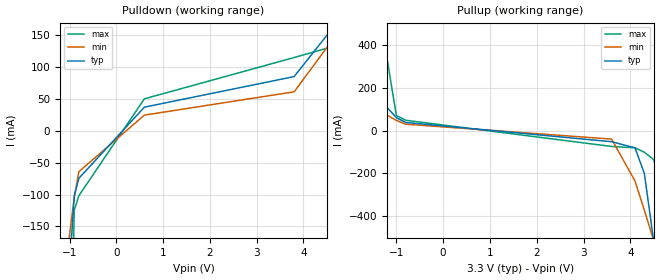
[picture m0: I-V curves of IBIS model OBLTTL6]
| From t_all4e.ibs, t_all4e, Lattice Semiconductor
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|   OBLTTL6
[Model]   OBLTTL6
Model_type   Output
Polarity   Non-Inverting
C_comp   2pF   2pF   2pF
[Temperature Range]   25.0000   125.0000   -40.0000
[Voltage Range]   3.3000V   3.0000V   3.6000V
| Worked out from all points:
|   slope of the pulldown table from 0 to 0.495 V, typ, clamps not added: 16.1 ohm
|   slope of the pullup table from 0 to 0.495 V, typ, clamps not added: 23.4 ohm
[Pulldown]
|voltage   I(typ)   I(min)   I(max)
-3.3V     -4.436A    -1.817A    -40.52A
-1.2V     -495.4mA   -285.6mA   -2.518A
-1.1V     -333.9mA   -220.6mA   -1.039A
-900mV    -102.6mA   -106.1mA   -124.8mA
-800mV    -74.67mA   -64.3mA    -101.9mA
600mV     36.53mA    24.07mA    49.56mA
3.8V      84.32mA    60.53mA    114.1mA
4.6V      158mA      139.6mA    130.7mA
4.8V      207.7mA    168.8mA    333.2mA
5.1V      290.8mA    217.3mA    813.3mA
5.4V      381.5mA    270mA      1.325A
6.6V      773.3mA    501.2mA    3.461A
[Pullup]
|voltage   I(typ)   I(min)   I(max)
-3.3V     752.9mA    436.3mA    3.973A
-2.5V     488.3mA    278.6mA    2.529A
-1.4V     155.1mA    96.47mA    603.1mA
-1V       59.98mA    47.2mA     69.78mA
-800mV    37.72mA    29.55mA    47.83mA
3.6V      -52.17mA   -39.93mA   -74.27mA
4.1V      -80.98mA   -235.7mA   -80.58mA
4.3V      -200.9mA   -372.2mA   -101.3mA
4.5V      -517.8mA   -513.7mA   -135.4mA
4.6V      -693.7mA   -585.4mA   -222mA
4.7V      -873.8mA   -657.6mA   -1.058A
6.6V      -4.462A    -2.062A    -35.02A
[Ramp]
| variable   typ   min   max
dV/dt_r   1.2315/1.0200ns   0.8308/2.3607ns   1.5922/0.3789ns
dV/dt_f   1.4788/1.1048ns   1.1687/2.4507ns   1.7342/0.5175ns
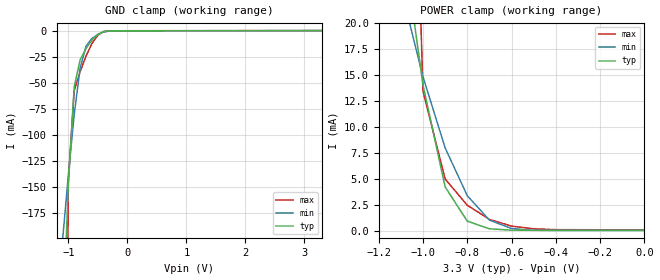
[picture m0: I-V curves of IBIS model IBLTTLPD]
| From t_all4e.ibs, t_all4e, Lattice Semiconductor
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|   IBLTTLPD
[Model]   IBLTTLPD
Model_type   Input
Polarity   Non-Inverting
C_comp   2pF   2pF   2pF
Vinl = 0.5
Vinh = 2.64
[Temperature Range]   25.0000   125.0000   -40.0000
[Voltage Range]   3.3000V   3.0000V   3.6000V
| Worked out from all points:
|   GND clamp passes 1 mA (typ) near -0.40 V on its own axis
|   POWER clamp passes 1 mA (typ) near -0.80 V on its own axis
[GND_clamp]
|voltage   I(typ)   I(min)   I(max)
-3.3V     -4.405A    -1.803A    -40.47A
-1.1V     -296.4mA   -202.8mA   -979.3mA
-1V       -147.6mA   -138.6mA   -143.7mA
-900mV    -53.79mA   -80.42mA   -57.6mA
-800mV    -28.05mA   -35.98mA   -39.41mA
-700mV    -17.1mA    -14.8mA    -24.33mA
-600mV    -8.999mA   -7.523mA   -12.36mA
-500mV    -3.595mA   -3.617mA   -4.359mA
-400mV    -879.9uA   -1.324mA   -818.8uA
-300mV    -134.5uA   -303.4uA   -113.2uA
3.3V      27.16uA    10.44uA    65.22uA
[POWER_clamp]
|voltage   I(typ)   I(min)   I(max)
-3.3V     682mA      379.6mA    3.878A
-1.1V     29.47mA    23.43mA    82.94mA
-1V       14.05mA    14.85mA    13.46mA
-900mV    4.218mA    7.985mA    4.978mA
-800mV    910uA      3.369mA    2.448mA
-700mV    172.8uA    1.011mA    1.084mA
-600mV    39.84uA    197.6uA    429.9uA
-500mV    27.92uA    30.49uA    170.3uA
-400mV    27.27uA    11.82uA    89.74uA
0V        27.16uA    10.3uA     65.38uA
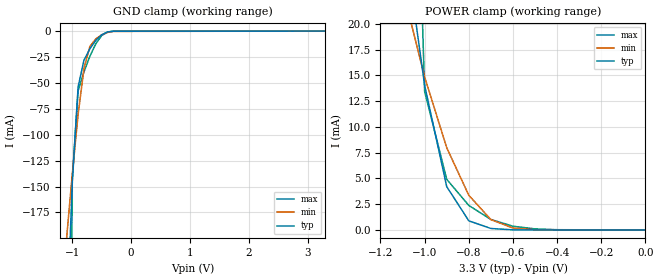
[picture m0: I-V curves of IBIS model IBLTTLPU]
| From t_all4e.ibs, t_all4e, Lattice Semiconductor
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|   IBLTTLPU
[Model]   IBLTTLPU
Model_type   Input
Polarity   Non-Inverting
C_comp   2pF   2pF   2pF
Vinl = 0.5
Vinh = 2.64
[Temperature Range]   25.0000   125.0000   -40.0000
[Voltage Range]   3.3000V   3.0000V   3.6000V
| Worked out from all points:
|   GND clamp passes 1 mA (typ) near -0.41 V on its own axis
|   POWER clamp passes 1 mA (typ) near -0.80 V on its own axis
[GND_clamp]
|voltage   I(typ)   I(min)   I(max)
-3.3V     -4.405A    -1.803A    -40.47A
-1.1V     -296.4mA   -202.8mA   -979.3mA
-1V       -147.6mA   -138.6mA   -143.7mA
-900mV    -53.78mA   -80.42mA   -57.54mA
-800mV    -28.01mA   -35.97mA   -39.33mA
-700mV    -17.06mA   -14.8mA    -24.26mA
-600mV    -8.965mA   -7.508mA   -12.31mA
-500mV    -3.57mA    -3.604mA   -4.321mA
-400mV    -864.4uA   -1.316mA   -796uA
-300mV    -129.4uA   -300.8uA   -106.6uA
3.3V      136.3nA    1.082uA    44.16nA
[POWER_clamp]
|voltage   I(typ)   I(min)   I(max)
-3.3V     682mA      379.6mA    3.878A
-1.1V     29.47mA    23.43mA    82.94mA
-1V       14.04mA    14.85mA    13.44mA
-900mV    4.209mA    7.985mA    4.915mA
-800mV    886uA      3.367mA    2.382mA
-700mV    145.7uA    1.006mA    1.019mA
-600mV    12.72uA    189uA      364.4uA
-500mV    804.9nA    21.16uA    104.9uA
-400mV    169.6nA    2.448uA    24.33uA
0V        136.3nA    964.9nA    94.06nA
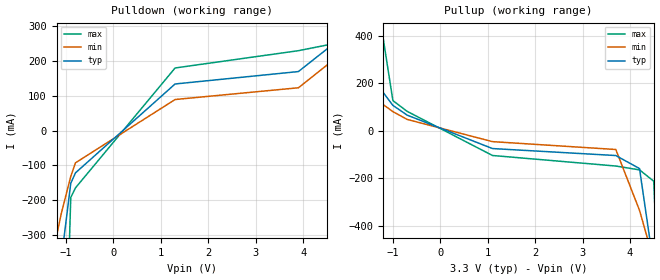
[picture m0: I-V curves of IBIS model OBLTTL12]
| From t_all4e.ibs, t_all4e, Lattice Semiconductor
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|   OBLTTL12
[Model]   OBLTTL12
Model_type   Output
Polarity   Non-Inverting
C_comp   2pF   2pF   2pF
[Temperature Range]   25.0000   125.0000   -40.0000
[Voltage Range]   3.3000V   3.0000V   3.6000V
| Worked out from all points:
|   slope of the pulldown table from 0 to 0.495 V, typ, clamps not added: 8.06 ohm
|   slope of the pullup table from 0 to 0.495 V, typ, clamps not added: 11.7 ohm
[Pulldown]
|voltage   I(typ)   I(min)   I(max)
-3.3V     -4.467A    -1.832A    -40.58A
-1.3V     -697.2mA   -368.1mA   -4.22A
-1.1V     -371.3mA   -238.3mA   -1.098A
-900mV    -151.4mA   -131.8mA   -192.1mA
-800mV    -121.4mA   -92.63mA   -164.5mA
1.3V      133.6mA    88.99mA    179.5mA
3.9V      169.2mA    122.7mA    229.1mA
4.6V      244.5mA    198.3mA    248mA
4.8V      294.8mA    227.9mA    451.2mA
5.1V      378.6mA    277mA      932.3mA
5.6V      533.5mA    367.2mA    1.795A
6.6V      864.6mA    563.3mA    3.585A
[Pullup]
|voltage   I(typ)   I(min)   I(max)
-3.3V     834.5mA    497.2mA    4.082A
-2.4V     531.4mA    315.7mA    2.447A
-1.4V     215.2mA    138.4mA    678.7mA
-1.3V     185.7mA    122.9mA    509.7mA
-1V       105.9mA    79.59mA    126.1mA
-700mV    64.88mA    46.78mA    80.73mA
1.1V      -75.92mA   -46.77mA   -105.1mA
3.7V      -105.3mA   -79.86mA   -149.4mA
4.2V      -160.1mA   -336.1mA   -165.7mA
4.5V      -571.5mA   -547mA     -213.3mA
4.7V      -927.9mA   -691.1mA   -1.137A
6.6V      -4.519A    -2.097A    -35.11A
[Ramp]
| variable   typ   min   max
dV/dt_r   1.5768/0.5268ns   1.2363/1.5430ns   1.8671/0.1960ns
dV/dt_f   1.7097/0.6904ns   1.4405/1.5774ns   1.9424/0.3192ns
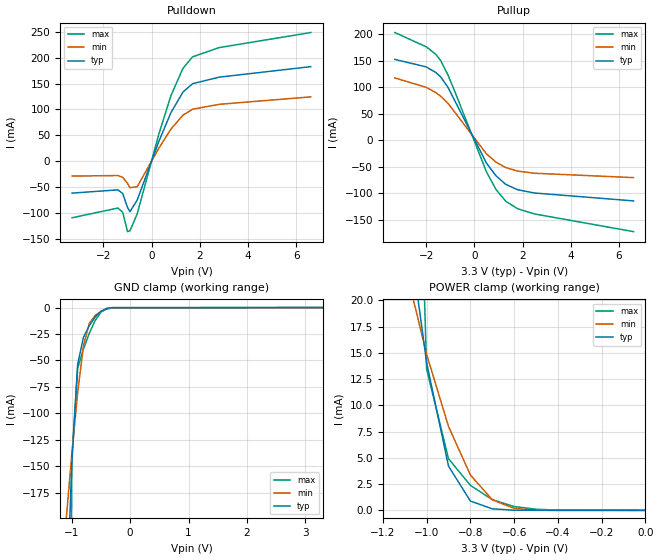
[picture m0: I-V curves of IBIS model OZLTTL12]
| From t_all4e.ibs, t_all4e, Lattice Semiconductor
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|   OZLTTL12
[Model]   OZLTTL12
Model_type   3-state
Polarity   Non-Inverting
Enable   Active-Low
C_comp   2pF   2pF   2pF
[Temperature Range]   25.0000   125.0000   -40.0000
[Voltage Range]   3.3000V   3.0000V   3.6000V
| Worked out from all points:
|   slope of the pulldown table from 0 to 0.495 V, typ, clamps not added: 8.06 ohm
|   slope of the pullup table from 0 to 0.495 V, typ, clamps not added: 11.7 ohm
|   GND clamp passes 1 mA (typ) near -0.41 V on its own axis
|   POWER clamp passes 1 mA (typ) near -0.80 V on its own axis
[Pulldown]
|voltage   I(typ)   I(min)   I(max)
-3.3V     -61.75mA   -28.81mA   -109.4mA
-1.4V     -55.45mA   -27.84mA   -90.61mA
-1.2V     -62.59mA   -31.19mA   -98.81mA
-1V       -89.62mA   -43.02mA   -136.2mA
-900mV    -97.6mA    -51.34mA   -134.6mA
-600mV    -75.27mA   -49.45mA   -102mA
300mV     38.39mA    25.14mA    52.57mA
800mV     93.76mA    61.98mA    126.6mA
1.3V      133.6mA    88.99mA    179.5mA
1.7V      149.7mA    100.4mA    201.6mA
2.8V      162.3mA    109.8mA    219.4mA
6.6V      182.6mA    124.2mA    248.5mA
[Pullup]
|voltage   I(typ)   I(min)   I(max)
-3.3V     152.5mA    117.6mA    203.1mA
-2V       138.4mA    99.96mA    176.3mA
-1.6V     127.9mA    90.05mA    162.3mA
-1.4V     119.7mA    83.23mA    150.6mA
-1.1V     100.3mA    70.12mA    123.6mA
-800mV    73.67mA    52.36mA    90.9mA
500mV     -42.74mA   -25.36mA   -59.21mA
900mV     -66.84mA   -41.03mA   -92.77mA
1.3V      -82.82mA   -51.19mA   -114.6mA
1.8V      -93.06mA   -57.92mA   -128.9mA
2.5V      -99.14mA   -61.92mA   -138.6mA
6.6V      -114mA     -70.13mA   -171.9mA
[GND_clamp]
|voltage   I(typ)   I(min)   I(max)
-3.3V     -4.405A    -1.803A    -40.47A
-1.1V     -296.4mA   -202.8mA   -979.3mA
-1V       -147.6mA   -138.6mA   -143.7mA
-900mV    -53.77mA   -80.42mA   -57.51mA
-800mV    -28mA      -35.97mA   -39.29mA
-700mV    -17.04mA   -14.79mA   -24.22mA
-600mV    -8.941mA   -7.498mA   -12.27mA
-500mV    -3.546mA   -3.592mA   -4.281mA
-400mV    -840.6uA   -1.303mA   -756.1uA
-300mV    -105.6uA   -288uA     -66.64uA
3.3V      136.3nA    1.082uA    44.16nA
[POWER_clamp]
|voltage   I(typ)   I(min)   I(max)
-3.3V     682mA      379.6mA    3.878A
-1.1V     29.47mA    23.43mA    82.94mA
-1V       14.04mA    14.85mA    13.44mA
-900mV    4.209mA    7.985mA    4.915mA
-800mV    886uA      3.367mA    2.382mA
-700mV    145.7uA    1.006mA    1.019mA
-600mV    12.72uA    189uA      364.4uA
-500mV    804.9nA    21.16uA    104.9uA
-400mV    169.6nA    2.448uA    24.33uA
0V        136.3nA    964.9nA    94.06nA
[Ramp]
| variable   typ   min   max
dV/dt_r   1.5768/0.5268ns   1.2363/1.5430ns   1.8671/0.1960ns
dV/dt_f   1.7097/0.6904ns   1.4405/1.5774ns   1.9424/0.3192ns
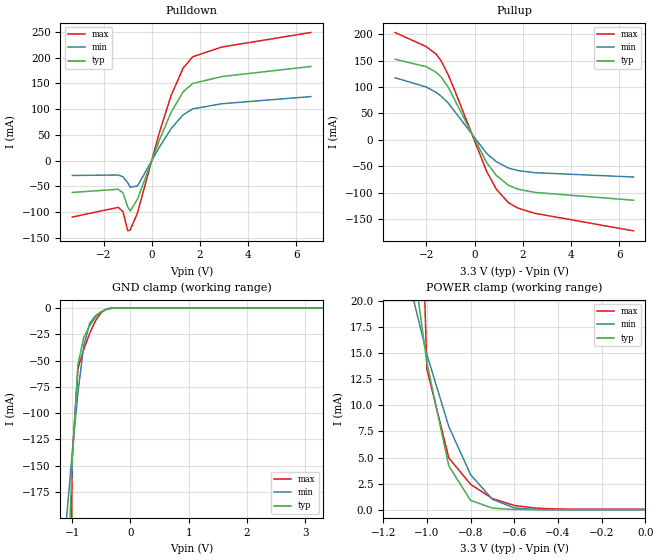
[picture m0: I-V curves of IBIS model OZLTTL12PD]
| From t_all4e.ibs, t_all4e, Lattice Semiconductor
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|   OZLTTL12PD
[Model]   OZLTTL12PD
Model_type   3-state
Polarity   Non-Inverting
Enable   Active-Low
C_comp   2pF   2pF   2pF
[Temperature Range]   25.0000   125.0000   -40.0000
[Voltage Range]   3.3000V   3.0000V   3.6000V
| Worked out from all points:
|   slope of the pulldown table from 0 to 0.495 V, typ, clamps not added: 8.07 ohm
|   slope of the pullup table from 0 to 0.495 V, typ, clamps not added: 11.7 ohm
|   GND clamp passes 1 mA (typ) near -0.40 V on its own axis
|   POWER clamp passes 1 mA (typ) near -0.80 V on its own axis
[Pulldown]
|voltage   I(typ)   I(min)   I(max)
-3.3V     -61.75mA   -28.81mA   -109.4mA
-1.4V     -55.45mA   -27.84mA   -90.61mA
-1.2V     -62.59mA   -31.19mA   -98.8mA
-1V       -89.61mA   -43.02mA   -136.2mA
-900mV    -97.58mA   -51.33mA   -134.5mA
-600mV    -75.21mA   -49.43mA   -101.9mA
300mV     38.37mA    25.13mA    52.53mA
800mV     93.72mA    61.97mA    126.5mA
1.3V      133.5mA    88.97mA    179.4mA
1.7V      149.6mA    100.4mA    201.5mA
2.9V      163mA      110.3mA    220.3mA
6.6V      182.6mA    124.2mA    248.5mA
[Pullup]
|voltage   I(typ)   I(min)   I(max)
-3.3V     152.5mA    117.6mA    203.1mA
-2V       138.4mA    99.96mA    176.3mA
-1.6V     127.9mA    90.05mA    162.3mA
-1.4V     119.7mA    83.23mA    150.6mA
-1.1V     100.3mA    70.12mA    123.6mA
-800mV    73.65mA    52.36mA    90.83mA
500mV     -42.76mA   -25.37mA   -59.27mA
900mV     -66.88mA   -41.05mA   -92.86mA
1.4V      -85.62mA   -52.99mA   -118.4mA
1.8V      -93.1mA    -57.94mA   -129mA
2.5V      -99.19mA   -61.94mA   -138.7mA
6.6V      -114mA     -70.13mA   -171.9mA
[GND_clamp]
|voltage   I(typ)   I(min)   I(max)
-3.3V     -4.405A    -1.803A    -40.47A
-1.1V     -296.4mA   -202.8mA   -979.3mA
-1V       -147.6mA   -138.6mA   -143.7mA
-900mV    -53.79mA   -80.42mA   -57.6mA
-800mV    -28.05mA   -35.98mA   -39.41mA
-700mV    -17.1mA    -14.8mA    -24.33mA
-600mV    -8.999mA   -7.523mA   -12.36mA
-500mV    -3.595mA   -3.617mA   -4.359mA
-400mV    -879.9uA   -1.324mA   -818.8uA
-300mV    -134.5uA   -303.4uA   -113.2uA
3.3V      27.16uA    10.44uA    65.22uA
[POWER_clamp]
|voltage   I(typ)   I(min)   I(max)
-3.3V     682mA      379.6mA    3.878A
-1.1V     29.47mA    23.43mA    82.94mA
-1V       14.05mA    14.85mA    13.46mA
-900mV    4.218mA    7.985mA    4.978mA
-800mV    910uA      3.369mA    2.448mA
-700mV    172.8uA    1.011mA    1.084mA
-600mV    39.84uA    197.6uA    429.9uA
-500mV    27.92uA    30.49uA    170.3uA
-400mV    27.27uA    11.82uA    89.74uA
0V        27.16uA    10.3uA     65.38uA
[Ramp]
| variable   typ   min   max
dV/dt_r   1.5768/0.5268ns   1.2363/1.5430ns   1.8671/0.1960ns
dV/dt_f   1.7097/0.6904ns   1.4405/1.5774ns   1.9424/0.3192ns
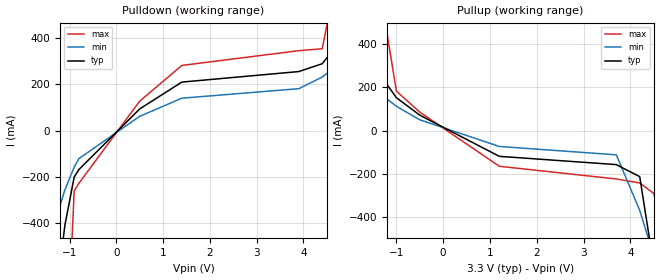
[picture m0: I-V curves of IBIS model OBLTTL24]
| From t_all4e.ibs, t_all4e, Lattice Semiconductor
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|   OBLTTL24
[Model]   OBLTTL24
Model_type   Output
Polarity   Non-Inverting
C_comp   2pF   2pF   2pF
[Temperature Range]   25.0000   125.0000   -40.0000
[Voltage Range]   3.3000V   3.0000V   3.6000V
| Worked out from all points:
|   slope of the pulldown table from 0 to 0.495 V, typ, clamps not added: 5.38 ohm
|   slope of the pullup table from 0 to 0.495 V, typ, clamps not added: 7.79 ohm
[Pulldown]
|voltage   I(typ)   I(min)   I(max)
-3.3V     -4.498A    -1.846A    -40.63A
-1.4V     -903mA     -451.1mA   -5.99A
-1.1V     -408.8mA   -256.1mA   -1.157A
-900mV    -200.2mA   -157.4mA   -259.4mA
-800mV    -168mA     -121mA     -227.2mA
500mV     92.94mA    61.11mA    126.4mA
1.4V      208.4mA    139.1mA    280.1mA
3.9V      253.8mA    180.1mA    343.6mA
4.4V      287.4mA    230.2mA    351.9mA
5.1V      466.4mA    336.6mA    1.051A
5.7V      655mA      446.7mA    2.093A
6.6V      955.9mA    625.4mA    3.709A
[Pullup]
|voltage   I(typ)   I(min)   I(max)
-3.3V     916.1mA    558.1mA    4.19A
-2.3V     572.9mA    351.3mA    2.362A
-1.3V     243mA      162.7mA    581.2mA
-1V       151.9mA    112mA      182.5mA
-500mV    71.07mA    49.53mA    85.15mA
1.2V      -119.4mA   -73.7mA    -165.3mA
3.7V      -157.6mA   -112.4mA   -224mA
4.2V      -213.3mA   -369.2mA   -242.4mA
4.5V      -625.2mA   -580.3mA   -291.2mA
4.6V      -801.4mA   -652.2mA   -378.6mA
4.7V      -981.9mA   -724.6mA   -1.215A
6.6V      -4.576A    -2.132A    -35.2A
[Ramp]
| variable   typ   min   max
dV/dt_r   1.7021/0.3465ns   1.3998/1.0389ns   1.9655/0.1535ns
dV/dt_f   1.7950/0.5692ns   1.5442/1.2795ns   2.0177/0.2629ns
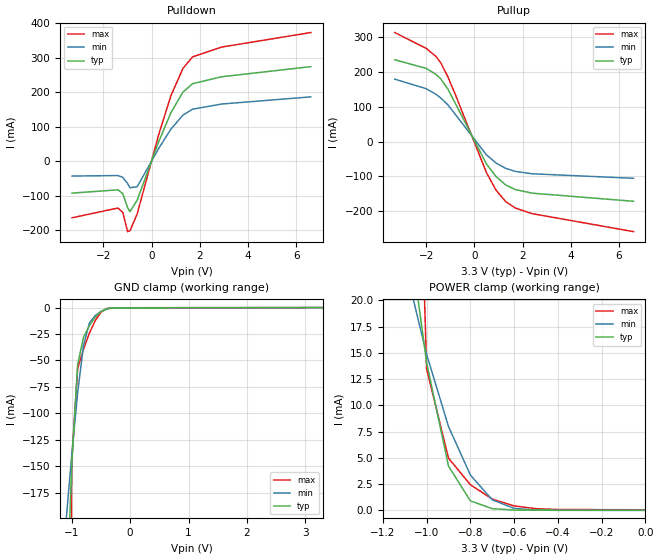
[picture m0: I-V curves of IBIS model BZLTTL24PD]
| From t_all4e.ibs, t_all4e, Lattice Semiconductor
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|   BZLTTL24PD
[Model]   BZLTTL24PD
Model_type   I/O
Polarity   Non-Inverting
Enable   Active-Low
C_comp   2pF   2pF   2pF
Vinl = 0.5
Vinh = 2.64
[Temperature Range]   25.0000   125.0000   -40.0000
[Voltage Range]   3.3000V   3.0000V   3.6000V
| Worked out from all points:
|   slope of the pulldown table from 0 to 0.495 V, typ, clamps not added: 5.38 ohm
|   slope of the pullup table from 0 to 0.495 V, typ, clamps not added: 7.79 ohm
|   GND clamp passes 1 mA (typ) near -0.40 V on its own axis
|   POWER clamp passes 1 mA (typ) near -0.80 V on its own axis
[Pulldown]
|voltage   I(typ)   I(min)   I(max)
-3.3V     -92.63mA   -43.21mA   -164.1mA
-1.4V     -83.18mA   -41.77mA   -135.9mA
-1.2V     -93.88mA   -46.78mA   -148.2mA
-1V       -134.4mA   -64.53mA   -204.3mA
-900mV    -146.4mA   -77mA      -201.8mA
-600mV    -112.8mA   -74.16mA   -152.9mA
300mV     57.56mA    37.7mA     78.81mA
800mV     140.6mA    92.96mA    189.8mA
1.3V      200.3mA    133.5mA    269.1mA
1.7V      224.5mA    150.6mA    302.3mA
2.9V      244.5mA    165.5mA    330.5mA
6.6V      273.9mA    186.3mA    372.7mA
[Pullup]
|voltage   I(typ)   I(min)   I(max)
-3.3V     234.1mA    178.5mA    312mA
-2V       209.4mA    151.3mA    266.7mA
-1.6V     192.5mA    135.6mA    244.2mA
-1.4V     179.8mA    125.1mA    226.2mA
-1.1V     150.4mA    105.2mA    185.4mA
-800mV    110.5mA    78.55mA    136.3mA
500mV     -64.13mA   -38.05mA   -88.87mA
900mV     -100.3mA   -61.56mA   -139.3mA
1.3V      -124.3mA   -76.81mA   -171.9mA
1.7V      -137.5mA   -85.45mA   -190.3mA
2.4V      -147.8mA   -92.32mA   -206.4mA
6.6V      -171mA     -105.2mA   -257.9mA
[GND_clamp]
|voltage   I(typ)   I(min)   I(max)
-3.3V     -4.405A    -1.803A    -40.47A
-1.1V     -296.4mA   -202.8mA   -979.3mA
-1V       -147.6mA   -138.6mA   -143.7mA
-900mV    -53.79mA   -80.42mA   -57.6mA
-800mV    -28.05mA   -35.98mA   -39.41mA
-700mV    -17.1mA    -14.8mA    -24.33mA
-600mV    -8.999mA   -7.523mA   -12.36mA
-500mV    -3.595mA   -3.617mA   -4.359mA
-400mV    -879.9uA   -1.324mA   -818.8uA
-300mV    -134.5uA   -303.4uA   -113.2uA
3.3V      27.16uA    10.44uA    65.22uA
[POWER_clamp]
|voltage   I(typ)   I(min)   I(max)
-3.3V     682mA      379.6mA    3.878A
-1.1V     29.47mA    23.43mA    82.94mA
-1V       14.05mA    14.85mA    13.46mA
-900mV    4.218mA    7.985mA    4.978mA
-800mV    910uA      3.369mA    2.448mA
-700mV    172.8uA    1.011mA    1.084mA
-600mV    39.84uA    197.6uA    429.9uA
-500mV    27.92uA    30.49uA    170.3uA
-400mV    27.27uA    11.82uA    89.74uA
0V        27.16uA    10.3uA     65.38uA
[Ramp]
| variable   typ   min   max
dV/dt_r   1.7021/0.3465ns   1.3998/1.0389ns   1.9655/0.1535ns
dV/dt_f   1.7950/0.5692ns   1.5442/1.2795ns   2.0177/0.2629ns
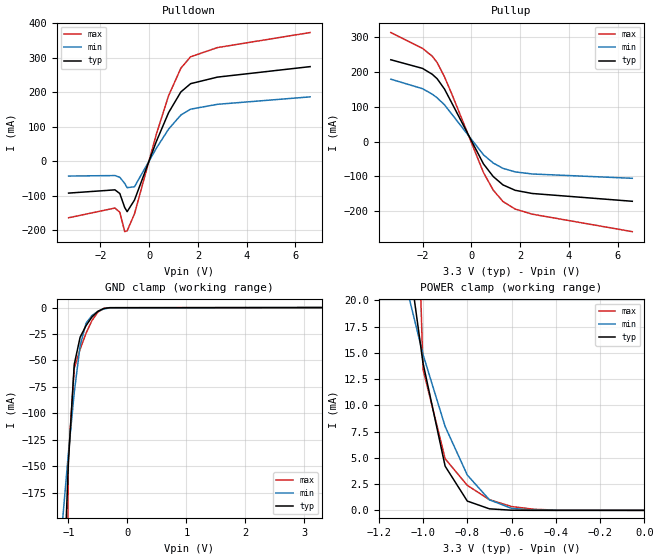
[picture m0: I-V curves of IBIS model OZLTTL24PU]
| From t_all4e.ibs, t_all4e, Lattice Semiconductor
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|   OZLTTL24PU
[Model]   OZLTTL24PU
Model_type   3-state
Polarity   Non-Inverting
Enable   Active-Low
C_comp   2pF   2pF   2pF
[Temperature Range]   25.0000   125.0000   -40.0000
[Voltage Range]   3.3000V   3.0000V   3.6000V
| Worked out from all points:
|   slope of the pulldown table from 0 to 0.495 V, typ, clamps not added: 5.38 ohm
|   slope of the pullup table from 0 to 0.495 V, typ, clamps not added: 7.79 ohm
|   GND clamp passes 1 mA (typ) near -0.41 V on its own axis
|   POWER clamp passes 1 mA (typ) near -0.80 V on its own axis
[Pulldown]
|voltage   I(typ)   I(min)   I(max)
-3.3V     -92.63mA   -43.21mA   -164.1mA
-1.4V     -83.18mA   -41.77mA   -135.9mA
-1.2V     -93.89mA   -46.78mA   -148.2mA
-1V       -134.4mA   -64.53mA   -204.3mA
-900mV    -146.4mA   -77mA      -201.9mA
-600mV    -112.9mA   -74.17mA   -153mA
300mV     57.61mA    37.72mA    78.89mA
800mV     140.7mA    92.99mA    189.9mA
1.3V      200.4mA    133.5mA    269.2mA
1.7V      224.5mA    150.6mA    302.4mA
2.8V      243.5mA    164.7mA    329.1mA
6.6V      273.9mA    186.3mA    372.7mA
[Pullup]
|voltage   I(typ)   I(min)   I(max)
-3.3V     234.1mA    178.5mA    312mA
-2V       209.4mA    151.3mA    266.7mA
-1.6V     192.5mA    135.6mA    244.2mA
-1.4V     179.8mA    125.1mA    226.2mA
-1.1V     150.4mA    105.2mA    185.4mA
-800mV    110.5mA    78.55mA    136.3mA
500mV     -64.1mA    -38.04mA   -88.81mA
900mV     -100.2mA   -61.53mA   -139.1mA
1.3V      -124.2mA   -76.78mA   -171.8mA
1.8V      -139.6mA   -86.86mA   -193.3mA
2.5V      -148.7mA   -92.87mA   -207.9mA
6.6V      -171mA     -105.2mA   -257.9mA
[GND_clamp]
|voltage   I(typ)   I(min)   I(max)
-3.3V     -4.405A    -1.803A    -40.47A
-1.1V     -296.4mA   -202.8mA   -979.3mA
-1V       -147.6mA   -138.6mA   -143.7mA
-900mV    -53.78mA   -80.42mA   -57.54mA
-800mV    -28.01mA   -35.97mA   -39.33mA
-700mV    -17.06mA   -14.8mA    -24.26mA
-600mV    -8.965mA   -7.508mA   -12.31mA
-500mV    -3.57mA    -3.604mA   -4.321mA
-400mV    -864.4uA   -1.316mA   -796uA
-300mV    -129.4uA   -300.8uA   -106.6uA
3.3V      136.3nA    1.082uA    44.16nA
[POWER_clamp]
|voltage   I(typ)   I(min)   I(max)
-3.3V     682mA      379.6mA    3.878A
-1.1V     29.47mA    23.43mA    82.94mA
-1V       14.04mA    14.85mA    13.44mA
-900mV    4.209mA    7.985mA    4.915mA
-800mV    886uA      3.367mA    2.382mA
-700mV    145.7uA    1.006mA    1.019mA
-600mV    12.72uA    189uA      364.4uA
-500mV    804.9nA    21.16uA    104.9uA
-400mV    169.6nA    2.448uA    24.33uA
0V        136.3nA    964.9nA    94.06nA
[Ramp]
| variable   typ   min   max
dV/dt_r   1.7021/0.3465ns   1.3998/1.0389ns   1.9655/0.1535ns
dV/dt_f   1.7950/0.5692ns   1.5442/1.2795ns   2.0177/0.2629ns
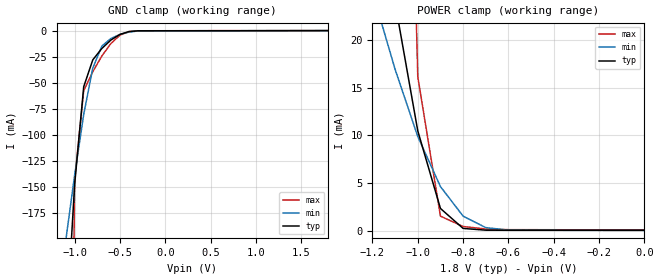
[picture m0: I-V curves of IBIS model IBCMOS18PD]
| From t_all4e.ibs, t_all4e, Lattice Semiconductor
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|   IBCMOS18PD
[Model]   IBCMOS18PD
Model_type   Input
Polarity   Non-Inverting
C_comp   2pF   2pF   2pF
Vinl = 0.5
Vinh = 2.64
[Temperature Range]   25.0000   125.0000   -40.0000
[Voltage Range]   1.8000V   1.7000V   1.9000V
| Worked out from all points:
|   GND clamp passes 1 mA (typ) near -0.40 V on its own axis
|   POWER clamp passes 1 mA (typ) near -0.84 V on its own axis
[GND_clamp]
|voltage   I(typ)   I(min)   I(max)
-1.8V     -1.559A    -696.5mA   -12.99A
-1.1V     -296.4mA   -202.8mA   -979.3mA
-1V       -147.6mA   -138.6mA   -143.7mA
-900mV    -53.79mA   -80.42mA   -57.6mA
-800mV    -28.05mA   -35.98mA   -39.41mA
-700mV    -17.1mA    -14.8mA    -24.32mA
-600mV    -8.998mA   -7.523mA   -12.36mA
-500mV    -3.594mA   -3.617mA   -4.358mA
-400mV    -878.9uA   -1.323mA   -817.5uA
-300mV    -133.8uA   -302.9uA   -112.1uA
1.8V      37.23uA    16.06uA    76uA
[POWER_clamp]
|voltage   I(typ)   I(min)   I(max)
-1.8V     178.5mA    91.31mA    1.213A
-1.2V     41.11mA    25.02mA    244.3mA
-1.1V     23.87mA    16.9mA     108.1mA
-1V       10.45mA    9.86mA     16.13mA
-900mV    2.324mA    4.618mA    1.514mA
-800mV    230.5uA    1.518mA    431.6uA
-700mV    46.81uA    315.4uA    170.6uA
-600mV    37.66uA    50.45uA    98.99uA
0V        37.23uA    16.04uA    76.01uA
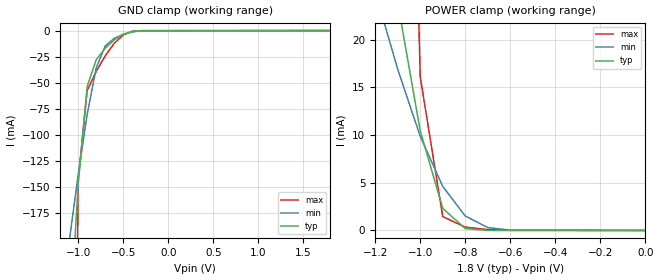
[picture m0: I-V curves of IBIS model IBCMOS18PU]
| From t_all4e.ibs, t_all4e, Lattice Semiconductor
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|   IBCMOS18PU
[Model]   IBCMOS18PU
Model_type   Input
Polarity   Non-Inverting
C_comp   2pF   2pF   2pF
Vinl = 0.5
Vinh = 2.64
[Temperature Range]   25.0000   125.0000   -40.0000
[Voltage Range]   1.8000V   1.7000V   1.9000V
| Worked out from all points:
|   GND clamp passes 1 mA (typ) near -0.41 V on its own axis
|   POWER clamp passes 1 mA (typ) near -0.84 V on its own axis
[GND_clamp]
|voltage   I(typ)   I(min)   I(max)
-1.8V     -1.559A    -696.5mA   -12.99A
-1.1V     -296.4mA   -202.8mA   -979.3mA
-1V       -147.6mA   -138.6mA   -143.7mA
-900mV    -53.77mA   -80.42mA   -57.51mA
-800mV    -28mA      -35.97mA   -39.3mA
-700mV    -17.04mA   -14.79mA   -24.23mA
-600mV    -8.945mA   -7.5mA     -12.27mA
-500mV    -3.55mA    -3.594mA   -4.287mA
-400mV    -844.2uA   -1.305mA   -762uA
-300mV    -109.2uA   -290.3uA   -72.54uA
1.8V      100.3nA    783.2nA    29.03nA
[POWER_clamp]
|voltage   I(typ)   I(min)   I(max)
-1.8V     178.5mA    91.31mA    1.213A
-1.2V     41.11mA    25.02mA    244.3mA
-1.1V     23.87mA    16.9mA     108.1mA
-1V       10.45mA    9.859mA    16.11mA
-900mV    2.311mA    4.617mA    1.45mA
-800mV    197.4uA    1.514mA    355.7uA
-700mV    9.769uA    305.2uA    94.53uA
-600mV    528.6nA    35.7uA     22.97uA
0V        100.3nA    769nA      31.1nA
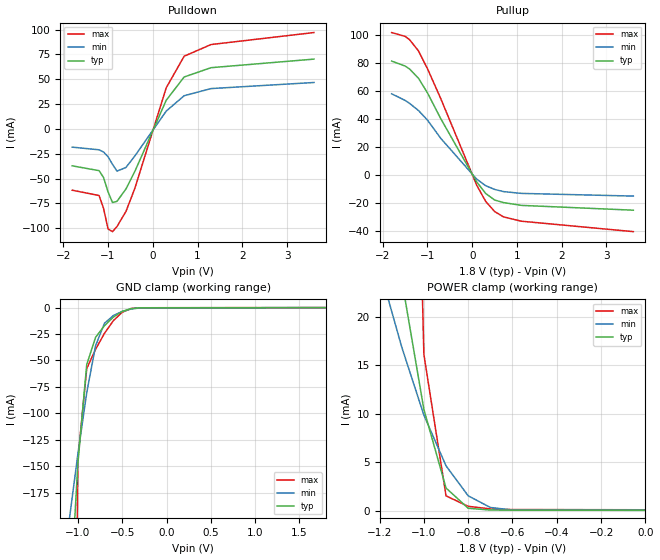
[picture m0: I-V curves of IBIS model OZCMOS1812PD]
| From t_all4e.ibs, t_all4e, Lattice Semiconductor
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|   OZCMOS1812PD
[Model]   OZCMOS1812PD
Model_type   3-state
Polarity   Non-Inverting
Enable   Active-Low
C_comp   2pF   2pF   2pF
[Temperature Range]   25.0000   125.0000   -40.0000
[Voltage Range]   1.8000V   1.7000V   1.9000V
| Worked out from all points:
|   slope of the pulldown table from 0 to 0.27 V, typ, clamps not added: 10.3 ohm
|   slope of the pullup table from 0 to 0.27 V, typ, clamps not added: 22.3 ohm
|   GND clamp passes 1 mA (typ) near -0.40 V on its own axis
|   POWER clamp passes 1 mA (typ) near -0.84 V on its own axis
[Pulldown]
|voltage   I(typ)   I(min)   I(max)
-1.8V     -37.15mA   -18.33mA   -61.7mA
-1.2V     -41.99mA   -21mA      -67.05mA
-1.1V     -48.97mA   -23.25mA   -80.05mA
-1V       -63.34mA   -27.91mA   -100.7mA
-900mV    -74.16mA   -35.69mA   -103.4mA
-800mV    -72.86mA   -42.44mA   -98.26mA
-600mV    -60.45mA   -38.8mA    -83.09mA
-400mV    -42.63mA   -27.14mA   -59.66mA
300mV     28.9mA     17.99mA    41.44mA
700mV     52.31mA    33.45mA    73.22mA
1.3V      61.68mA    40.63mA    84.98mA
3.6V      70.31mA    46.78mA    97.07mA
[Pullup]
|voltage   I(typ)   I(min)   I(max)
-1.8V     81.38mA    58mA       101.8mA
-1.5V     77.86mA    53.27mA    99.04mA
-1.4V     75.75mA    51.16mA    96.71mA
-1.2V     69.07mA    46.02mA    88.6mA
-1V       58.66mA    39.19mA    75.99mA
-700mV    40.03mA    26.02mA    54.32mA
100mV     -5.039mA   -3.027mA   -7.383mA
300mV     -13.26mA   -7.729mA   -18.91mA
500mV     -17.98mA   -10.39mA   -26.19mA
700mV     -19.83mA   -11.97mA   -30.05mA
1.1V      -21.82mA   -13.25mA   -33.14mA
3.6V      -25.26mA   -15.17mA   -40.6mA
[GND_clamp]
|voltage   I(typ)   I(min)   I(max)
-1.8V     -1.559A    -696.5mA   -12.99A
-1.1V     -296.4mA   -202.8mA   -979.3mA
-1V       -147.6mA   -138.6mA   -143.7mA
-900mV    -53.79mA   -80.42mA   -57.6mA
-800mV    -28.05mA   -35.98mA   -39.41mA
-700mV    -17.1mA    -14.8mA    -24.32mA
-600mV    -8.998mA   -7.523mA   -12.36mA
-500mV    -3.594mA   -3.617mA   -4.358mA
-400mV    -878.9uA   -1.323mA   -817.5uA
-300mV    -133.8uA   -302.9uA   -112.1uA
1.8V      37.23uA    16.06uA    76uA
[POWER_clamp]
|voltage   I(typ)   I(min)   I(max)
-1.8V     178.5mA    91.31mA    1.213A
-1.2V     41.11mA    25.02mA    244.3mA
-1.1V     23.87mA    16.9mA     108.1mA
-1V       10.45mA    9.86mA     16.13mA
-900mV    2.324mA    4.618mA    1.514mA
-800mV    230.5uA    1.518mA    431.6uA
-700mV    46.81uA    315.4uA    170.6uA
-600mV    37.66uA    50.45uA    98.99uA
0V        37.23uA    16.04uA    76.01uA
[Ramp]
| variable   typ   min   max
dV/dt_r   0.5829/1.1878ns   0.3820/3.2046ns   0.8219/0.6728ns
dV/dt_f   0.8963/1.7730ns   0.7346/3.8795ns   0.9962/0.7255ns
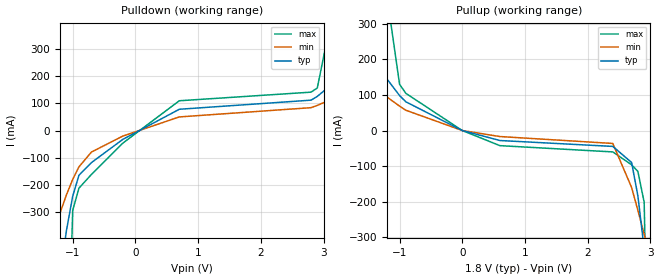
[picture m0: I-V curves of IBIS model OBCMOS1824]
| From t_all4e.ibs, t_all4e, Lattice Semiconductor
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|   OBCMOS1824
[Model]   OBCMOS1824
Model_type   Output
Polarity   Non-Inverting
C_comp   2pF   2pF   2pF
[Temperature Range]   25.0000   125.0000   -40.0000
[Voltage Range]   1.8000V   1.7000V   1.9000V
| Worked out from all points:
|   slope of the pulldown table from 0 to 0.27 V, typ, clamps not added: 6.84 ohm
|   slope of the pullup table from 0 to 0.27 V, typ, clamps not added: 14.9 ohm
[Pulldown]
|voltage   I(typ)   I(min)   I(max)
-1.8V     -1.615A    -724mA     -13.08A
-1.3V     -698.9mA   -368.9mA   -4.224A
-1.1V     -369.9mA   -237.7mA   -1.099A
-1V       -242.6mA   -180.4mA   -294.8mA
-900mV    -165mA     -134mA     -212.7mA
-700mV    -118.2mA   -79.21mA   -161.8mA
-200mV    -32.55mA   -20.5mA    -46.41mA
700mV     78.52mA    50.2mA     109.9mA
2.8V      112.1mA    84.42mA    141.7mA
2.9V      126mA      92.89mA    157mA
3.1V      164.3mA    112.4mA    386.6mA
3.6V      284mA      175.1mA    1.191A
[Pullup]
|voltage   I(typ)   I(min)   I(max)
-1.8V     302.1mA    179.4mA    1.368A
-1.2V     144.8mA    94.2mA     377.3mA
-1V       98.44mA    68.67mA    130.1mA
-900mV    80.86mA    57.13mA    104.7mA
0V        100.3nA    769nA      31.1nA
600mV     -28.16mA   -16.93mA   -42.56mA
2.4V      -44.71mA   -36.43mA   -60.22mA
2.7V      -90.1mA    -160.5mA   -96.51mA
2.8V      -184.1mA   -224.8mA   -115.1mA
2.9V      -333.1mA   -292.2mA   -201.8mA
3V        -501mA     -361.3mA   -1.038A
3.6V      -1.597A    -792mA     -11.25A
[Ramp]
| variable   typ   min   max
dV/dt_r   0.7420/1.0977ns   0.5286/3.1380ns   0.9363/0.5057ns
dV/dt_f   0.9553/1.4667ns   0.8232/3.3353ns   1.0428/0.6059ns
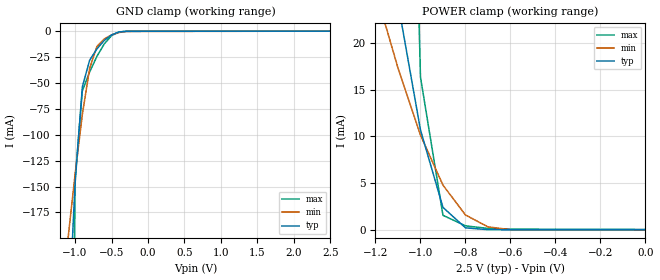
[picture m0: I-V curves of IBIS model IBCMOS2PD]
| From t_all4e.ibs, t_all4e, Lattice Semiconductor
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|   IBCMOS2PD
[Model]   IBCMOS2PD
Model_type   Input
Polarity   Non-Inverting
C_comp   2pF   2pF   2pF
Vinl = 0.5
Vinh = 2.64
[Temperature Range]   25.0000   125.0000   -40.0000
[Voltage Range]   2.5000V   2.3000V   2.7000V
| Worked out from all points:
|   GND clamp passes 1 mA (typ) near -0.40 V on its own axis
|   POWER clamp passes 1 mA (typ) near -0.83 V on its own axis
[GND_clamp]
|voltage   I(typ)   I(min)   I(max)
-2.5V     -2.88A     -1.21A     -25.75A
-1.1V     -296.4mA   -202.8mA   -979.3mA
-1V       -147.6mA   -138.6mA   -143.7mA
-900mV    -53.79mA   -80.42mA   -57.6mA
-800mV    -28.05mA   -35.98mA   -39.41mA
-700mV    -17.1mA    -14.8mA    -24.32mA
-600mV    -8.999mA   -7.523mA   -12.36mA
-500mV    -3.595mA   -3.617mA   -4.359mA
-400mV    -879.6uA   -1.324mA   -818.4uA
-300mV    -134.3uA   -303.2uA   -112.8uA
2.5V      32.9uA     13.5uA     72.78uA
[POWER_clamp]
|voltage   I(typ)   I(min)   I(max)
-2.5V     395.1mA    211mA      2.446A
-1.2V     41.69mA    25.58mA    245.1mA
-1.1V     24.27mA    17.3mA     108.6mA
-1V       10.69mA    10.14mA    16.34mA
-900mV    2.423mA    4.798mA    1.578mA
-800mV    241uA      1.613mA    455.8uA
-700mV    43.59uA    342.3uA    178.8uA
-600mV    33.48uA    49.81uA    99.8uA
0V        32.9uA     13.46uA    72.82uA
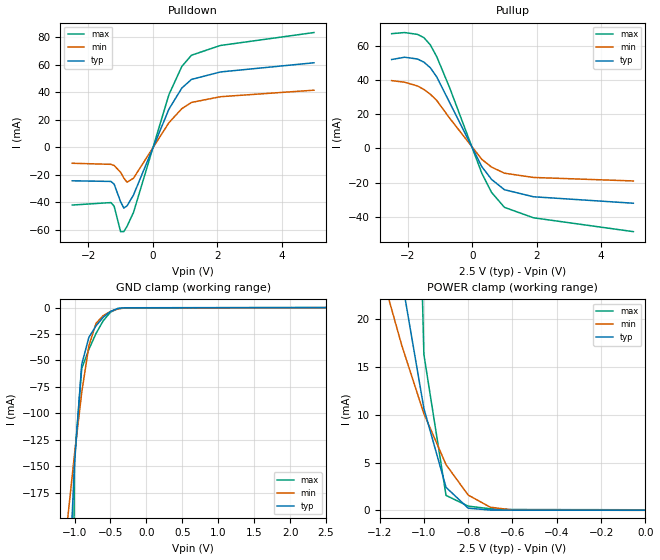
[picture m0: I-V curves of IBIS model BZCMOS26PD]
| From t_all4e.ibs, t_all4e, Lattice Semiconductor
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|   BZCMOS26PD
[Model]   BZCMOS26PD
Model_type   I/O
Polarity   Non-Inverting
Enable   Active-Low
C_comp   2pF   2pF   2pF
Vinl = 0.5
Vinh = 2.64
[Temperature Range]   25.0000   125.0000   -40.0000
[Voltage Range]   2.5000V   2.3000V   2.7000V
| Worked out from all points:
|   slope of the pulldown table from 0 to 0.375 V, typ, clamps not added: 17.5 ohm
|   slope of the pullup table from 0 to 0.375 V, typ, clamps not added: 28.8 ohm
|   GND clamp passes 1 mA (typ) near -0.40 V on its own axis
|   POWER clamp passes 1 mA (typ) near -0.83 V on its own axis
[Pulldown]
|voltage   I(typ)   I(min)   I(max)
-2.5V     -24.4mA    -11.67mA   -42mA
-1.3V     -24.85mA   -12.45mA   -40.21mA
-1.2V     -26.81mA   -13.29mA   -42.81mA
-1V       -39.59mA   -18.18mA   -61.3mA
-900mV    -44.19mA   -22.41mA   -61.31mA
-800mV    -42.64mA   -25.41mA   -57.45mA
-600mV    -34.74mA   -22.55mA   -47.42mA
500mV     27.6mA     17.77mA    38.15mA
900mV     42.92mA    27.98mA    58.59mA
1.2V      49.19mA    32.47mA    66.78mA
2.1V      54.62mA    36.65mA    73.84mA
5V        61.27mA    41.38mA    83.23mA
[Pullup]
|voltage   I(typ)   I(min)   I(max)
-2.5V     52.17mA    39.78mA    67.34mA
-2.1V     53.51mA    38.86mA    68mA
-1.7V     52.49mA    36.68mA    66.93mA
-1.5V     50.64mA    34.62mA    65.02mA
-1.3V     47.36mA    31.82mA    60.78mA
-1.1V     41.93mA    28.14mA    53.81mA
-700mV    26.93mA    17.77mA    35.6mA
300mV     -10.74mA   -6.443mA   -14.64mA
600mV     -18.14mA   -10.93mA   -25.78mA
1V        -24.21mA   -14.51mA   -34.55mA
1.9V      -28.34mA   -17.01mA   -40.67mA
5V        -32.13mA   -19.07mA   -48.8mA
[GND_clamp]
|voltage   I(typ)   I(min)   I(max)
-2.5V     -2.88A     -1.21A     -25.75A
-1.1V     -296.4mA   -202.8mA   -979.3mA
-1V       -147.6mA   -138.6mA   -143.7mA
-900mV    -53.79mA   -80.42mA   -57.6mA
-800mV    -28.05mA   -35.98mA   -39.41mA
-700mV    -17.1mA    -14.8mA    -24.32mA
-600mV    -8.999mA   -7.523mA   -12.36mA
-500mV    -3.595mA   -3.617mA   -4.359mA
-400mV    -879.6uA   -1.324mA   -818.4uA
-300mV    -134.3uA   -303.2uA   -112.8uA
2.5V      32.9uA     13.5uA     72.78uA
[POWER_clamp]
|voltage   I(typ)   I(min)   I(max)
-2.5V     395.1mA    211mA      2.446A
-1.2V     41.69mA    25.58mA    245.1mA
-1.1V     24.27mA    17.3mA     108.6mA
-1V       10.69mA    10.14mA    16.34mA
-900mV    2.423mA    4.798mA    1.578mA
-800mV    241uA      1.613mA    455.8uA
-700mV    43.59uA    342.3uA    178.8uA
-600mV    33.48uA    49.81uA    99.8uA
0V        32.9uA     13.46uA    72.82uA
[Ramp]
| variable   typ   min   max
dV/dt_r   0.7744/1.4653ns   0.4838/2.7623ns   1.0783/0.5514ns
dV/dt_f   1.0873/1.4903ns   0.8475/3.2615ns   1.2705/0.6577ns
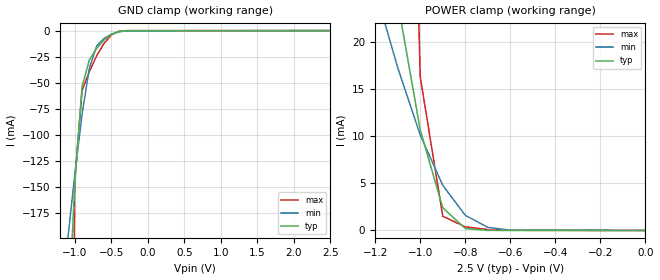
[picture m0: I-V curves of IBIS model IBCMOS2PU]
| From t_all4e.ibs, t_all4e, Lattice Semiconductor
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|   IBCMOS2PU
[Model]   IBCMOS2PU
Model_type   Input
Polarity   Non-Inverting
C_comp   2pF   2pF   2pF
Vinl = 0.5
Vinh = 2.64
[Temperature Range]   25.0000   125.0000   -40.0000
[Voltage Range]   2.5000V   2.3000V   2.7000V
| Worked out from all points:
|   GND clamp passes 1 mA (typ) near -0.41 V on its own axis
|   POWER clamp passes 1 mA (typ) near -0.84 V on its own axis
[GND_clamp]
|voltage   I(typ)   I(min)   I(max)
-2.5V     -2.88A     -1.21A     -25.75A
-1.1V     -296.4mA   -202.8mA   -979.3mA
-1V       -147.6mA   -138.6mA   -143.7mA
-900mV    -53.77mA   -80.42mA   -57.52mA
-800mV    -28mA      -35.97mA   -39.31mA
-700mV    -17.05mA   -14.79mA   -24.24mA
-600mV    -8.952mA   -7.503mA   -12.29mA
-500mV    -3.558mA   -3.598mA   -4.3mA
-400mV    -852uA     -1.309mA   -775.3uA
-300mV    -117uA     -294.4uA   -85.91uA
2.5V      116nA      886.3nA    35.24nA
[POWER_clamp]
|voltage   I(typ)   I(min)   I(max)
-2.5V     395.1mA    211mA      2.446A
-1.2V     41.69mA    25.58mA    245.1mA
-1.1V     24.27mA    17.3mA     108.6mA
-1V       10.69mA    10.14mA    16.33mA
-900mV    2.413mA    4.797mA    1.516mA
-800mV    211.8uA    1.609mA    382.9uA
-700mV    10.83uA    333.9uA    105.9uA
-600mV    637nA      37.63uA    26.9uA
0V        116nA      855.7nA    39.22nA
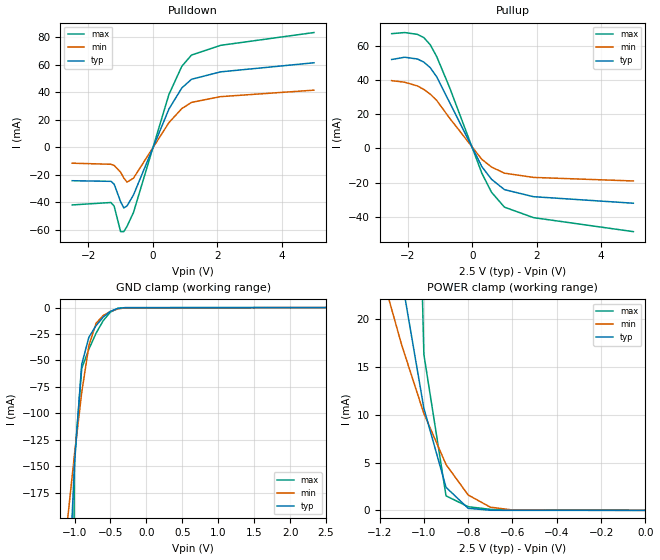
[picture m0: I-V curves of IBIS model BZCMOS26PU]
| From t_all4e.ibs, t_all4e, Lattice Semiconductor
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|   BZCMOS26PU
[Model]   BZCMOS26PU
Model_type   I/O
Polarity   Non-Inverting
Enable   Active-Low
C_comp   2pF   2pF   2pF
Vinl = 0.5
Vinh = 2.64
[Temperature Range]   25.0000   125.0000   -40.0000
[Voltage Range]   2.5000V   2.3000V   2.7000V
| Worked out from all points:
|   slope of the pulldown table from 0 to 0.375 V, typ, clamps not added: 17.5 ohm
|   slope of the pullup table from 0 to 0.375 V, typ, clamps not added: 28.8 ohm
|   GND clamp passes 1 mA (typ) near -0.41 V on its own axis
|   POWER clamp passes 1 mA (typ) near -0.84 V on its own axis
[Pulldown]
|voltage   I(typ)   I(min)   I(max)
-2.5V     -24.4mA    -11.67mA   -42mA
-1.3V     -24.85mA   -12.46mA   -40.22mA
-1.2V     -26.82mA   -13.3mA    -42.82mA
-1V       -39.6mA    -18.18mA   -61.33mA
-900mV    -44.21mA   -22.41mA   -61.39mA
-800mV    -42.69mA   -25.42mA   -57.55mA
-600mV    -34.78mA   -22.57mA   -47.49mA
500mV     27.65mA    17.79mA    38.23mA
900mV     42.97mA    28mA       58.7mA
1.2V      49.26mA    32.49mA    66.88mA
2.1V      54.66mA    36.66mA    73.92mA
5V        61.27mA    41.38mA    83.23mA
[Pullup]
|voltage   I(typ)   I(min)   I(max)
-2.5V     52.17mA    39.78mA    67.34mA
-2.1V     53.51mA    38.86mA    68mA
-1.7V     52.49mA    36.68mA    66.93mA
-1.5V     50.64mA    34.62mA    65.02mA
-1.3V     47.36mA    31.82mA    60.78mA
-1.1V     41.93mA    28.14mA    53.81mA
-700mV    26.97mA    17.77mA    35.67mA
300mV     -10.71mA   -6.431mA   -14.57mA
600mV     -18.1mA    -10.92mA   -25.71mA
1V        -24.16mA   -14.49mA   -34.44mA
1.9V      -28.29mA   -16.99mA   -40.57mA
5V        -32.13mA   -19.07mA   -48.8mA
[GND_clamp]
|voltage   I(typ)   I(min)   I(max)
-2.5V     -2.88A     -1.21A     -25.75A
-1.1V     -296.4mA   -202.8mA   -979.3mA
-1V       -147.6mA   -138.6mA   -143.7mA
-900mV    -53.77mA   -80.42mA   -57.52mA
-800mV    -28mA      -35.97mA   -39.31mA
-700mV    -17.05mA   -14.79mA   -24.24mA
-600mV    -8.952mA   -7.503mA   -12.29mA
-500mV    -3.558mA   -3.598mA   -4.3mA
-400mV    -852uA     -1.309mA   -775.3uA
-300mV    -117uA     -294.4uA   -85.91uA
2.5V      116nA      886.3nA    35.24nA
[POWER_clamp]
|voltage   I(typ)   I(min)   I(max)
-2.5V     395.1mA    211mA      2.446A
-1.2V     41.69mA    25.58mA    245.1mA
-1.1V     24.27mA    17.3mA     108.6mA
-1V       10.69mA    10.14mA    16.33mA
-900mV    2.413mA    4.797mA    1.516mA
-800mV    211.8uA    1.609mA    382.9uA
-700mV    10.83uA    333.9uA    105.9uA
-600mV    637nA      37.63uA    26.9uA
0V        116nA      855.7nA    39.22nA
[Ramp]
| variable   typ   min   max
dV/dt_r   0.7744/1.4653ns   0.4838/2.7623ns   1.0783/0.5514ns
dV/dt_f   1.0873/1.4903ns   0.8475/3.2615ns   1.2705/0.6577ns
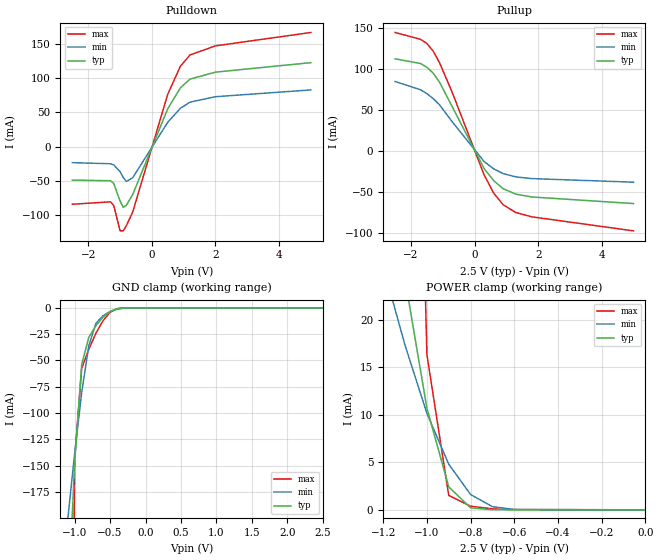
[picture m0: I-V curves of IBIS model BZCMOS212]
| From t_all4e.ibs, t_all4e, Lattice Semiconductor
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|   BZCMOS212
[Model]   BZCMOS212
Model_type   I/O
Polarity   Non-Inverting
Enable   Active-Low
C_comp   2pF   2pF   2pF
Vinl = 0.5
Vinh = 2.64
[Temperature Range]   25.0000   125.0000   -40.0000
[Voltage Range]   2.5000V   2.3000V   2.7000V
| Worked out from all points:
|   slope of the pulldown table from 0 to 0.375 V, typ, clamps not added: 8.75 ohm
|   slope of the pullup table from 0 to 0.375 V, typ, clamps not added: 14.4 ohm
|   GND clamp passes 1 mA (typ) near -0.41 V on its own axis
|   POWER clamp passes 1 mA (typ) near -0.84 V on its own axis
[Pulldown]
|voltage   I(typ)   I(min)   I(max)
-2.5V     -48.8mA    -23.34mA   -84mA
-1.3V     -49.7mA    -24.91mA   -80.44mA
-1.2V     -53.64mA   -26.59mA   -85.65mA
-1V       -79.2mA    -36.37mA   -122.7mA
-900mV    -88.42mA   -44.82mA   -122.8mA
-800mV    -85.39mA   -50.84mA   -115.1mA
-600mV    -69.59mA   -45.15mA   -95.02mA
500mV     55.27mA    35.56mA    76.43mA
900mV     85.92mA    56mA       117.4mA
1.2V      98.49mA    64.97mA    133.7mA
2V        108.7mA    72.86mA    147mA
5V        122.5mA    82.76mA    166.5mA
[Pullup]
|voltage   I(typ)   I(min)   I(max)
-2.5V     112.7mA    84.9mA     144.8mA
-1.7V     106.9mA    74.88mA    136.5mA
-1.5V     102.3mA    70.1mA     131.4mA
-1.3V     95.06mA    64.02mA    122mA
-1.1V     83.89mA    56.39mA    107.7mA
-700mV    53.93mA    35.55mA    71.35mA
300mV     -21.42mA   -12.86mA   -29.14mA
600mV     -36.21mA   -21.84mA   -51.42mA
900mV     -46.1mA    -27.66mA   -65.73mA
1.3V      -52.77mA   -31.65mA   -75.23mA
1.8V      -56.18mA   -33.74mA   -80.45mA
5V        -64.25mA   -38.14mA   -97.6mA
[GND_clamp]
|voltage   I(typ)   I(min)   I(max)
-2.5V     -2.88A     -1.21A     -25.75A
-1.1V     -296.4mA   -202.8mA   -979.3mA
-1V       -147.6mA   -138.6mA   -143.7mA
-900mV    -53.77mA   -80.42mA   -57.51mA
-800mV    -28mA      -35.97mA   -39.29mA
-700mV    -17.04mA   -14.79mA   -24.22mA
-600mV    -8.941mA   -7.498mA   -12.27mA
-500mV    -3.546mA   -3.592mA   -4.281mA
-400mV    -840.6uA   -1.303mA   -756.1uA
-300mV    -105.6uA   -288uA     -66.63uA
2.5V      116nA      886.3nA    35.24nA
[POWER_clamp]
|voltage   I(typ)   I(min)   I(max)
-2.5V     395.1mA    211mA      2.446A
-1.2V     41.69mA    25.58mA    245.1mA
-1.1V     24.27mA    17.3mA     108.6mA
-1V       10.69mA    10.14mA    16.33mA
-900mV    2.413mA    4.797mA    1.516mA
-800mV    211.8uA    1.609mA    382.9uA
-700mV    10.83uA    333.9uA    105.9uA
-600mV    637nA      37.63uA    26.9uA
0V        116nA      855.7nA    39.22nA
[Ramp]
| variable   typ   min   max
dV/dt_r   1.1047/0.9094ns   0.8188/2.3176ns   1.3391/0.2916ns
dV/dt_f   1.2798/0.9412ns   1.0853/2.2217ns   1.4359/0.4171ns
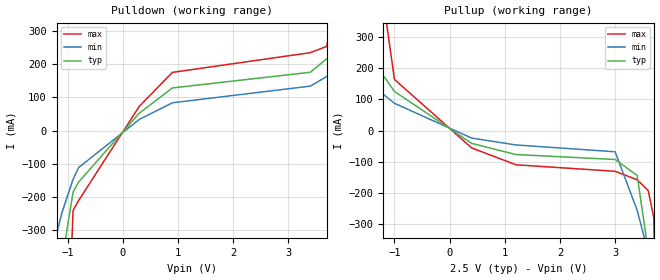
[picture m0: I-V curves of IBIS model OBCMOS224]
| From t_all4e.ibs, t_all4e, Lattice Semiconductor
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|   OBCMOS224
[Model]   OBCMOS224
Model_type   Output
Polarity   Non-Inverting
C_comp   2pF   2pF   2pF
[Temperature Range]   25.0000   125.0000   -40.0000
[Voltage Range]   2.5000V   2.3000V   2.7000V
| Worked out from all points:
|   slope of the pulldown table from 0 to 0.375 V, typ, clamps not added: 5.83 ohm
|   slope of the pullup table from 0 to 0.375 V, typ, clamps not added: 9.61 ohm
[Pulldown]
|voltage   I(typ)   I(min)   I(max)
-2.5V     -2.953A    -1.245A    -25.87A
-1.4V     -892.1mA   -445.3mA   -5.973A
-1.1V     -392.3mA   -247.7mA   -1.134A
-900mV    -186.4mA   -147.6mA   -241.7mA
-800mV    -156.1mA   -112.2mA   -212mA
300mV     52.54mA    33.62mA    73.23mA
900mV     128.9mA    83.99mA    176mA
3.4V      176.4mA    134.4mA    235.7mA
3.7V      217.6mA    163.7mA    254.8mA
3.9V      261mA      188.5mA    485.4mA
4.5V      422.4mA    281.3mA    1.466A
5V        578.9mA    371.2mA    2.341A
[Pullup]
|voltage   I(typ)   I(min)   I(max)
-2.5V     568.3mA    341.1mA    2.668A
-2V       409.8mA    248.2mA    1.78A
-1.2V     176.7mA    116.3mA    418.3mA
-1V       126mA      87.81mA    164.7mA
400mV     -41.34mA   -24.39mA   -56.12mA
1.2V      -77.41mA   -46.41mA   -110.3mA
3V        -93.31mA   -68.52mA   -131.4mA
3.4V      -145mA     -257.3mA   -158.7mA
3.6V      -388.3mA   -394mA     -193.5mA
3.7V      -556.4mA   -464.4mA   -280.5mA
3.8V      -732.4mA   -535.6mA   -1.117A
5V        -2.977A    -1.415A    -22.23A
[Ramp]
| variable   typ   min   max
dV/dt_r   1.2308/0.4102ns   0.9865/1.7637ns   1.4306/0.2004ns
dV/dt_f   1.3495/0.7833ns   1.1762/1.8076ns   1.4950/0.3422ns
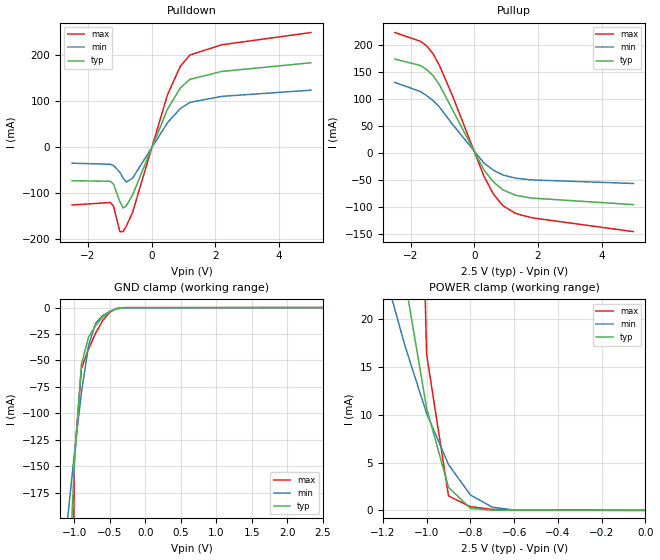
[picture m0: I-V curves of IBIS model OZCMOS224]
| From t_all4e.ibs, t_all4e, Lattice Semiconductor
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|   OZCMOS224
[Model]   OZCMOS224
Model_type   3-state
Polarity   Non-Inverting
Enable   Active-Low
C_comp   2pF   2pF   2pF
[Temperature Range]   25.0000   125.0000   -40.0000
[Voltage Range]   2.5000V   2.3000V   2.7000V
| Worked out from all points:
|   slope of the pulldown table from 0 to 0.375 V, typ, clamps not added: 5.83 ohm
|   slope of the pullup table from 0 to 0.375 V, typ, clamps not added: 9.61 ohm
|   GND clamp passes 1 mA (typ) near -0.41 V on its own axis
|   POWER clamp passes 1 mA (typ) near -0.84 V on its own axis
[Pulldown]
|voltage   I(typ)   I(min)   I(max)
-2.5V     -73.2mA    -35.01mA   -126.1mA
-1.3V     -74.56mA   -37.37mA   -120.7mA
-1.2V     -80.45mA   -39.89mA   -128.5mA
-1V       -118.8mA   -54.55mA   -184mA
-900mV    -132.6mA   -67.23mA   -184.2mA
-800mV    -128.1mA   -76.25mA   -172.7mA
-600mV    -104.4mA   -67.72mA   -142.5mA
500mV     82.91mA    53.35mA    114.6mA
900mV     128.9mA    83.99mA    176mA
1.2V      147.7mA    97.46mA    200.6mA
2.2V      164.9mA    110.6mA    223mA
5V        183.8mA    124.1mA    249.7mA
[Pullup]
|voltage   I(typ)   I(min)   I(max)
-2.5V     173.1mA    130mA      222.3mA
-1.7V     161.4mA    113.1mA    206.2mA
-1.5V     153.9mA    105.6mA    197.8mA
-1.3V     142.8mA    96.23mA    183.1mA
-1.1V     125.9mA    84.64mA    161.5mA
-700mV    80.9mA     53.32mA    107mA
300mV     -32.13mA   -19.29mA   -43.7mA
600mV     -54.31mA   -32.75mA   -77.13mA
900mV     -69.15mA   -41.49mA   -98.6mA
1.3V      -79.15mA   -47.47mA   -112.8mA
1.8V      -84.26mA   -50.6mA    -120.7mA
5V        -96.37mA   -57.2mA    -146.4mA
[GND_clamp]
|voltage   I(typ)   I(min)   I(max)
-2.5V     -2.88A     -1.21A     -25.75A
-1.1V     -296.4mA   -202.8mA   -979.3mA
-1V       -147.6mA   -138.6mA   -143.7mA
-900mV    -53.77mA   -80.42mA   -57.51mA
-800mV    -28mA      -35.97mA   -39.29mA
-700mV    -17.04mA   -14.79mA   -24.22mA
-600mV    -8.941mA   -7.498mA   -12.27mA
-500mV    -3.546mA   -3.592mA   -4.281mA
-400mV    -840.6uA   -1.303mA   -756.1uA
-300mV    -105.6uA   -288uA     -66.63uA
2.5V      116nA      886.3nA    35.24nA
[POWER_clamp]
|voltage   I(typ)   I(min)   I(max)
-2.5V     395.1mA    211mA      2.446A
-1.2V     41.69mA    25.58mA    245.1mA
-1.1V     24.27mA    17.3mA     108.6mA
-1V       10.69mA    10.14mA    16.33mA
-900mV    2.413mA    4.797mA    1.516mA
-800mV    211.8uA    1.609mA    382.9uA
-700mV    10.83uA    333.9uA    105.9uA
-600mV    637nA      37.63uA    26.9uA
0V        116nA      855.7nA    39.22nA
[Ramp]
| variable   typ   min   max
dV/dt_r   1.2308/0.4102ns   0.9865/1.7637ns   1.4306/0.2004ns
dV/dt_f   1.3495/0.7833ns   1.1762/1.8076ns   1.4950/0.3422ns
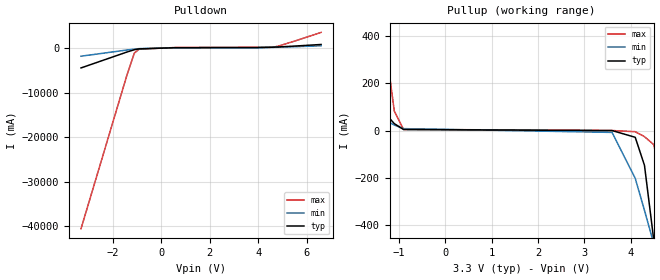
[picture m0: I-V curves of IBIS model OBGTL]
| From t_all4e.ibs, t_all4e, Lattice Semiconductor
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|   OBGTL
[Model]   OBGTL
Model_type   Output
Polarity   Non-Inverting
C_comp   2pF   2pF   2pF
[Temperature Range]   25.0000   125.0000   -40.0000
[Voltage Range]   3.3000V   3.0000V   3.6000V
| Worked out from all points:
|   slope of the pulldown table from 0 to 0.495 V, typ, clamps not added: 7.1 ohm
[Pulldown]
|voltage   I(typ)   I(min)   I(max)
-3.3V     -4.47A     -1.834A    -40.58A
-1.4V     -886.8mA   -441.4mA   -5.965A
-1.1V     -380.4mA   -240.9mA   -1.121A
-900mV    -186.4mA   -138.8mA   -247.4mA
600mV     76.57mA    43.51mA    114.8mA
3.9V      105.4mA    69.14mA    157.4mA
4.6V      180.2mA    144.1mA    175.9mA
4.8V      230.4mA    173.5mA    379mA
4.9V      257.2mA    189.3mA    531.5mA
5.5V      436.8mA    293.7mA    1.547A
6.2V      665.4mA    427.9mA    2.791A
6.6V      799.6mA    508mA      3.512A
[Pullup]
|voltage   I(typ)   I(min)   I(max)
-3.3V     671.4mA    375.4mA    3.864A
-2.6V     443.5mA    240.2mA    2.608A
-1.4V     95.04mA    54.58mA    527.5mA
-1.1V     29.44mA    23.32mA    82.92mA
-900mV    4.209mA    7.979mA    4.915mA
3.6V      -117.4uA   -7.964mA   -10.28nA
4.1V      -28.73mA   -203.1mA   -4.991mA
4.3V      -148.1mA   -339.4mA   -26.09mA
4.5V      -464.6mA   -480.7mA   -59.99mA
4.6V      -640.3mA   -552.3mA   -145.8mA
4.7V      -820.2mA   -624.4mA   -980.9mA
6.6V      -4.405A    -2.027A    -34.94A
[Ramp]
| variable   typ   min   max
dV/dt_r   1.7585/2.2155ns   1.3772/3.0328ns   2.0184/1.7231ns
dV/dt_f   1.7585/1.5939ns   1.3772/3.7421ns   2.0184/0.7250ns
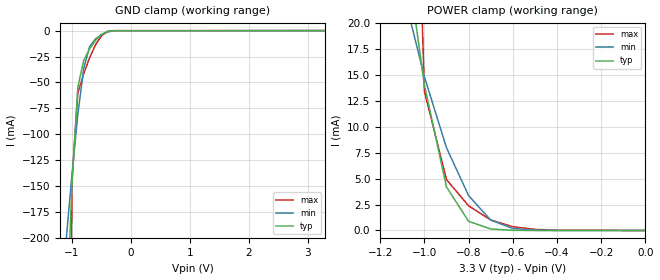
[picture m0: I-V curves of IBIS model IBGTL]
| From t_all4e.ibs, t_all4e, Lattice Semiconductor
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|   IBGTL
[Model]   IBGTL
Model_type   Input
Polarity   Non-Inverting
C_comp   2pF   2pF   2pF
Vinl = 0.5
Vinh = 2.64
[Temperature Range]   25.0000   125.0000   -40.0000
[Voltage Range]   3.3000V   3.0000V   3.6000V
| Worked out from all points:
|   GND clamp passes 1 mA (typ) near -0.40 V on its own axis
|   POWER clamp passes 1 mA (typ) near -0.80 V on its own axis
[GND_clamp]
|voltage   I(typ)   I(min)   I(max)
-3.3V     -4.405A    -1.803A    -40.47A
-1.1V     -296.8mA   -203.1mA   -980.9mA
-1V       -148.1mA   -138.9mA   -145.8mA
-900mV    -54.45mA   -80.8mA    -59.99mA
-800mV    -28.73mA   -36.47mA   -41.54mA
-700mV    -17.64mA   -15.37mA   -26.09mA
-600mV    -9.37mA    -7.964mA   -13.62mA
-500mV    -3.781mA   -3.889mA   -4.991mA
-400mV    -916.5uA   -1.444mA   -942uA
-300mV    -117.4uA   -327.5uA   -87.29uA
3.3V      153.1nA    1.254uA    59.37nA
[POWER_clamp]
|voltage   I(typ)   I(min)   I(max)
-3.3V     682mA      379.6mA    3.878A
-1.1V     29.47mA    23.43mA    82.94mA
-1V       14.04mA    14.85mA    13.44mA
-900mV    4.209mA    7.985mA    4.915mA
-800mV    886uA      3.367mA    2.382mA
-700mV    145.7uA    1.006mA    1.019mA
-600mV    12.73uA    189.2uA    364.5uA
-500mV    823.4nA    21.34uA    104.9uA
-400mV    187.8nA    2.623uA    24.35uA
0V        153.1nA    1.128uA    110.4nA
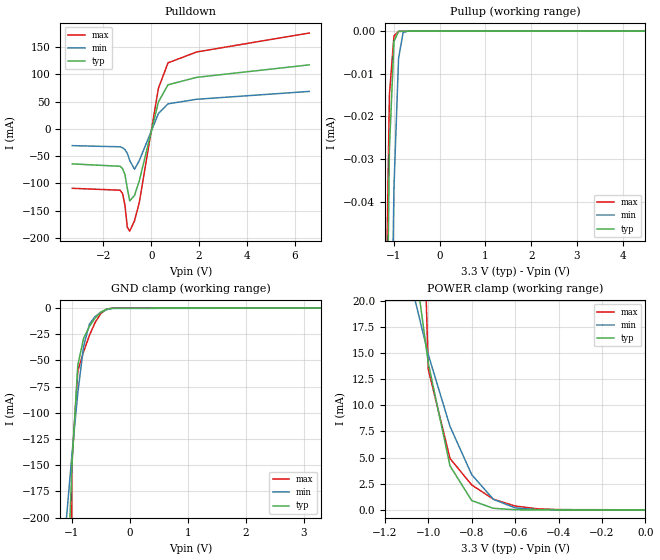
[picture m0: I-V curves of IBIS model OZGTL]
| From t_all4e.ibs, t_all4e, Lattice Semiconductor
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|   OZGTL
[Model]   OZGTL
Model_type   3-state
Polarity   Non-Inverting
Enable   Active-Low
C_comp   2pF   2pF   2pF
[Temperature Range]   25.0000   125.0000   -40.0000
[Voltage Range]   3.3000V   3.0000V   3.6000V
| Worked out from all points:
|   slope of the pulldown table from 0 to 0.495 V, typ, clamps not added: 7.1 ohm
|   GND clamp passes 1 mA (typ) near -0.40 V on its own axis
|   POWER clamp passes 1 mA (typ) near -0.80 V on its own axis
[Pulldown]
|voltage   I(typ)   I(min)   I(max)
-3.3V     -64.1mA    -30.61mA   -108.9mA
-1.3V     -68.52mA   -32.76mA   -112.4mA
-1.2V     -72.7mA    -34.52mA   -118.4mA
-1.1V     -83.57mA   -37.84mA   -139.9mA
-1V       -109.4mA   -44.73mA   -180.4mA
-900mV    -132mA     -57.97mA   -187.5mA
-700mV    -121.9mA   -73.97mA   -168.4mA
-500mV    -95.25mA   -58.03mA   -134.9mA
300mV     49.66mA    28.29mA    74.78mA
700mV     81.04mA    46.09mA    121.3mA
1.9V      94.7mA     54.47mA    141.3mA
6.6V      117.6mA    68.87mA    176mA
[Pullup]
|voltage   I(typ)   I(min)   I(max)
-3.3V     -10.68mA   -4.156mA   -14.81mA
-1.2V     -114.4uA   -214.6uA   -83uA
-1.1V     -27.5uA    -106.1uA   -14.8uA
-1V       -2.4uA     -36.4uA    -1.1uA
-900mV    -30nA      -6.33uA    -50nA
-800mV    0A         -300nA     -10nA
-700mV    0A         0A         0A
6.6V      0A         0A         0A
[GND_clamp]
|voltage   I(typ)   I(min)   I(max)
-3.3V     -4.405A    -1.803A    -40.47A
-1.1V     -296.8mA   -203.1mA   -980.9mA
-1V       -148.1mA   -138.9mA   -145.8mA
-900mV    -54.45mA   -80.8mA    -59.99mA
-800mV    -28.73mA   -36.47mA   -41.54mA
-700mV    -17.64mA   -15.37mA   -26.09mA
-600mV    -9.37mA    -7.964mA   -13.62mA
-500mV    -3.781mA   -3.889mA   -4.991mA
-400mV    -916.5uA   -1.444mA   -942uA
-300mV    -117.4uA   -327.5uA   -87.29uA
3.3V      153.1nA    1.254uA    59.37nA
[POWER_clamp]
|voltage   I(typ)   I(min)   I(max)
-3.3V     682mA      379.6mA    3.878A
-1.1V     29.47mA    23.43mA    82.94mA
-1V       14.04mA    14.85mA    13.44mA
-900mV    4.209mA    7.985mA    4.915mA
-800mV    886uA      3.367mA    2.382mA
-700mV    145.7uA    1.006mA    1.019mA
-600mV    12.73uA    189.2uA    364.5uA
-500mV    823.4nA    21.34uA    104.9uA
-400mV    187.8nA    2.623uA    24.35uA
0V        153.1nA    1.128uA    110.4nA
[Ramp]
| variable   typ   min   max
dV/dt_r   1.7585/2.2155ns   1.3772/3.0328ns   2.0184/1.7231ns
dV/dt_f   1.7585/1.5939ns   1.3772/3.7421ns   2.0184/0.7250ns
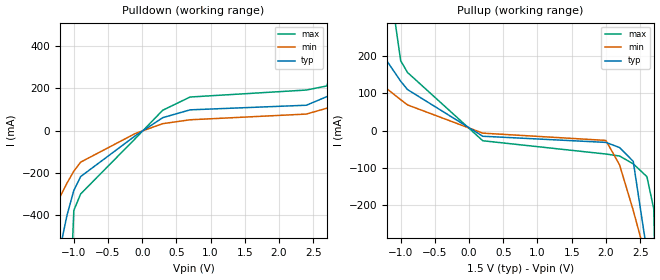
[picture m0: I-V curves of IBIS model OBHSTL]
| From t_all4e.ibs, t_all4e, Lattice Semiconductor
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|   OBHSTL
[Model]   OBHSTL
Model_type   Output
Polarity   Non-Inverting
C_comp   2pF   2pF   2pF
[Temperature Range]   25.0000   125.0000   -40.0000
[Voltage Range]   1.5000V   1.3000V   1.7000V
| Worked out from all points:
|   slope of the pulldown table from 0 to 0.225 V, typ, clamps not added: 4.71 ohm
|   slope of the pullup table from 0 to 0.225 V, typ, clamps not added: 13.4 ohm
[Pulldown]
|voltage   I(typ)   I(min)   I(max)
-1.5V     -1.083A    -517.5mA   -7.754A
-1.2V     -553.7mA   -311.1mA   -2.621A
-1.1V     -399.1mA   -247.7mA   -1.16A
-1V       -282.1mA   -191.4mA   -376mA
-900mV    -216.8mA   -148.8mA   -298.6mA
-100mV    -24.46mA   -13.74mA   -37.54mA
300mV     60.6mA     32.41mA    95.58mA
700mV     97.41mA    50.59mA    157.8mA
2.4V      119.1mA    77.56mA    190.7mA
2.7V      159.6mA    105.1mA    209.9mA
2.9V      202.1mA    127.6mA    439.9mA
3V        224.9mA    140.1mA    591.6mA
[Pullup]
|voltage   I(typ)   I(min)   I(max)
-1.5V     270.5mA    156.7mA    941.5mA
-1.2V     186.7mA    112.2mA    445.2mA
-1V       132.6mA    82.95mA    187.6mA
-900mV    110.2mA    68.95mA    156.2mA
200mV     -15.42mA   -7.04mA    -27.52mA
2V        -31.93mA   -26.62mA   -63.24mA
2.2V      -45.8mA    -92.39mA   -68.6mA
2.4V      -82.9mA    -214.9mA   -89.67mA
2.6V      -325.9mA   -351.4mA   -124.1mA
2.7V      -493.8mA   -421.7mA   -210.8mA
2.8V      -669.7mA   -492.8mA   -1.047A
3V        -1.033A    -636.6mA   -4.197A
[Ramp]
| variable   typ   min   max
dV/dt_r   0.6186/0.2680ns   0.3218/0.5220ns   0.8877/0.1146ns
dV/dt_f   0.8289/0.7045ns   0.6711/2.1692ns   0.9647/0.2104ns
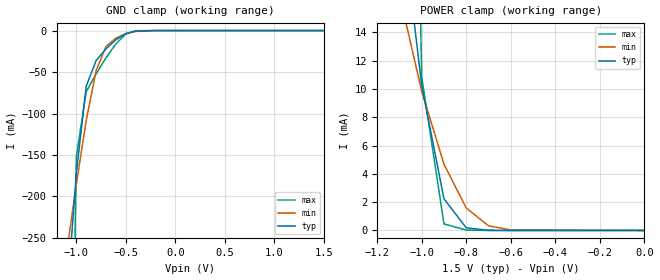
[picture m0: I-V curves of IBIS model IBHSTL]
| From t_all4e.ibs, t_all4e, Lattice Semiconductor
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|   IBHSTL
[Model]   IBHSTL
Model_type   Input
Polarity   Non-Inverting
C_comp   2pF   2pF   2pF
Vinl = 0.65
Vinh = 0.85
[Temperature Range]   25.0000   125.0000   -40.0000
[Voltage Range]   1.5000V   1.3000V   1.7000V
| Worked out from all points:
|   GND clamp passes 1 mA (typ) near -0.42 V on its own axis
|   POWER clamp passes 1 mA (typ) near -0.84 V on its own axis
[GND_clamp]
|voltage   I(typ)   I(min)   I(max)
-1.5V     -1.085A    -636mA     -6.966A
-1.1V     -332.8mA   -270.2mA   -909.6mA
-1V       -172.5mA   -185.4mA   -152.3mA
-900mV    -67.04mA   -108.1mA   -73.7mA
-800mV    -36.08mA   -48.19mA   -52.12mA
-700mV    -22.02mA   -19.07mA   -32.82mA
-600mV    -11.05mA   -9.09mA    -15.96mA
-500mV    -3.623mA   -3.821mA   -4.099mA
-400mV    -457.6uA   -1.029mA   -198.9uA
-200mV    -330.5nA   -7.853uA   -10.98nA
1.5V      492.2pA    48.65nA    173pA
[POWER_clamp]
|voltage   I(typ)   I(min)   I(max)
-1.5V     104.2mA    53.66mA    703.5mA
-1.1V     23.53mA    16.7mA     94.95mA
-1V       10.26mA    9.843mA    10.87mA
-900mV    2.244mA    4.687mA    462.3uA
-800mV    189.8uA    1.592mA    28.87uA
-700mV    9.998uA    330.4uA    1.673uA
-600mV    482.8nA    38.98uA    69.83nA
0V        492.2pA    44.99nA    217.3pA
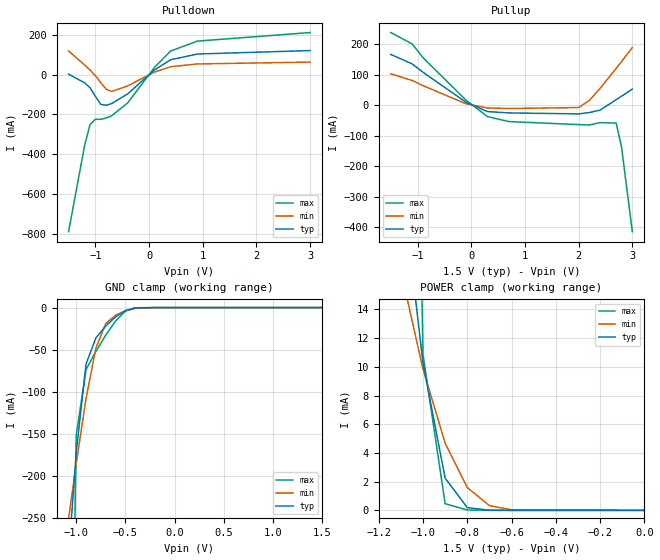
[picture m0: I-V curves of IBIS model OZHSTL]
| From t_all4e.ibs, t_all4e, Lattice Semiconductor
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|   OZHSTL
[Model]   OZHSTL
Model_type   3-state
Polarity   Non-Inverting
Enable   Active-Low
C_comp   2pF   2pF   2pF
[Temperature Range]   25.0000   125.0000   -40.0000
[Voltage Range]   1.5000V   1.3000V   1.7000V
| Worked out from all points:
|   slope of the pulldown table from 0 to 0.225 V, typ, clamps not added: 4.71 ohm
|   slope of the pullup table from 0 to 0.225 V, typ, clamps not added: 13.4 ohm
|   GND clamp passes 1 mA (typ) near -0.42 V on its own axis
|   POWER clamp passes 1 mA (typ) near -0.84 V on its own axis
[Pulldown]
|voltage   I(typ)   I(min)   I(max)
-1.5V     2.15mA     118.5mA    -788.3mA
-1.2V     -41.71mA   47.78mA    -353.4mA
-1.1V     -66.32mA   22.52mA    -250.6mA
-1V       -109.6mA   -5.992mA   -223.7mA
-900mV    -149.7mA   -40.67mA   -224.9mA
-800mV    -154.1mA   -73.39mA   -217.5mA
-700mV    -145.9mA   -84.64mA   -207.1mA
-400mV    -96.69mA   -56.96mA   -142.4mA
100mV     23.16mA    12.61mA    36.25mA
400mV     74.4mA     39.41mA    118.1mA
900mV     103.2mA    53.44mA    168.1mA
3V        120.7mA    62.89mA    211.1mA
[Pullup]
|voltage   I(typ)   I(min)   I(max)
-1.5V     166.3mA    103mA      238mA
-1.1V     135.2mA    80.94mA    200.5mA
-900mV    108mA      64.27mA    155.8mA
-100mV    9.969mA    4.959mA    16.81mA
300mV     -20.71mA   -8.973mA   -36.98mA
700mV     -25.06mA   -10.6mA    -53.42mA
2V        -28.3mA    -7.549mA   -63.24mA
2.2V      -23.79mA   15.76mA    -64.5mA
2.4V      -15.86mA   55.29mA    -56.85mA
2.7V      18.19mA    120.8mA    -58.49mA
2.8V      29.59mA    143.3mA    -137.3mA
3V        52.79mA    188.7mA    -413.7mA
[GND_clamp]
|voltage   I(typ)   I(min)   I(max)
-1.5V     -1.085A    -636mA     -6.966A
-1.1V     -332.8mA   -270.2mA   -909.6mA
-1V       -172.5mA   -185.4mA   -152.3mA
-900mV    -67.04mA   -108.1mA   -73.7mA
-800mV    -36.08mA   -48.19mA   -52.12mA
-700mV    -22.02mA   -19.07mA   -32.82mA
-600mV    -11.05mA   -9.09mA    -15.96mA
-500mV    -3.623mA   -3.821mA   -4.099mA
-400mV    -457.6uA   -1.029mA   -198.9uA
-200mV    -330.5nA   -7.853uA   -10.98nA
1.5V      492.2pA    48.65nA    173pA
[POWER_clamp]
|voltage   I(typ)   I(min)   I(max)
-1.5V     104.2mA    53.66mA    703.5mA
-1.1V     23.53mA    16.7mA     94.95mA
-1V       10.26mA    9.843mA    10.87mA
-900mV    2.244mA    4.687mA    462.3uA
-800mV    189.8uA    1.592mA    28.87uA
-700mV    9.998uA    330.4uA    1.673uA
-600mV    482.8nA    38.98uA    69.83nA
0V        492.2pA    44.99nA    217.3pA
[Ramp]
| variable   typ   min   max
dV/dt_r   0.6186/0.2680ns   0.3218/0.5220ns   0.8877/0.1146ns
dV/dt_f   0.8289/0.7045ns   0.6711/2.1692ns   0.9647/0.2104ns
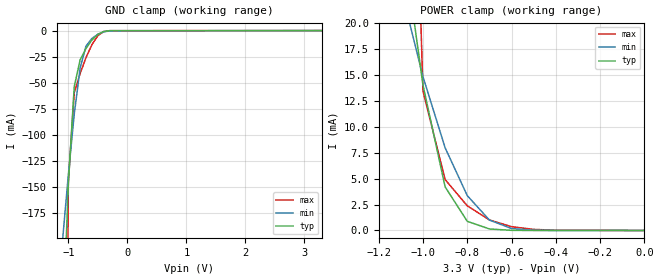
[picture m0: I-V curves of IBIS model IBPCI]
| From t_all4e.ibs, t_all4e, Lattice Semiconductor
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|   IBPCI
[Model]   IBPCI
Model_type   Input
Polarity   Non-Inverting
C_comp   2pF   2pF   2pF
Vinl = 1.65
Vinh = 0.99
[Temperature Range]   25.0000   125.0000   -40.0000
[Voltage Range]   3.3000V   3.0000V   3.6000V
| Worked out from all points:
|   GND clamp passes 1 mA (typ) near -0.41 V on its own axis
|   POWER clamp passes 1 mA (typ) near -0.80 V on its own axis
[GND_clamp]
|voltage   I(typ)   I(min)   I(max)
-3.3V     -4.405A    -1.803A    -40.47A
-1.1V     -296.5mA   -202.8mA   -980.7mA
-1V       -147.7mA   -138.6mA   -145.5mA
-900mV    -53.87mA   -80.42mA   -59.66mA
-800mV    -28.11mA   -35.98mA   -41.24mA
-700mV    -17.13mA   -14.8mA    -25.84mA
-600mV    -9.006mA   -7.505mA   -13.44mA
-500mV    -3.582mA   -3.596mA   -4.891mA
-400mV    -851.9uA   -1.305mA   -914.6uA
-300mV    -107.3uA   -288.6uA   -84.13uA
3.3V      138.7nA    1.084uA    56.89nA
[POWER_clamp]
|voltage   I(typ)   I(min)   I(max)
-3.3V     682mA      379.6mA    3.878A
-1.1V     29.47mA    23.43mA    82.94mA
-1V       14.04mA    14.85mA    13.44mA
-900mV    4.209mA    7.985mA    4.915mA
-800mV    886uA      3.367mA    2.382mA
-700mV    145.7uA    1.006mA    1.019mA
-600mV    12.72uA    189uA      364.5uA
-500mV    807.6nA    21.16uA    104.9uA
-400mV    172.2nA    2.45uA     24.34uA
0V        138.7nA    967.1nA    107.9nA
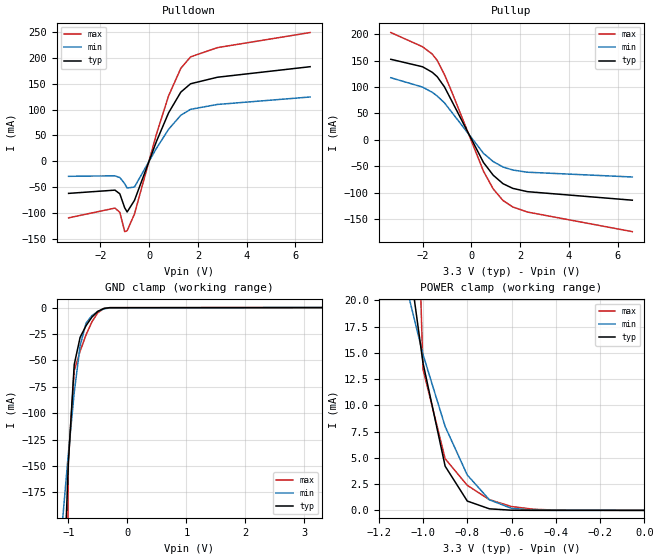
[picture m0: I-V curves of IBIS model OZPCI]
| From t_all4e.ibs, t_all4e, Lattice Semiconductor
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|   OZPCI
[Model]   OZPCI
Model_type   3-state
Polarity   Non-Inverting
Enable   Active-Low
C_comp   2pF   2pF   2pF
[Temperature Range]   25.0000   125.0000   -40.0000
[Voltage Range]   3.3000V   3.0000V   3.6000V
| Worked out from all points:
|   slope of the pulldown table from 0 to 0.495 V, typ, clamps not added: 8.06 ohm
|   slope of the pullup table from 0 to 0.495 V, typ, clamps not added: 11.7 ohm
|   GND clamp passes 1 mA (typ) near -0.41 V on its own axis
|   POWER clamp passes 1 mA (typ) near -0.80 V on its own axis
[Pulldown]
|voltage   I(typ)   I(min)   I(max)
-3.3V     -61.72mA   -28.8mA    -108.9mA
-1.4V     -55.43mA   -27.84mA   -90.08mA
-1.2V     -62.57mA   -31.19mA   -98.26mA
-1V       -89.59mA   -43.02mA   -135.5mA
-900mV    -97.56mA   -51.33mA   -133.7mA
-600mV    -75.24mA   -49.45mA   -101.5mA
300mV     38.39mA    25.14mA    52.57mA
800mV     93.76mA    61.99mA    126.6mA
1.3V      133.6mA    88.99mA    179.5mA
1.7V      149.7mA    100.4mA    201.6mA
2.8V      162.3mA    109.8mA    219.4mA
6.6V      182.6mA    124.2mA    248.5mA
[Pullup]
|voltage   I(typ)   I(min)   I(max)
-3.3V     152.5mA    117.6mA    203.1mA
-2V       138.4mA    99.96mA    176.3mA
-1.6V     127.9mA    90.05mA    162.3mA
-1.4V     119.7mA    83.23mA    150.6mA
-1.1V     100.3mA    70.12mA    123.6mA
-800mV    73.67mA    52.36mA    90.9mA
500mV     -42.74mA   -25.36mA   -59.21mA
900mV     -66.84mA   -41.03mA   -92.77mA
1.3V      -82.82mA   -51.19mA   -114.6mA
1.7V      -91.62mA   -56.95mA   -126.8mA
2.3V      -97.87mA   -61.1mA    -136.4mA
6.6V      -114mA     -70.13mA   -173.5mA
[GND_clamp]
|voltage   I(typ)   I(min)   I(max)
-3.3V     -4.405A    -1.803A    -40.47A
-1.1V     -296.5mA   -202.8mA   -980.7mA
-1V       -147.7mA   -138.6mA   -145.5mA
-900mV    -53.87mA   -80.42mA   -59.66mA
-800mV    -28.11mA   -35.98mA   -41.24mA
-700mV    -17.13mA   -14.8mA    -25.84mA
-600mV    -9.006mA   -7.505mA   -13.44mA
-500mV    -3.582mA   -3.596mA   -4.891mA
-400mV    -851.9uA   -1.305mA   -914.6uA
-300mV    -107.3uA   -288.6uA   -84.13uA
3.3V      138.7nA    1.084uA    56.89nA
[POWER_clamp]
|voltage   I(typ)   I(min)   I(max)
-3.3V     682mA      379.6mA    3.878A
-1.1V     29.47mA    23.43mA    82.94mA
-1V       14.04mA    14.85mA    13.44mA
-900mV    4.209mA    7.985mA    4.915mA
-800mV    886uA      3.367mA    2.382mA
-700mV    145.7uA    1.006mA    1.019mA
-600mV    12.72uA    189uA      364.5uA
-500mV    807.6nA    21.16uA    104.9uA
-400mV    172.2nA    2.45uA     24.34uA
0V        138.7nA    967.1nA    107.9nA
[Ramp]
| variable   typ   min   max
dV/dt_r   1.5752/0.6917ns   1.2340/1.5561ns   1.8657/0.3425ns
dV/dt_f   1.7097/1.0452ns   1.4377/2.2108ns   1.9424/0.6107ns
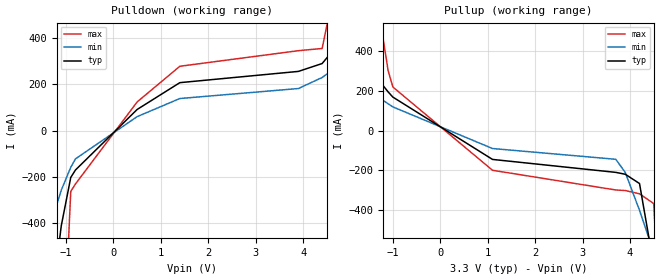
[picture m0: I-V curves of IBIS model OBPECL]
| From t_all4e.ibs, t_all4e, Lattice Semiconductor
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|   OBPECL
[Model]   OBPECL
Model_type   Output
Polarity   Non-Inverting
C_comp   2pF   2pF   2pF
[Temperature Range]   25.0000   125.0000   -40.0000
[Voltage Range]   3.3000V   3.0000V   3.6000V
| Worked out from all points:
|   slope of the pulldown table from 0 to 0.495 V, typ, clamps not added: 5.38 ohm
|   slope of the pullup table from 0 to 0.495 V, typ, clamps not added: 6.01 ohm
[Pulldown]
|voltage   I(typ)   I(min)   I(max)
-3.3V     -4.5A      -1.848A    -40.63A
-1.4V     -905.1mA   -452.3mA   -5.993A
-1.1V     -410.9mA   -257.3mA   -1.16A
-900mV    -202.3mA   -158.6mA   -262.6mA
-800mV    -170.1mA   -122.2mA   -230.3mA
500mV     90.86mA    59.92mA    123.3mA
1.4V      206.4mA    138mA      277.1mA
3.9V      255mA      181.1mA    344.3mA
4.4V      288.9mA    228.6mA    353.8mA
5.1V      460mA      332.3mA    1.049A
5.8V      678.9mA    464.8mA    2.257A
6.6V      955.4mA    633mA      3.701A
[Pullup]
|voltage   I(typ)   I(min)   I(max)
-3.3V     927.1mA    566.9mA    4.204A
-2.4V     605mA      373mA      2.543A
-1.3V     253.8mA    166.6mA    606.4mA
-1.1V     194.3mA    134.5mA    300.9mA
-1V       168.2mA    118.9mA    218.9mA
1.1V      -145.4mA   -90.53mA   -200mA
3.7V      -210.6mA   -144.8mA   -299.2mA
3.9V      -220.1mA   -211.1mA   -302.1mA
4.2V      -266.8mA   -401.8mA   -318.4mA
4.5V      -679.1mA   -613.2mA   -367.7mA
4.7V      -1.036A    -757.5mA   -1.292A
6.6V      -4.632A    -2.166A    -35.28A
[Ramp]
| variable   typ   min   max
dV/dt_r   1.7270/0.2838ns   1.4530/0.5873ns   1.9713/0.1396ns
dV/dt_f   1.7624/0.5631ns   1.5175/1.2649ns   1.9807/0.2591ns
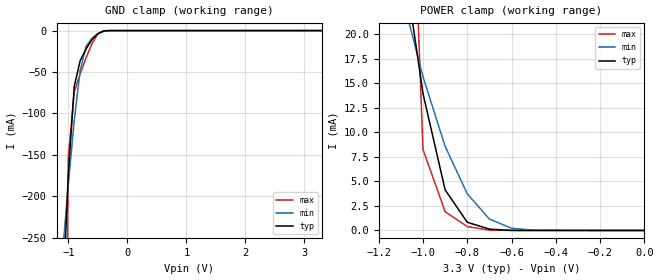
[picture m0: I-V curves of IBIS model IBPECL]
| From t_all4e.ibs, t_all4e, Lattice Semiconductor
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|   IBPECL
[Model]   IBPECL
Model_type   Input
Polarity   Non-Inverting
C_comp   2pF   2pF   2pF
Vinl = 1.33
Vinh = 2.58
[Temperature Range]   25.0000   125.0000   -40.0000
[Voltage Range]   3.3000V   3.0000V   3.6000V
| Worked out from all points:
|   GND clamp passes 1 mA (typ) near -0.42 V on its own axis
|   POWER clamp passes 1 mA (typ) near -0.80 V on its own axis
[GND_clamp]
|voltage   I(typ)   I(min)   I(max)
-3.3V     -4.707A    -2.378A    -36.99A
-1.1V     -333.1mA   -270.3mA   -910mA
-1V       -172.8mA   -185.5mA   -152.8mA
-900mV    -67.41mA   -108.3mA   -74.18mA
-800mV    -36.38mA   -48.37mA   -52.47mA
-700mV    -22.11mA   -19.21mA   -32.92mA
-600mV    -11.06mA   -9.133mA   -15.98mA
-500mV    -3.625mA   -3.829mA   -4.1mA
-400mV    -457.6uA   -1.03mA    -198.9uA
-300mV    -16.03uA   -125.2uA   -1.726uA
3.3V      1.143nA    224.6nA    425.9pA
[POWER_clamp]
|voltage   I(typ)   I(min)   I(max)
-3.3V     686.3mA    389.5mA    3.87A
-1.1V     29.43mA    24.48mA    68.99mA
-1V       13.97mA    15.69mA    8.268mA
-900mV    4.143mA    8.587mA    1.92mA
-800mV    838uA      3.741mA    397.7uA
-700mV    134.6uA    1.163mA    35.06uA
-600mV    12.61uA    224.6uA    1.74uA
-500mV    776.9nA    27.06uA    60.83nA
0V        1.143nA    79.5nA     493.3pA
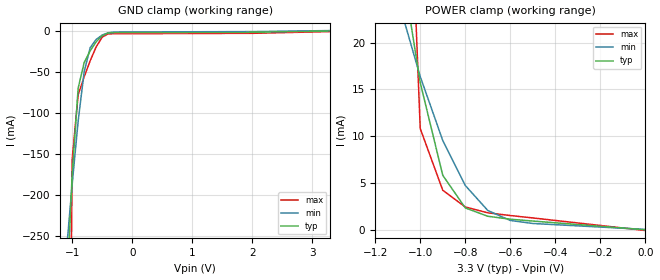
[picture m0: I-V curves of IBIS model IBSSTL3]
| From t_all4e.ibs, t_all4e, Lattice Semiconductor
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|   IBSSTL3
[Model]   IBSSTL3
Model_type   Input
Polarity   Non-Inverting
C_comp   2pF   2pF   2pF
Vinl = 1.3
Vinh = 1.7
[Temperature Range]   25.0000   125.0000   -40.0000
[Voltage Range]   3.3000V   3.0000V   3.6000V
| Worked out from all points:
|   POWER clamp passes 1 mA (typ) near -0.53 V on its own axis
[GND_clamp]
|voltage   I(typ)   I(min)   I(max)
-3.3V     -4.71A     -2.38A     -36.99A
-1.1V     -335.3mA   -271.6mA   -913.5mA
-1V       -175mA     -186.8mA   -156.3mA
-900mV    -69.59mA   -109.6mA   -77.67mA
-800mV    -38.55mA   -49.61mA   -55.95mA
-700mV    -24.28mA   -20.45mA   -36.4mA
-600mV    -13.22mA   -10.36mA   -19.45mA
-500mV    -5.781mA   -5.057mA   -7.561mA
-400mV    -2.608mA   -2.253mA   -3.653mA
-300mV    -2.161mA   -1.345mA   -3.448mA
2V        -1.707mA   -858.3uA   -2.953mA
3.3V      1.15nA     395.3uA    -838uA
[POWER_clamp]
|voltage   I(typ)   I(min)   I(max)
-3.3V     686.8mA    394.6mA    3.866A
-1.1V     30.94mA    24.73mA    71.6mA
-1V       15.73mA    16.38mA    10.82mA
-900mV    5.825mA    9.543mA    4.225mA
-800mV    2.337mA    4.735mA    2.438mA
-700mV    1.442mA    2.06mA     1.81mA
-600mV    1.129mA    994.9uA    1.522mA
-500mV    930.8uA    670.1uA    1.264mA
0V        1.15nA     35.02uA    -79.12uA
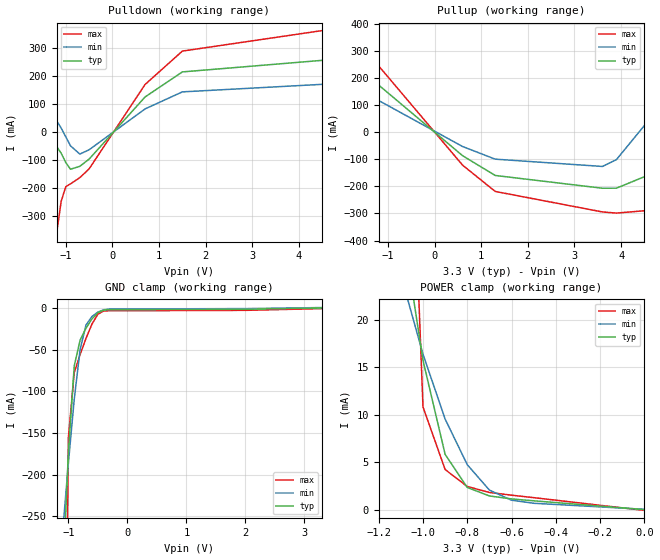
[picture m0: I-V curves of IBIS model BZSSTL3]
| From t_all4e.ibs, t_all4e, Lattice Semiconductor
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|   BZSSTL3
[Model]   BZSSTL3
Model_type   I/O
Polarity   Non-Inverting
Enable   Active-Low
C_comp   2pF   2pF   2pF
Vinl = 1.3
Vinh = 1.7
[Temperature Range]   25.0000   125.0000   -40.0000
[Voltage Range]   3.3000V   3.0000V   3.6000V
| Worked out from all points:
|   slope of the pulldown table from 0 to 0.495 V, typ, clamps not added: 5.38 ohm
|   slope of the pullup table from 0 to 0.495 V, typ, clamps not added: 6.07 ohm
|   POWER clamp passes 1 mA (typ) near -0.53 V on its own axis
[Pulldown]
|voltage   I(typ)   I(min)   I(max)
-3.3V     209.8mA    532mA      -3.645A
-2.9V     163mA      438.8mA    -3.005A
-1.3V     -26.21mA   67.49mA    -482.2mA
-1.1V     -75.61mA   14.24mA    -246.7mA
-1V       -109.2mA   -17.56mA   -194.9mA
-900mV    -132.7mA   -49.08mA   -184.9mA
-700mV    -122.3mA   -78.62mA   -162.7mA
-500mV    -96.38mA   -63.08mA   -131.3mA
700mV     125.5mA    82.84mA    170.1mA
1.5V      215mA      143.7mA    289.4mA
4.8V      260.5mA    173.3mA    370mA
6.6V      268.6mA    174.5mA    378.8mA
[Pullup]
|voltage   I(typ)   I(min)   I(max)
-3.3V     240.3mA    172.3mA    337.7mA
-1.2V     173.3mA    116.3mA    243.7mA
600mV     -87.11mA   -53.26mA   -122mA
1.3V      -159.9mA   -99.81mA   -218.8mA
3.6V      -207mA     -126.7mA   -294.4mA
3.9V      -206.8mA   -101.6mA   -298.6mA
4.5V      -164.6mA   24.22mA    -290mA
4.6V      -153.6mA   46.61mA    -298.9mA
4.7V      -142.5mA   69.14mA    -378.6mA
4.8V      -131.3mA   91.79mA    -510.8mA
6.1V      19.06mA    391.6mA    -2.541A
6.6V      77.8mA     508.1mA    -3.339A
[GND_clamp]
|voltage   I(typ)   I(min)   I(max)
-3.3V     -4.71A     -2.38A     -36.99A
-1.1V     -335.3mA   -271.6mA   -913.5mA
-1V       -175mA     -186.8mA   -156.3mA
-900mV    -69.59mA   -109.6mA   -77.67mA
-800mV    -38.55mA   -49.61mA   -55.95mA
-700mV    -24.28mA   -20.45mA   -36.4mA
-600mV    -13.22mA   -10.36mA   -19.45mA
-500mV    -5.781mA   -5.057mA   -7.561mA
-400mV    -2.608mA   -2.253mA   -3.653mA
-300mV    -2.161mA   -1.345mA   -3.448mA
2V        -1.707mA   -858.3uA   -2.953mA
3.3V      1.15nA     395.3uA    -838uA
[POWER_clamp]
|voltage   I(typ)   I(min)   I(max)
-3.3V     686.8mA    394.6mA    3.866A
-1.1V     30.94mA    24.73mA    71.6mA
-1V       15.73mA    16.38mA    10.82mA
-900mV    5.825mA    9.543mA    4.225mA
-800mV    2.337mA    4.735mA    2.438mA
-700mV    1.442mA    2.06mA     1.81mA
-600mV    1.129mA    994.9uA    1.522mA
-500mV    930.8uA    670.1uA    1.264mA
0V        1.15nA     35.02uA    -79.12uA
[Ramp]
| variable   typ   min   max
dV/dt_r   1.7270/0.2838ns   1.4530/0.5872ns   1.9713/0.1396ns
dV/dt_f   1.7625/0.5630ns   1.5176/1.2649ns   1.9807/0.2594ns
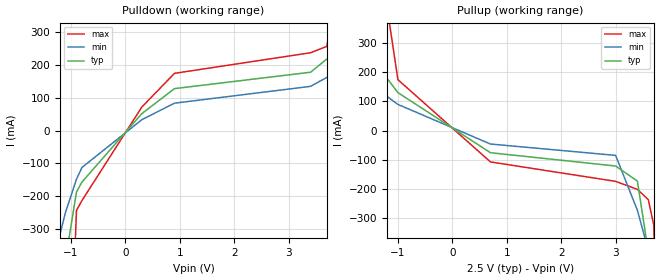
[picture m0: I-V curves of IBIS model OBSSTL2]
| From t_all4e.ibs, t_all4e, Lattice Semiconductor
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|   OBSSTL2
[Model]   OBSSTL2
Model_type   Output
Polarity   Non-Inverting
C_comp   2pF   2pF   2pF
[Temperature Range]   25.0000   125.0000   -40.0000
[Voltage Range]   2.5000V   2.3000V   2.7000V
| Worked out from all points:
|   slope of the pulldown table from 0 to 0.375 V, typ, clamps not added: 5.83 ohm
|   slope of the pullup table from 0 to 0.375 V, typ, clamps not added: 7.37 ohm
[Pulldown]
|voltage   I(typ)   I(min)   I(max)
-2.5V     -2.954A    -1.246A    -25.88A
-1.4V     -893.2mA   -446mA     -5.974A
-1.1V     -393.4mA   -248.3mA   -1.136A
-900mV    -187.5mA   -148.3mA   -243.5mA
-800mV    -157.2mA   -112.8mA   -213.7mA
300mV     51.45mA    33mA       71.52mA
900mV     127.8mA    83.4mA     174.4mA
3.4V      177.8mA    134.7mA    237.2mA
3.7V      218.2mA    162.1mA    256.7mA
3.9V      259.4mA    185.7mA    486.3mA
4.5V      414.3mA    277.5mA    1.457A
5V        570.9mA    370.2mA    2.328A
[Pullup]
|voltage   I(typ)   I(min)   I(max)
-2.5V     568.8mA    344.1mA    2.666A
-2.1V     437.4mA    265.9mA    1.95A
-1.3V     206.2mA    131.2mA    584.1mA
-1.2V     179.2mA    117.1mA    424.6mA
-1V       130.3mA    89.73mA    174.8mA
700mV     -76.22mA   -46.39mA   -107.9mA
3V        -122mA     -85.48mA   -174.7mA
3.4V      -173.9mA   -274.4mA   -202.4mA
3.6V      -417.3mA   -411.1mA   -237.5mA
3.7V      -585.5mA   -481.6mA   -324.5mA
3.8V      -761.6mA   -552.8mA   -1.161A
5V        -3.006A    -1.433A    -22.28A
[Ramp]
| variable   typ   min   max
dV/dt_r   1.2678/0.2984ns   1.0574/0.9448ns   1.4438/0.1484ns
dV/dt_f   1.3274/0.7684ns   1.1570/1.7883ns   1.4699/0.3405ns
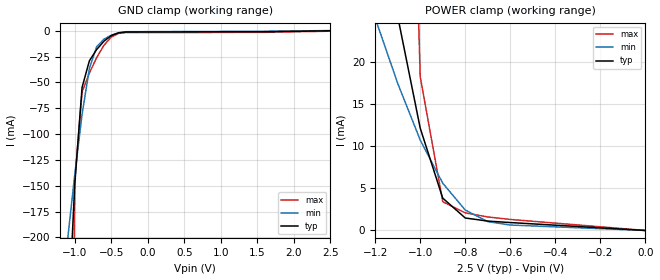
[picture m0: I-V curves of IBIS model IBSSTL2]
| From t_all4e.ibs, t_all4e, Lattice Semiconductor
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|   IBSSTL2
[Model]   IBSSTL2
Model_type   Input
Polarity   Non-Inverting
C_comp   2pF   2pF   2pF
Vinl = 1.07
Vinh = 1.43
[Temperature Range]   25.0000   125.0000   -40.0000
[Voltage Range]   2.5000V   2.3000V   2.7000V
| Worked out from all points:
|   POWER clamp passes 1 mA (typ) near -0.63 V on its own axis
[GND_clamp]
|voltage   I(typ)   I(min)   I(max)
-2.5V     -2.881A    -1.21A     -25.75A
-1.1V     -297.5mA   -203.4mA   -981mA
-1V       -148.7mA   -139.2mA   -145.5mA
-900mV    -54.87mA   -81.04mA   -59.25mA
-800mV    -29.1mA    -36.59mA   -41.04mA
-700mV    -18.14mA   -15.42mA   -25.96mA
-600mV    -10.05mA   -8.126mA   -14.01mA
-500mV    -4.649mA   -4.22mA    -6.019mA
-400mV    -1.942mA   -1.93mA    -2.491mA
-300mV    -1.205mA   -913.6uA   -1.798mA
1.6V      -908.5uA   -465.9uA   -1.513mA
2.5V      116.6nA    193.6uA    -397.1uA
[POWER_clamp]
|voltage   I(typ)   I(min)   I(max)
-2.5V     387.1mA    208.6mA    2.433A
-1.2V     42.24mA    25.27mA    246.1mA
-1.1V     25.48mA    17.51mA    110.3mA
-1V       12.17mA    10.76mA    18.3mA
-900mV    3.847mA    5.621mA    3.417mA
-800mV    1.485mA    2.43mA     2.098mA
-700mV    1.118mA    1.055mA    1.609mA
-600mV    943uA      647.8uA    1.313mA
0V        116.6nA    860.2nA    39.43nA
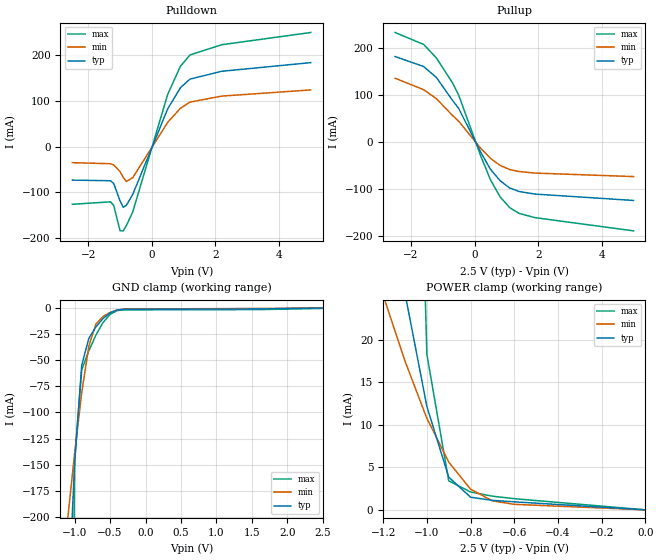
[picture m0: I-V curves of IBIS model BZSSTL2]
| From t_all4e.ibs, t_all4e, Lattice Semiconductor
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|   BZSSTL2
[Model]   BZSSTL2
Model_type   I/O
Polarity   Non-Inverting
Enable   Active-Low
C_comp   2pF   2pF   2pF
Vinl = 1.07
Vinh = 1.43
[Temperature Range]   25.0000   125.0000   -40.0000
[Voltage Range]   2.5000V   2.3000V   2.7000V
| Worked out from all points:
|   slope of the pulldown table from 0 to 0.375 V, typ, clamps not added: 5.83 ohm
|   slope of the pullup table from 0 to 0.375 V, typ, clamps not added: 7.44 ohm
|   POWER clamp passes 1 mA (typ) near -0.63 V on its own axis
[Pulldown]
|voltage   I(typ)   I(min)   I(max)
-2.5V     -73.19mA   -35.01mA   -126.1mA
-1.3V     -74.56mA   -37.37mA   -120.7mA
-1.2V     -80.45mA   -39.89mA   -128.5mA
-1V       -118.8mA   -54.55mA   -184mA
-900mV    -132.6mA   -67.23mA   -184.2mA
-800mV    -128.1mA   -76.25mA   -172.7mA
-600mV    -104.4mA   -67.72mA   -142.5mA
500mV     82.91mA    53.35mA    114.6mA
900mV     128.9mA    83.99mA    176mA
1.2V      147.7mA    97.46mA    200.6mA
2.2V      164.9mA    110.6mA    223mA
5V        183.8mA    124.1mA    249.7mA
[Pullup]
|voltage   I(typ)   I(min)   I(max)
-2.5V     181.7mA    135.5mA    232.9mA
-1.6V     160.3mA    110.9mA    207.4mA
-1.2V     137mA      91.84mA    178.5mA
-700mV    88.69mA    56.47mA    126.3mA
-500mV    71.18mA    43.76mA    99.47mA
200mV     -23.23mA   -14.36mA   -31.34mA
500mV     -58.61mA   -35.25mA   -80.92mA
800mV     -82.76mA   -50.23mA   -117.2mA
1.1V      -98.38mA   -59.16mA   -140.1mA
1.4V      -106mA     -63.46mA   -152.7mA
1.9V      -111.5mA   -66.74mA   -161.7mA
5V        -125.1mA   -74.21mA   -189.9mA
[GND_clamp]
|voltage   I(typ)   I(min)   I(max)
-2.5V     -2.881A    -1.21A     -25.75A
-1.1V     -297.5mA   -203.4mA   -981mA
-1V       -148.7mA   -139.2mA   -145.5mA
-900mV    -54.87mA   -81.04mA   -59.25mA
-800mV    -29.1mA    -36.59mA   -41.04mA
-700mV    -18.14mA   -15.42mA   -25.96mA
-600mV    -10.05mA   -8.126mA   -14.01mA
-500mV    -4.649mA   -4.22mA    -6.019mA
-400mV    -1.942mA   -1.93mA    -2.491mA
-300mV    -1.205mA   -913.6uA   -1.798mA
1.6V      -908.5uA   -465.9uA   -1.513mA
2.5V      116.6nA    193.6uA    -397.1uA
[POWER_clamp]
|voltage   I(typ)   I(min)   I(max)
-2.5V     387.1mA    208.6mA    2.433A
-1.2V     42.24mA    25.27mA    246.1mA
-1.1V     25.48mA    17.51mA    110.3mA
-1V       12.17mA    10.76mA    18.3mA
-900mV    3.847mA    5.621mA    3.417mA
-800mV    1.485mA    2.43mA     2.098mA
-700mV    1.118mA    1.055mA    1.609mA
-600mV    943uA      647.8uA    1.313mA
0V        116.6nA    860.2nA    39.43nA
[Ramp]
| variable   typ   min   max
dV/dt_r   1.2678/0.2984ns   1.0574/0.9448ns   1.4438/0.1484ns
dV/dt_f   1.3274/0.7684ns   1.1570/1.7883ns   1.4699/0.3405ns
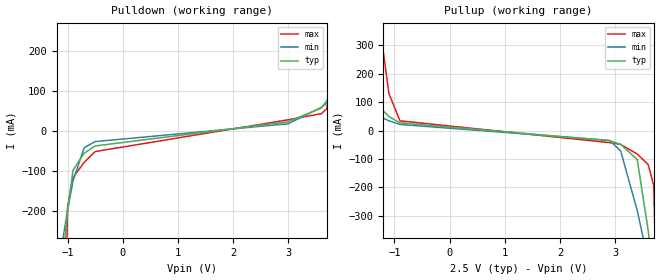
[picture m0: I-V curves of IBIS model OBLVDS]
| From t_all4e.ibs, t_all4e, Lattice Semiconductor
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|   OBLVDS
[Model]   OBLVDS
Model_type   Output
Polarity   Non-Inverting
C_comp   2pF   2pF   2pF
[Temperature Range]   25.0000   125.0000   -40.0000
[Voltage Range]   2.5000V   2.3000V   2.7000V
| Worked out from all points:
|   slope of the pulldown table from 0 to 0.375 V, typ, clamps not added: 62.4 ohm
|   slope of the pullup table from 0 to 0.375 V, typ, clamps not added: 134 ohm
[Pulldown]
|voltage   I(typ)   I(min)   I(max)
-2.5V     -3.104A    -1.609A    -23.56A
-1.1V     -354.1mA   -283.2mA   -940.7mA
-1V       -197.8mA   -199.6mA   -191.5mA
-900mV    -98.89mA   -125.3mA   -117.3mA
-700mV    -56.91mA   -43.11mA   -79.73mA
-500mV    -38.58mA   -27.63mA   -52.6mA
3V        22mA       16.9mA     26.91mA
3.6V      56.2mA     57.99mA    42.27mA
3.7V      74.99mA    69.15mA    54.6mA
3.9V      120.4mA    94.59mA    278.1mA
4.4V      255.7mA    171.8mA    1.104A
5V        439.6mA    279.9mA    2.148A
[Pullup]
|voltage   I(typ)   I(min)   I(max)
-2.5V     415.8mA    225.9mA    2.473A
-1.4V     110mA      62.31mA    581.3mA
-1.3V     87.65mA    52.06mA    419.5mA
-1.1V     49.29mA    34.4mA     130.1mA
-900mV    26.9mA     21.37mA    34.19mA
2.9V      -35.64mA   -34.91mA   -42.62mA
3.1V      -48.8mA    -71.5mA    -48.85mA
3.4V      -101.7mA   -281.1mA   -82.66mA
3.6V      -352.3mA   -459.1mA   -120.1mA
3.7V      -528.4mA   -551.2mA   -193.6mA
3.8V      -714.4mA   -644.6mA   -939.3mA
5V        -3.098A    -1.8A      -20.21A
[Ramp]
| variable   typ   min   max
dV/dt_r   40.9080mV/0.1049ns  16.2852mV/0.1040ns  81.7728mV/0.1137ns
dV/dt_f   72.1140mV/0.0949ns  59.8020mV/0.1420ns  80.7180mV/0.0752ns
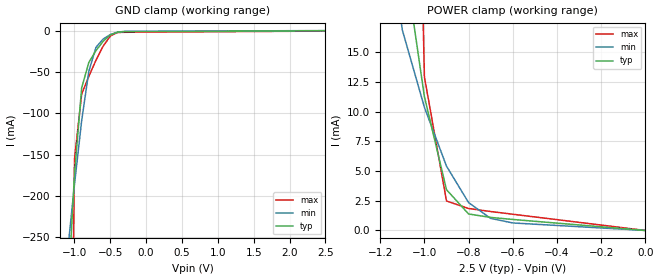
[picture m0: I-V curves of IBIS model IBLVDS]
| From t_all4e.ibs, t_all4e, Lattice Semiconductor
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|   IBLVDS
[Model]   IBLVDS
Model_type   Input
Polarity   Non-Inverting
C_comp   2pF   2pF   2pF
Vinl = 0
Vinh = 2.4
[Temperature Range]   25.0000   125.0000   -40.0000
[Voltage Range]   2.5000V   2.3000V   2.7000V
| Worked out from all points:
|   POWER clamp passes 1 mA (typ) near -0.64 V on its own axis
[GND_clamp]
|voltage   I(typ)   I(min)   I(max)
-2.5V     -3.086A    -1.598A    -23.54A
-1.1V     -334.4mA   -271mA     -912mA
-1V       -174.2mA   -186.2mA   -155.2mA
-900mV    -69.32mA   -109mA     -76.82mA
-800mV    -38.38mA   -49.19mA   -55.22mA
-700mV    -24.04mA   -20.13mA   -35.71mA
-600mV    -12.82mA   -10.03mA   -18.65mA
-500mV    -5.124mA   -4.644mA   -6.458mA
-400mV    -1.68mA    -1.744mA   -2.166mA
-300mV    -1.13mA    -774.3uA   -1.878mA
2.5V      702.6pA    188.1uA    -423.5uA
[POWER_clamp]
|voltage   I(typ)   I(min)   I(max)
-2.5V     387.2mA    206.8mA    2.429A
-1.1V     24.06mA    16.88mA    97.15mA
-1V       11.27mA    10.37mA    12.94mA
-900mV    3.431mA    5.412mA    2.481mA
-800mV    1.388mA    2.345mA    1.851mA
-700mV    1.097mA    1.016mA    1.594mA
-600mV    927uA      632.4uA    1.366mA
0V        702.6pA    48.56nA    369.6pA
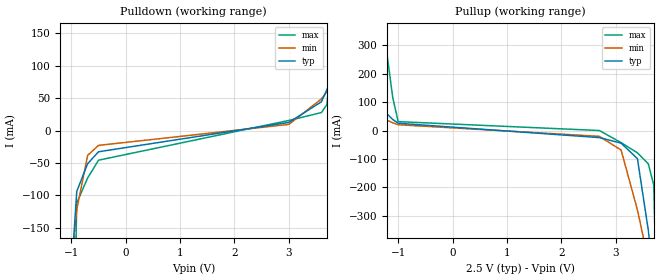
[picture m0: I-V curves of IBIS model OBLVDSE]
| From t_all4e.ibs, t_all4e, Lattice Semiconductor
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|   OBLVDSE
[Model]   OBLVDSE
Model_type   Output
Polarity   Non-Inverting
C_comp   2pF   2pF   2pF
[Temperature Range]   25.0000   125.0000   -40.0000
[Voltage Range]   2.5000V   2.3000V   2.7000V
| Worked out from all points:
|   slope of the pulldown table from 0 to 0.375 V, typ, clamps not added: 77.5 ohm
|   slope of the pullup table from 0 to 0.375 V, typ, clamps not added: 2.08 kohm
[Pulldown]
|voltage   I(typ)   I(min)   I(max)
-2.5V     -3.101A    -1.607A    -23.56A
-1.1V     -351.8mA   -281.5mA   -938.4mA
-900mV    -94.08mA   -122.8mA   -111.8mA
-700mV    -51.2mA    -38.44mA   -73.39mA
-500mV    -32.84mA   -22.99mA   -45.84mA
3V        12.51mA    9.441mA    15.57mA
3.6V      44.44mA    48.84mA    27.75mA
3.7V      63.15mA    59.84mA    40.02mA
3.8V      84.99mA    71.92mA    126.4mA
3.9V      108.6mA    84.98mA    264.2mA
4.5V      272.3mA    178.3mA    1.261A
5V        427.4mA    269mA      2.137A
[Pullup]
|voltage   I(typ)   I(min)   I(max)
-2.5V     406.1mA    217.3mA    2.465A
-1.4V     98.87mA    54.51mA    566.9mA
-1.3V     76.64mA    44.49mA    404.9mA
-1.1V     38.94mA    27.43mA    115.8mA
-1V       25.6mA     20.43mA    31.41mA
2.7V      -24.92mA   -20.5mA    0A
3.1V      -44.47mA   -68.87mA   -42.77mA
3.4V      -99.24mA   -280.2mA   -78.63mA
3.6V      -352mA     -458.3mA   -117.5mA
3.7V      -527.8mA   -550.4mA   -192.4mA
3.8V      -713.7mA   -643.7mA   -940.2mA
5V        -3.096A    -1.799A    -20.2A
[Ramp]
| variable   typ   min   max
dV/dt_r   172.8090mV/0.5240ns 118.0590mV/0.9986ns 240.8100mV/0.3609ns
dV/dt_f   332.2080mV/0.3555ns 235.7340mV/0.5258ns 418.5900mV/0.2706ns
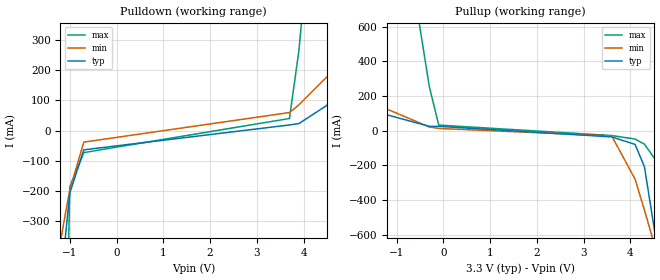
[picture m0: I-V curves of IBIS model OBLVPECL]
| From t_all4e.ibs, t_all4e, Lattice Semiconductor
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|   OBLVPECL
[Model]   OBLVPECL
Model_type   Output
Polarity   Non-Inverting
C_comp   2pF   2pF   2pF
[Temperature Range]   25.0000   125.0000   -40.0000
[Voltage Range]   3.3000V   3.0000V   3.6000V
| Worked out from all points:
|   slope of the pullup table from 0 to 0.495 V, typ, clamps not added: 2.01 kohm
[Pulldown]
|voltage   I(typ)   I(min)   I(max)
-3.3V     -4.735A    -2.389A    -37.01A
-2.1V     -2.304A    -1.219A    -16.88A
-1.6V     -1.308A    -740.4mA   -8.615A
-1.5V     -1.112A    -646.2mA   -6.99A
-1.2V     -540.5mA   -369.7mA   -2.294A
-1.1V     -363.2mA   -281.5mA   -938.4mA
-1V       -207.7mA   -197.7mA   -187.3mA
-700mV    -64.24mA   -38.44mA   -73.39mA
3.7V      18.51mA    59.84mA    40.02mA
3.9V      22.97mA    84.98mA    264.2mA
4.5V      83.68mA    178.3mA    1.261A
6.6V      709.4mA    596mA      4.982A
[Pullup]
|voltage   I(typ)   I(min)   I(max)
-3.3V     682.4mA    522.9mA    5.501A
-1.3V     97.32mA    134mA      1.939A
-300mV    24.21mA    20.43mA    251.6mA
-100mV    24.09mA    12.05mA    31.41mA
3.6V      -36.79mA   -31.09mA   -28.96mA
4.1V      -79.9mA    -280.2mA   -49.26mA
4.3V      -208.2mA   -458.3mA   -78.63mA
4.6V      -718.5mA   -737.9mA   -192.4mA
4.8V      -1.103A    -928mA     -2.291A
5.2V      -1.894A    -1.313A    -8.609A
5.8V      -3.099A    -1.896A    -18.53A
6.6V      -4.723A    -2.68A     -31.95A
[Ramp]
| variable   typ   min   max
dV/dt_r   274.4328mV/0.3561ns 118.0590mV/0.9986ns 240.8100mV/0.3609ns
dV/dt_f   473.6760mV/0.3614ns 235.7340mV/0.5258ns 418.5900mV/0.2706ns
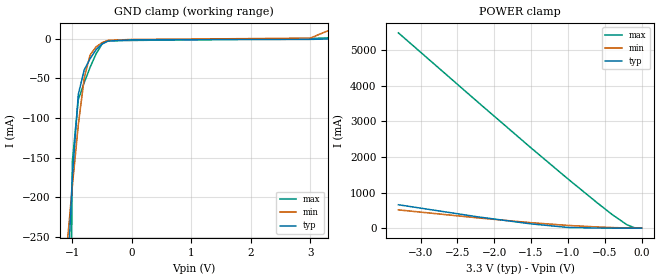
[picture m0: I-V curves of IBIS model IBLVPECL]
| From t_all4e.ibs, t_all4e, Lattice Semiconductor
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|   IBLVPECL
[Model]   IBLVPECL
Model_type   Input
Polarity   Non-Inverting
C_comp   2pF   2pF   2pF
Vinl = 0
Vinh = 2.4
[Temperature Range]   25.0000   125.0000   -40.0000
[Voltage Range]   3.3000V   3.0000V   3.6000V
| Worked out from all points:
|   POWER clamp passes 1 mA (typ) near -0.43 V on its own axis
[GND_clamp]
|voltage   I(typ)   I(min)   I(max)
-3.3V     -4.71A     -2.379A    -36.99A
-1.1V     -335.4mA   -271mA     -912mA
-1V       -175.2mA   -186.2mA   -155.2mA
-900mV    -70.09mA   -109mA     -76.82mA
-800mV    -39.14mA   -49.19mA   -55.22mA
-700mV    -24.83mA   -20.13mA   -35.71mA
-600mV    -13.67mA   -10.03mA   -18.65mA
-500mV    -6.058mA   -4.644mA   -6.458mA
-400mV    -2.697mA   -1.744mA   -2.166mA
0V        -1.095mA   -620.2uA   -1.857mA
3V        -520.2uA   1.016mA    682.5uA
3.3V      1.35nA     10.37mA    1.366mA
[POWER_clamp]
|voltage   I(typ)   I(min)   I(max)
-3.3V     657mA      512.8mA    5.481A
-2.2V     310.7mA    284.3mA    3.499A
-1.5V     120.5mA    153.4mA    2.253A
-1V       20.05mA    77.24mA    1.383A
-600mV    2.468mA    32.8mA     708mA
-400mV    831.2uA    16.88mA    383.8mA
-200mV    369.1uA    5.412mA    97.15mA
-100mV    183uA      2.345mA    12.94mA
0V        1.35nA     1.016mA    2.481mA
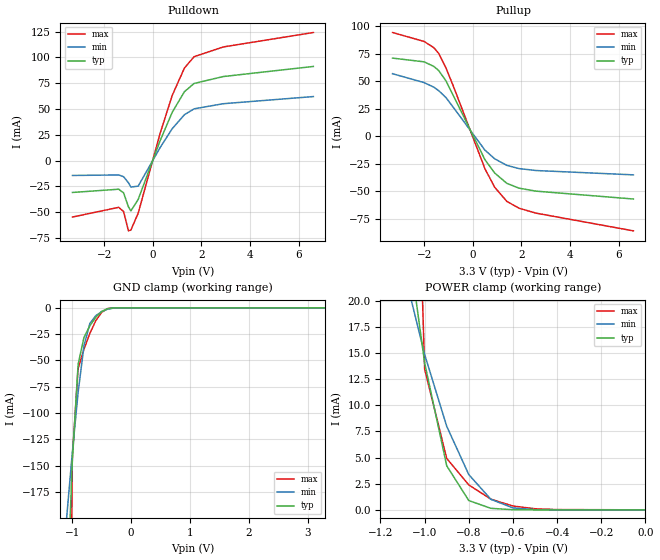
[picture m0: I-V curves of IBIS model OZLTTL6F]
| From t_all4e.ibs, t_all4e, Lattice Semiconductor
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|   OZLTTL6F
[Model]   OZLTTL6F
Model_type   3-state
Polarity   Non-Inverting
Enable   Active-Low
C_comp   2pF   2pF   2pF
[Temperature Range]   25.0000   125.0000   -40.0000
[Voltage Range]   3.3000V   3.0000V   3.6000V
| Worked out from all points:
|   slope of the pulldown table from 0 to 0.495 V, typ, clamps not added: 16.1 ohm
|   slope of the pullup table from 0 to 0.495 V, typ, clamps not added: 23.4 ohm
|   GND clamp passes 1 mA (typ) near -0.41 V on its own axis
|   POWER clamp passes 1 mA (typ) near -0.80 V on its own axis
[Pulldown]
|voltage   I(typ)   I(min)   I(max)
-3.3V     -30.88mA   -14.4mA    -54.7mA
-1.4V     -27.73mA   -13.92mA   -45.3mA
-1.2V     -31.3mA    -15.6mA    -49.4mA
-1V       -44.81mA   -21.51mA   -68.11mA
-900mV    -48.8mA    -25.67mA   -67.3mA
-600mV    -37.63mA   -24.73mA   -51.01mA
300mV     19.2mA     12.57mA    26.28mA
800mV     46.88mA    30.99mA    63.28mA
1.3V      66.8mA     44.5mA     89.73mA
1.7V      74.83mA    50.21mA    100.8mA
2.9V      81.51mA    55.16mA    110.2mA
6.6V      91.29mA    62.1mA     124.2mA
[Pullup]
|voltage   I(typ)   I(min)   I(max)
-3.3V     70.9mA     56.74mA    94.14mA
-2V       67.51mA    48.64mA    85.98mA
-1.6V     63.33mA    44.48mA    80.35mA
-1.4V     59.56mA    41.33mA    75.01mA
-1.1V     50.13mA    35.01mA    61.79mA
-800mV    36.83mA    26.18mA    45.45mA
500mV     -21.37mA   -12.68mA   -29.6mA
900mV     -33.42mA   -20.51mA   -46.39mA
1.4V      -42.79mA   -26.49mA   -59.17mA
1.9V      -47.15mA   -29.37mA   -65.36mA
2.6V      -49.86mA   -31.14mA   -69.82mA
6.6V      -56.99mA   -35.07mA   -85.9mA
[GND_clamp]
|voltage   I(typ)   I(min)   I(max)
-3.3V     -4.405A    -1.803A    -40.47A
-1.1V     -296.4mA   -202.8mA   -979.3mA
-1V       -147.6mA   -138.6mA   -143.7mA
-900mV    -53.77mA   -80.42mA   -57.51mA
-800mV    -28mA      -35.97mA   -39.29mA
-700mV    -17.04mA   -14.79mA   -24.22mA
-600mV    -8.941mA   -7.498mA   -12.27mA
-500mV    -3.546mA   -3.592mA   -4.281mA
-400mV    -840.6uA   -1.303mA   -756.1uA
-300mV    -105.6uA   -288uA     -66.64uA
3.3V      136.3nA    1.082uA    44.16nA
[POWER_clamp]
|voltage   I(typ)   I(min)   I(max)
-3.3V     682mA      379.6mA    3.878A
-1.1V     29.47mA    23.43mA    82.94mA
-1V       14.04mA    14.85mA    13.44mA
-900mV    4.209mA    7.985mA    4.915mA
-800mV    886uA      3.367mA    2.382mA
-700mV    145.7uA    1.006mA    1.019mA
-600mV    12.72uA    189uA      364.4uA
-500mV    804.9nA    21.16uA    104.9uA
-400mV    169.6nA    2.448uA    24.33uA
0V        136.3nA    964.9nA    94.06nA
[Ramp]
| variable   typ   min   max
dV/dt_r   1.2314/0.3418ns   0.8318/0.5486ns   1.5920/0.1917ns
dV/dt_f   1.4786/0.4245ns   1.1737/0.8814ns   1.7342/0.2230ns
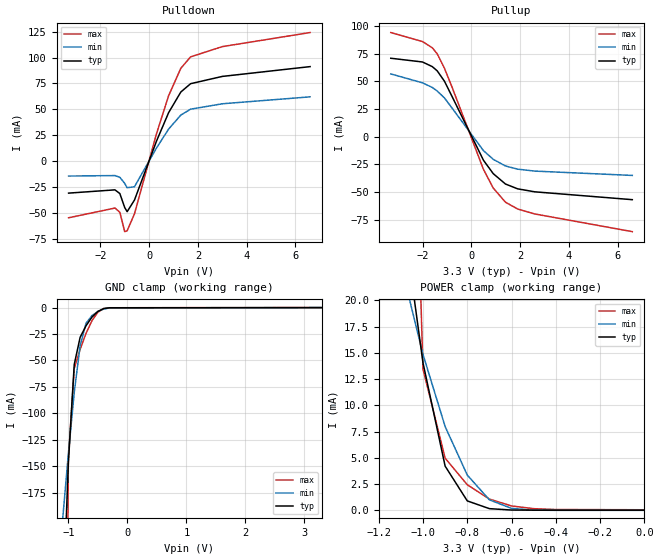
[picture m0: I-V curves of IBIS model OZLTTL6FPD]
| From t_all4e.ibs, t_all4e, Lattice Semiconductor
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|   OZLTTL6FPD
[Model]   OZLTTL6FPD
Model_type   3-state
Polarity   Non-Inverting
Enable   Active-Low
C_comp   2pF   2pF   2pF
[Temperature Range]   25.0000   125.0000   -40.0000
[Voltage Range]   3.3000V   3.0000V   3.6000V
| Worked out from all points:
|   slope of the pulldown table from 0 to 0.495 V, typ, clamps not added: 16.1 ohm
|   slope of the pullup table from 0 to 0.495 V, typ, clamps not added: 23.4 ohm
|   GND clamp passes 1 mA (typ) near -0.40 V on its own axis
|   POWER clamp passes 1 mA (typ) near -0.80 V on its own axis
[Pulldown]
|voltage   I(typ)   I(min)   I(max)
-3.3V     -30.88mA   -14.4mA    -54.7mA
-1.4V     -27.72mA   -13.92mA   -45.3mA
-1.2V     -31.29mA   -15.59mA   -49.39mA
-1V       -44.8mA    -21.51mA   -68.08mA
-900mV    -48.78mA   -25.66mA   -67.21mA
-600mV    -37.58mA   -24.7mA    -50.92mA
300mV     19.17mA    12.56mA    26.25mA
800mV     46.84mA    30.97mA    63.2mA
1.3V      66.75mA    44.48mA    89.65mA
1.7V      74.79mA    50.19mA    100.7mA
3V        81.83mA    55.4mA     110.6mA
6.6V      91.29mA    62.1mA     124.2mA
[Pullup]
|voltage   I(typ)   I(min)   I(max)
-3.3V     70.9mA     56.74mA    94.14mA
-2V       67.51mA    48.64mA    85.98mA
-1.6V     63.33mA    44.48mA    80.35mA
-1.4V     59.56mA    41.33mA    75.01mA
-1.1V     50.13mA    35.01mA    61.78mA
-800mV    36.81mA    26.18mA    45.38mA
500mV     -21.4mA    -12.69mA   -29.67mA
900mV     -33.46mA   -20.53mA   -46.48mA
1.4V      -42.83mA   -26.51mA   -59.26mA
1.9V      -47.19mA   -29.39mA   -65.44mA
2.6V      -49.89mA   -31.15mA   -69.9mA
6.6V      -56.99mA   -35.07mA   -85.9mA
[GND_clamp]
|voltage   I(typ)   I(min)   I(max)
-3.3V     -4.405A    -1.803A    -40.47A
-1.1V     -296.4mA   -202.8mA   -979.3mA
-1V       -147.6mA   -138.6mA   -143.7mA
-900mV    -53.79mA   -80.42mA   -57.6mA
-800mV    -28.05mA   -35.98mA   -39.41mA
-700mV    -17.1mA    -14.8mA    -24.33mA
-600mV    -8.999mA   -7.523mA   -12.36mA
-500mV    -3.595mA   -3.617mA   -4.359mA
-400mV    -879.9uA   -1.324mA   -818.8uA
-300mV    -134.5uA   -303.4uA   -113.2uA
3.3V      27.16uA    10.44uA    65.22uA
[POWER_clamp]
|voltage   I(typ)   I(min)   I(max)
-3.3V     682mA      379.6mA    3.878A
-1.1V     29.47mA    23.43mA    82.94mA
-1V       14.05mA    14.85mA    13.46mA
-900mV    4.218mA    7.985mA    4.978mA
-800mV    910uA      3.369mA    2.448mA
-700mV    172.8uA    1.011mA    1.084mA
-600mV    39.84uA    197.6uA    429.9uA
-500mV    27.92uA    30.49uA    170.3uA
-400mV    27.27uA    11.82uA    89.74uA
0V        27.16uA    10.3uA     65.38uA
[Ramp]
| variable   typ   min   max
dV/dt_r   1.2314/0.3418ns   0.8318/0.5486ns   1.5920/0.1917ns
dV/dt_f   1.4786/0.4245ns   1.1737/0.8814ns   1.7342/0.2230ns
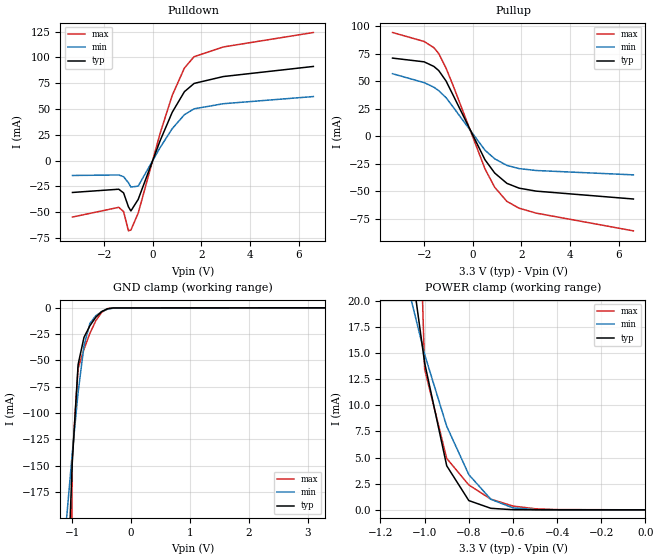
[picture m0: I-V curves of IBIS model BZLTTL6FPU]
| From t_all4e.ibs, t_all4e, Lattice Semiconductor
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|   BZLTTL6FPU
[Model]   BZLTTL6FPU
Model_type   I/O
Polarity   Non-Inverting
Enable   Active-Low
C_comp   2pF   2pF   2pF
Vinl = 0.5
Vinh = 2.64
[Temperature Range]   25.0000   125.0000   -40.0000
[Voltage Range]   3.3000V   3.0000V   3.6000V
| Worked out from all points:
|   slope of the pulldown table from 0 to 0.495 V, typ, clamps not added: 16.1 ohm
|   slope of the pullup table from 0 to 0.495 V, typ, clamps not added: 23.4 ohm
|   GND clamp passes 1 mA (typ) near -0.41 V on its own axis
|   POWER clamp passes 1 mA (typ) near -0.80 V on its own axis
[Pulldown]
|voltage   I(typ)   I(min)   I(max)
-3.3V     -30.88mA   -14.4mA    -54.7mA
-1.4V     -27.73mA   -13.92mA   -45.3mA
-1.2V     -31.3mA    -15.59mA   -49.39mA
-1V       -44.81mA   -21.51mA   -68.1mA
-900mV    -48.8mA    -25.67mA   -67.28mA
-600mV    -37.61mA   -24.72mA   -50.97mA
300mV     19.22mA    12.58mA    26.32mA
800mV     46.9mA     31.01mA    63.32mA
1.3V      66.82mA    44.51mA    89.77mA
1.7V      74.85mA    50.22mA    100.8mA
2.9V      81.51mA    55.16mA    110.2mA
6.6V      91.29mA    62.1mA     124.2mA
[Pullup]
|voltage   I(typ)   I(min)   I(max)
-3.3V     70.9mA     56.74mA    94.14mA
-2V       67.51mA    48.64mA    85.98mA
-1.6V     63.33mA    44.48mA    80.35mA
-1.4V     59.56mA    41.33mA    75.01mA
-1.1V     50.13mA    35.01mA    61.79mA
-800mV    36.83mA    26.18mA    45.45mA
500mV     -21.37mA   -12.68mA   -29.6mA
900mV     -33.41mA   -20.51mA   -46.37mA
1.4V      -42.77mA   -26.48mA   -59.14mA
1.9V      -47.13mA   -29.36mA   -65.32mA
2.6V      -49.83mA   -31.12mA   -69.78mA
6.6V      -56.99mA   -35.07mA   -85.9mA
[GND_clamp]
|voltage   I(typ)   I(min)   I(max)
-3.3V     -4.405A    -1.803A    -40.47A
-1.1V     -296.4mA   -202.8mA   -979.3mA
-1V       -147.6mA   -138.6mA   -143.7mA
-900mV    -53.78mA   -80.42mA   -57.54mA
-800mV    -28.01mA   -35.97mA   -39.33mA
-700mV    -17.06mA   -14.8mA    -24.26mA
-600mV    -8.965mA   -7.508mA   -12.31mA
-500mV    -3.57mA    -3.604mA   -4.321mA
-400mV    -864.4uA   -1.316mA   -796uA
-300mV    -129.4uA   -300.8uA   -106.6uA
3.3V      136.3nA    1.082uA    44.16nA
[POWER_clamp]
|voltage   I(typ)   I(min)   I(max)
-3.3V     682mA      379.6mA    3.878A
-1.1V     29.47mA    23.43mA    82.94mA
-1V       14.04mA    14.85mA    13.44mA
-900mV    4.209mA    7.985mA    4.915mA
-800mV    886uA      3.367mA    2.382mA
-700mV    145.7uA    1.006mA    1.019mA
-600mV    12.72uA    189uA      364.4uA
-500mV    804.9nA    21.16uA    104.9uA
-400mV    169.6nA    2.448uA    24.33uA
0V        136.3nA    964.9nA    94.06nA
[Ramp]
| variable   typ   min   max
dV/dt_r   1.2314/0.3418ns   0.8318/0.5486ns   1.5920/0.1917ns
dV/dt_f   1.4786/0.4245ns   1.1737/0.8814ns   1.7342/0.2230ns
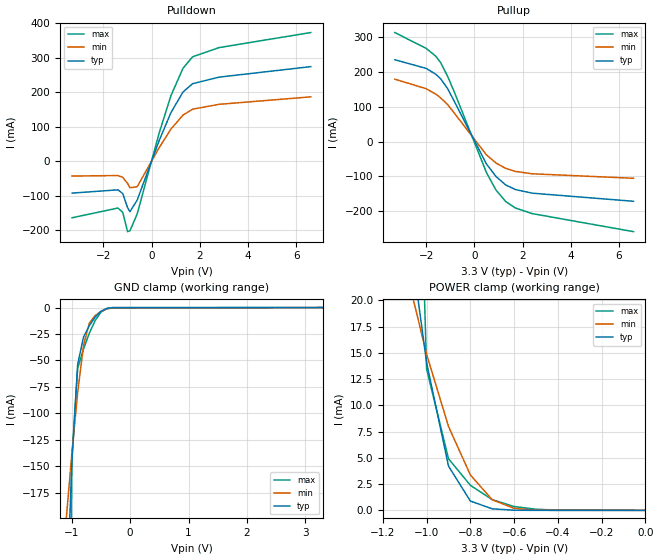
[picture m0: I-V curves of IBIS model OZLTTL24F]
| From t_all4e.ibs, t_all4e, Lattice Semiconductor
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|   OZLTTL24F
[Model]   OZLTTL24F
Model_type   3-state
Polarity   Non-Inverting
Enable   Active-Low
C_comp   2pF   2pF   2pF
[Temperature Range]   25.0000   125.0000   -40.0000
[Voltage Range]   3.3000V   3.0000V   3.6000V
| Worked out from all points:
|   slope of the pulldown table from 0 to 0.495 V, typ, clamps not added: 5.38 ohm
|   slope of the pullup table from 0 to 0.495 V, typ, clamps not added: 7.79 ohm
|   GND clamp passes 1 mA (typ) near -0.41 V on its own axis
|   POWER clamp passes 1 mA (typ) near -0.80 V on its own axis
[Pulldown]
|voltage   I(typ)   I(min)   I(max)
-3.3V     -92.63mA   -43.21mA   -164.1mA
-1.4V     -83.18mA   -41.77mA   -135.9mA
-1.2V     -93.89mA   -46.78mA   -148.2mA
-1V       -134.4mA   -64.53mA   -204.3mA
-900mV    -146.4mA   -77.01mA   -201.9mA
-600mV    -112.9mA   -74.18mA   -153mA
300mV     57.59mA    37.71mA    78.85mA
800mV     140.6mA    92.98mA    189.8mA
1.3V      200.4mA    133.5mA    269.2mA
1.7V      224.5mA    150.6mA    302.4mA
2.8V      243.5mA    164.7mA    329.1mA
6.6V      273.9mA    186.3mA    372.7mA
[Pullup]
|voltage   I(typ)   I(min)   I(max)
-3.3V     234.1mA    178.5mA    312mA
-2V       209.4mA    151.3mA    266.7mA
-1.6V     192.5mA    135.6mA    244.2mA
-1.4V     179.8mA    125.1mA    226.2mA
-1.1V     150.4mA    105.2mA    185.4mA
-800mV    110.5mA    78.55mA    136.3mA
500mV     -64.1mA    -38.04mA   -88.81mA
900mV     -100.3mA   -61.54mA   -139.2mA
1.3V      -124.2mA   -76.79mA   -171.8mA
1.7V      -137.4mA   -85.43mA   -190.2mA
2.4V      -147.8mA   -92.3mA    -206.3mA
6.6V      -171mA     -105.2mA   -257.9mA
[GND_clamp]
|voltage   I(typ)   I(min)   I(max)
-3.3V     -4.405A    -1.803A    -40.47A
-1.1V     -296.4mA   -202.8mA   -979.3mA
-1V       -147.6mA   -138.6mA   -143.7mA
-900mV    -53.77mA   -80.42mA   -57.51mA
-800mV    -28mA      -35.97mA   -39.29mA
-700mV    -17.04mA   -14.79mA   -24.22mA
-600mV    -8.941mA   -7.498mA   -12.27mA
-500mV    -3.546mA   -3.592mA   -4.281mA
-400mV    -840.6uA   -1.303mA   -756.1uA
-300mV    -105.6uA   -288uA     -66.64uA
3.3V      136.3nA    1.082uA    44.16nA
[POWER_clamp]
|voltage   I(typ)   I(min)   I(max)
-3.3V     682mA      379.6mA    3.878A
-1.1V     29.47mA    23.43mA    82.94mA
-1V       14.04mA    14.85mA    13.44mA
-900mV    4.209mA    7.985mA    4.915mA
-800mV    886uA      3.367mA    2.382mA
-700mV    145.7uA    1.006mA    1.019mA
-600mV    12.72uA    189uA      364.4uA
-500mV    804.9nA    21.16uA    104.9uA
-400mV    169.6nA    2.448uA    24.33uA
0V        136.3nA    964.9nA    94.06nA
[Ramp]
| variable   typ   min   max
dV/dt_r   1.7016/0.2402ns   1.3987/0.4399ns   1.9654/0.1226ns
dV/dt_f   1.7950/0.1991ns   1.5459/0.4478ns   2.0177/0.1041ns
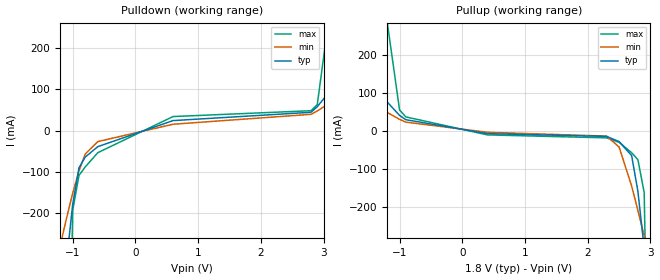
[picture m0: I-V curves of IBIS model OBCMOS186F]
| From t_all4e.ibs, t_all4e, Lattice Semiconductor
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|   OBCMOS186F
[Model]   OBCMOS186F
Model_type   Output
Polarity   Non-Inverting
C_comp   2pF   2pF   2pF
[Temperature Range]   25.0000   125.0000   -40.0000
[Voltage Range]   1.8000V   1.7000V   1.9000V
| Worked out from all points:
|   slope of the pulldown table from 0 to 0.27 V, typ, clamps not added: 20.5 ohm
|   slope of the pullup table from 0 to 0.27 V, typ, clamps not added: 44.7 ohm
[Pulldown]
|voltage   I(typ)   I(min)   I(max)
-1.8V     -1.578A    -705.7mA   -13.02A
-1.2V     -485.1mA   -280.6mA   -2.502A
-1.1V     -320.9mA   -214.4mA   -1.019A
-1V       -179.3mA   -152.5mA   -194.1mA
-900mV    -90.86mA   -98.27mA   -109.3mA
-800mV    -64.45mA   -57.19mA   -88.48mA
-600mV    -39.2mA    -26.91mA   -53.86mA
600mV     24.14mA    15.31mA    33.98mA
2.8V      44.35mA    39.41mA    48.18mA
2.9V      57.93mA    47.64mA    63.08mA
3.1V      95.54mA    66.68mA    291.7mA
3.6V      213.7mA    128.4mA    1.094A
[Pullup]
|voltage   I(typ)   I(min)   I(max)
-1.8V     217.7mA    119.2mA    1.262A
-1.2V     75.55mA    47.88mA    288.5mA
-1V       39.78mA    29.43mA    54.12mA
-900mV    28.49mA    22.12mA    35.87mA
400mV     -8.164mA   -4.638mA   -11.49mA
2.3V      -15.41mA   -14.68mA   -19.26mA
2.5V      -29.02mA   -43.21mA   -31.06mA
2.7V      -65.88mA   -145.9mA   -58.36mA
2.8V      -159.8mA   -210.1mA   -76.72mA
2.9V      -308.6mA   -277.4mA   -163.1mA
3V        -476.4mA   -346.5mA   -998.8mA
3.6V      -1.572A    -776.9mA   -11.21A
[Ramp]
| variable   typ   min   max
dV/dt_r   0.3289/0.3273ns   0.2014/0.4714ns   0.5419/0.2431ns
dV/dt_f   0.7315/1.0322ns   0.5583/2.0878ns   0.8623/0.4694ns
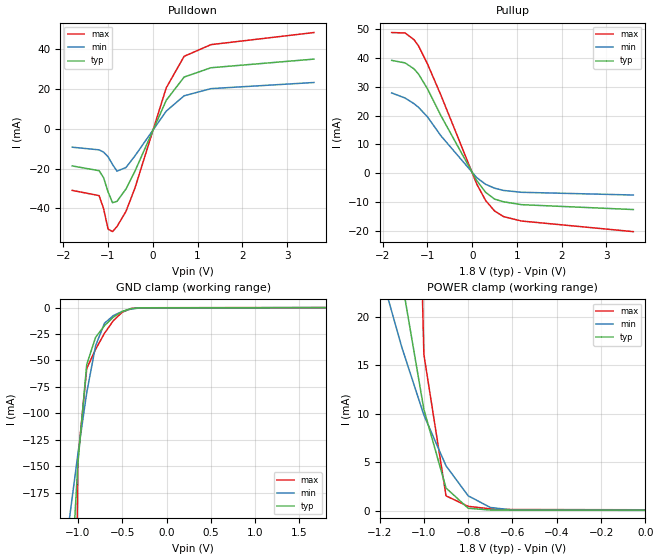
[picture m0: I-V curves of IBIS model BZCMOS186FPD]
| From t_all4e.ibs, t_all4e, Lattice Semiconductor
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|   BZCMOS186FPD
[Model]   BZCMOS186FPD
Model_type   I/O
Polarity   Non-Inverting
Enable   Active-Low
C_comp   2pF   2pF   2pF
Vinl = 0.5
Vinh = 2.64
[Temperature Range]   25.0000   125.0000   -40.0000
[Voltage Range]   1.8000V   1.7000V   1.9000V
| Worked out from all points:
|   slope of the pulldown table from 0 to 0.27 V, typ, clamps not added: 20.6 ohm
|   slope of the pullup table from 0 to 0.27 V, typ, clamps not added: 44.7 ohm
|   GND clamp passes 1 mA (typ) near -0.40 V on its own axis
|   POWER clamp passes 1 mA (typ) near -0.84 V on its own axis
[Pulldown]
|voltage   I(typ)   I(min)   I(max)
-1.8V     -18.58mA   -9.164mA   -30.9mA
-1.2V     -20.99mA   -10.5mA    -33.52mA
-1.1V     -24.48mA   -11.63mA   -40.02mA
-1V       -31.66mA   -13.95mA   -50.34mA
-900mV    -37.07mA   -17.84mA   -51.65mA
-800mV    -36.4mA    -21.22mA   -49.07mA
-600mV    -30.2mA    -19.39mA   -41.5mA
-400mV    -21.3mA    -13.56mA   -29.8mA
300mV     14.44mA    8.988mA    20.7mA
700mV     26.14mA    16.71mA    36.57mA
1.3V      30.82mA    20.31mA    42.45mA
3.6V      35.16mA    23.39mA    48.53mA
[Pullup]
|voltage   I(typ)   I(min)   I(max)
-1.8V     39.17mA    27.87mA    48.84mA
-1.5V     38.3mA     26.11mA    48.68mA
-1.3V     36.22mA    24.13mA    46.36mA
-1.2V     34.44mA    22.87mA    44.21mA
-1V       29.32mA    19.57mA    37.98mA
-700mV    20mA       13mA       27.12mA
100mV     -2.538mA   -1.521mA   -3.73mA
300mV     -6.648mA   -3.872mA   -9.495mA
500mV     -9.009mA   -5.205mA   -13.13mA
700mV     -9.935mA   -5.992mA   -15.07mA
1.1V      -10.93mA   -6.634mA   -16.61mA
3.6V      -12.63mA   -7.583mA   -20.3mA
[GND_clamp]
|voltage   I(typ)   I(min)   I(max)
-1.8V     -1.559A    -696.5mA   -12.99A
-1.1V     -296.4mA   -202.8mA   -979.3mA
-1V       -147.6mA   -138.6mA   -143.7mA
-900mV    -53.79mA   -80.42mA   -57.6mA
-800mV    -28.05mA   -35.98mA   -39.41mA
-700mV    -17.1mA    -14.8mA    -24.32mA
-600mV    -8.998mA   -7.523mA   -12.36mA
-500mV    -3.594mA   -3.617mA   -4.358mA
-400mV    -878.9uA   -1.323mA   -817.5uA
-300mV    -133.8uA   -302.9uA   -112.1uA
1.8V      37.23uA    16.06uA    76uA
[POWER_clamp]
|voltage   I(typ)   I(min)   I(max)
-1.8V     178.5mA    91.31mA    1.213A
-1.2V     41.11mA    25.02mA    244.3mA
-1.1V     23.87mA    16.9mA     108.1mA
-1V       10.45mA    9.86mA     16.13mA
-900mV    2.324mA    4.618mA    1.514mA
-800mV    230.5uA    1.518mA    431.6uA
-700mV    46.81uA    315.4uA    170.6uA
-600mV    37.66uA    50.45uA    98.99uA
0V        37.23uA    16.04uA    76.01uA
[Ramp]
| variable   typ   min   max
dV/dt_r   0.3289/0.3273ns   0.2014/0.4714ns   0.5419/0.2431ns
dV/dt_f   0.7315/1.0322ns   0.5583/2.0878ns   0.8623/0.4694ns
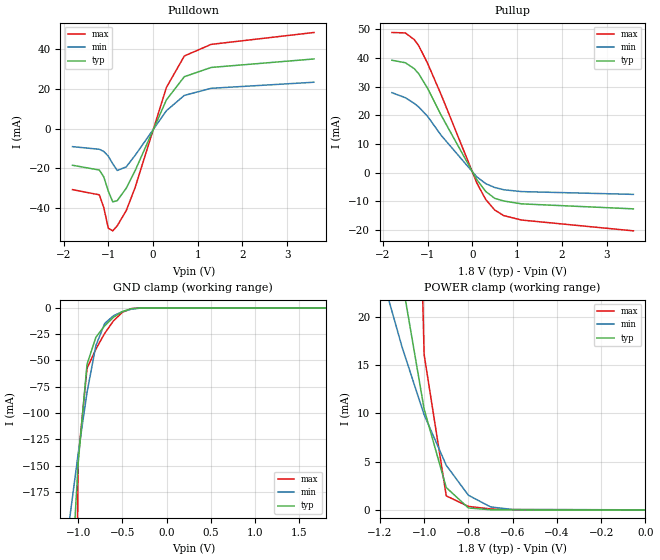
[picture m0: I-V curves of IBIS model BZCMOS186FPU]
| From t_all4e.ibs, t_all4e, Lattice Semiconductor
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|   BZCMOS186FPU
[Model]   BZCMOS186FPU
Model_type   I/O
Polarity   Non-Inverting
Enable   Active-Low
C_comp   2pF   2pF   2pF
Vinl = 0.5
Vinh = 2.64
[Temperature Range]   25.0000   125.0000   -40.0000
[Voltage Range]   1.8000V   1.7000V   1.9000V
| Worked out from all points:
|   slope of the pulldown table from 0 to 0.27 V, typ, clamps not added: 20.5 ohm
|   slope of the pullup table from 0 to 0.27 V, typ, clamps not added: 44.7 ohm
|   GND clamp passes 1 mA (typ) near -0.41 V on its own axis
|   POWER clamp passes 1 mA (typ) near -0.84 V on its own axis
[Pulldown]
|voltage   I(typ)   I(min)   I(max)
-1.8V     -18.58mA   -9.165mA   -30.9mA
-1.2V     -21mA      -10.5mA    -33.53mA
-1.1V     -24.49mA   -11.63mA   -40.04mA
-1V       -31.67mA   -13.96mA   -50.37mA
-900mV    -37.09mA   -17.85mA   -51.74mA
-800mV    -36.45mA   -21.22mA   -49.18mA
-600mV    -30.25mA   -19.41mA   -41.58mA
-400mV    -21.33mA   -13.58mA   -29.85mA
300mV     14.46mA    9.001mA    20.74mA
700mV     26.18mA    16.73mA    36.65mA
1.3V      30.86mA    20.32mA    42.53mA
3.6V      35.16mA    23.39mA    48.53mA
[Pullup]
|voltage   I(typ)   I(min)   I(max)
-1.8V     39.17mA    27.87mA    48.84mA
-1.5V     38.3mA     26.11mA    48.69mA
-1.3V     36.22mA    24.13mA    46.36mA
-1.2V     34.44mA    22.87mA    44.21mA
-1V       29.33mA    19.57mA    38mA
-700mV    20.03mA    13.01mA    27.2mA
100mV     -2.501mA   -1.506mA   -3.654mA
300mV     -6.611mA   -3.857mA   -9.419mA
500mV     -8.971mA   -5.188mA   -13.05mA
700mV     -9.891mA   -5.972mA   -14.98mA
1.1V      -10.89mA   -6.615mA   -16.53mA
3.6V      -12.63mA   -7.584mA   -20.3mA
[GND_clamp]
|voltage   I(typ)   I(min)   I(max)
-1.8V     -1.559A    -696.5mA   -12.99A
-1.1V     -296.4mA   -202.8mA   -979.3mA
-1V       -147.6mA   -138.6mA   -143.7mA
-900mV    -53.77mA   -80.42mA   -57.51mA
-800mV    -28mA      -35.97mA   -39.3mA
-700mV    -17.04mA   -14.79mA   -24.23mA
-600mV    -8.945mA   -7.5mA     -12.27mA
-500mV    -3.55mA    -3.594mA   -4.287mA
-400mV    -844.2uA   -1.305mA   -762uA
-300mV    -109.2uA   -290.3uA   -72.54uA
1.8V      100.3nA    783.2nA    29.03nA
[POWER_clamp]
|voltage   I(typ)   I(min)   I(max)
-1.8V     178.5mA    91.31mA    1.213A
-1.2V     41.11mA    25.02mA    244.3mA
-1.1V     23.87mA    16.9mA     108.1mA
-1V       10.45mA    9.859mA    16.11mA
-900mV    2.311mA    4.617mA    1.45mA
-800mV    197.4uA    1.514mA    355.7uA
-700mV    9.769uA    305.2uA    94.53uA
-600mV    528.6nA    35.7uA     22.97uA
0V        100.3nA    769nA      31.1nA
[Ramp]
| variable   typ   min   max
dV/dt_r   0.3289/0.3273ns   0.2014/0.4714ns   0.5419/0.2431ns
dV/dt_f   0.7315/1.0322ns   0.5583/2.0878ns   0.8623/0.4694ns
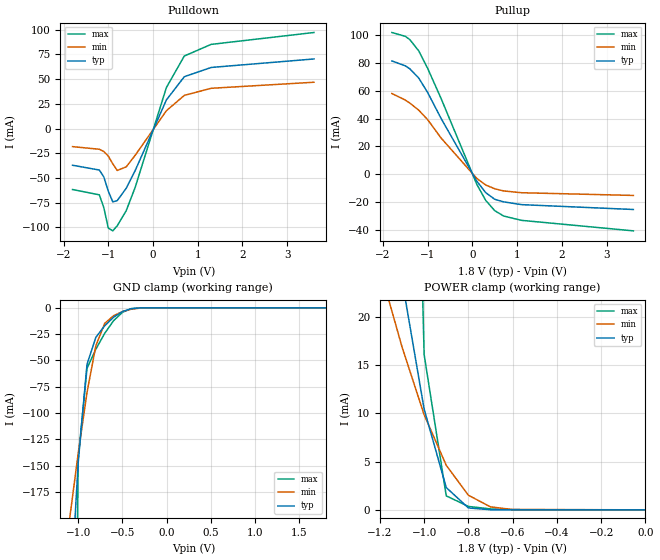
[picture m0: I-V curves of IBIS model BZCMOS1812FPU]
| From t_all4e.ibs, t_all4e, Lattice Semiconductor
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|   BZCMOS1812FPU
[Model]   BZCMOS1812FPU
Model_type   I/O
Polarity   Non-Inverting
Enable   Active-Low
C_comp   2pF   2pF   2pF
Vinl = 0.5
Vinh = 2.64
[Temperature Range]   25.0000   125.0000   -40.0000
[Voltage Range]   1.8000V   1.7000V   1.9000V
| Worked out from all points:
|   slope of the pulldown table from 0 to 0.27 V, typ, clamps not added: 10.3 ohm
|   slope of the pullup table from 0 to 0.27 V, typ, clamps not added: 22.3 ohm
|   GND clamp passes 1 mA (typ) near -0.41 V on its own axis
|   POWER clamp passes 1 mA (typ) near -0.84 V on its own axis
[Pulldown]
|voltage   I(typ)   I(min)   I(max)
-1.8V     -37.15mA   -18.33mA   -61.7mA
-1.2V     -42mA      -21mA      -67.06mA
-1.1V     -48.97mA   -23.26mA   -80.07mA
-1V       -63.34mA   -27.91mA   -100.7mA
-900mV    -74.18mA   -35.7mA    -103.5mA
-800mV    -72.91mA   -42.45mA   -98.37mA
-600mV    -60.5mA    -38.82mA   -83.17mA
-400mV    -42.67mA   -27.16mA   -59.71mA
300mV     28.92mA    18mA       41.48mA
700mV     52.35mA    33.47mA    73.29mA
1.3V      61.72mA    40.65mA    85.06mA
3.6V      70.31mA    46.78mA    97.07mA
[Pullup]
|voltage   I(typ)   I(min)   I(max)
-1.8V     81.38mA    58mA       101.8mA
-1.5V     77.86mA    53.27mA    99.04mA
-1.4V     75.75mA    51.16mA    96.71mA
-1.2V     69.07mA    46.03mA    88.6mA
-1V       58.66mA    39.19mA    76.01mA
-700mV    40.07mA    26.03mA    54.39mA
100mV     -5.002mA   -3.012mA   -7.307mA
300mV     -13.22mA   -7.713mA   -18.84mA
500mV     -17.94mA   -10.38mA   -26.11mA
700mV     -19.79mA   -11.95mA   -29.96mA
1.1V      -21.78mA   -13.23mA   -33.06mA
3.6V      -25.26mA   -15.17mA   -40.6mA
[GND_clamp]
|voltage   I(typ)   I(min)   I(max)
-1.8V     -1.559A    -696.5mA   -12.99A
-1.1V     -296.4mA   -202.8mA   -979.3mA
-1V       -147.6mA   -138.6mA   -143.7mA
-900mV    -53.77mA   -80.42mA   -57.51mA
-800mV    -28mA      -35.97mA   -39.3mA
-700mV    -17.04mA   -14.79mA   -24.23mA
-600mV    -8.945mA   -7.5mA     -12.27mA
-500mV    -3.55mA    -3.594mA   -4.287mA
-400mV    -844.2uA   -1.305mA   -762uA
-300mV    -109.2uA   -290.3uA   -72.54uA
1.8V      100.3nA    783.2nA    29.03nA
[POWER_clamp]
|voltage   I(typ)   I(min)   I(max)
-1.8V     178.5mA    91.31mA    1.213A
-1.2V     41.11mA    25.02mA    244.3mA
-1.1V     23.87mA    16.9mA     108.1mA
-1V       10.45mA    9.859mA    16.11mA
-900mV    2.311mA    4.617mA    1.45mA
-800mV    197.4uA    1.514mA    355.7uA
-700mV    9.769uA    305.2uA    94.53uA
-600mV    528.6nA    35.7uA     22.97uA
0V        100.3nA    769nA      31.1nA
[Ramp]
| variable   typ   min   max
dV/dt_r   0.5814/0.2955ns   0.3828/0.4907ns   0.8196/0.1700ns
dV/dt_f   0.8966/0.7099ns   0.7619/1.5741ns   0.9962/0.3022ns
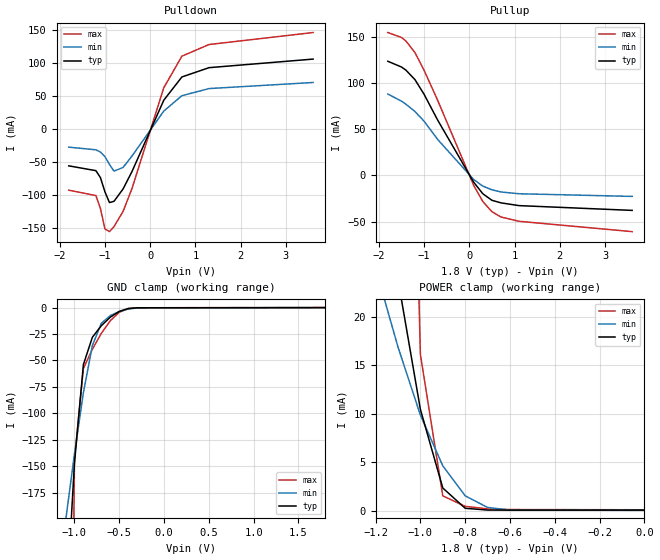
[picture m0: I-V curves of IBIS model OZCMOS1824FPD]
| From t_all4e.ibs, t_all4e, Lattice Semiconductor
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|   OZCMOS1824FPD
[Model]   OZCMOS1824FPD
Model_type   3-state
Polarity   Non-Inverting
Enable   Active-Low
C_comp   2pF   2pF   2pF
[Temperature Range]   25.0000   125.0000   -40.0000
[Voltage Range]   1.8000V   1.7000V   1.9000V
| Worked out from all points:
|   slope of the pulldown table from 0 to 0.27 V, typ, clamps not added: 6.85 ohm
|   slope of the pullup table from 0 to 0.27 V, typ, clamps not added: 14.9 ohm
|   GND clamp passes 1 mA (typ) near -0.40 V on its own axis
|   POWER clamp passes 1 mA (typ) near -0.84 V on its own axis
[Pulldown]
|voltage   I(typ)   I(min)   I(max)
-1.8V     -55.73mA   -27.5mA    -92.5mA
-1.2V     -62.99mA   -31.5mA    -100.6mA
-1.1V     -73.45mA   -34.88mA   -120.1mA
-1V       -95.01mA   -41.87mA   -151.1mA
-900mV    -111.2mA   -53.54mA   -155.1mA
-800mV    -109.3mA   -63.66mA   -147.5mA
-600mV    -90.71mA   -58.21mA   -124.7mA
-400mV    -63.97mA   -40.72mA   -89.52mA
300mV     43.36mA    26.99mA    62.17mA
700mV     78.49mA    50.18mA    109.9mA
1.3V      92.54mA    60.96mA    127.5mA
3.6V      105.5mA    70.17mA    145.6mA
[Pullup]
|voltage   I(typ)   I(min)   I(max)
-1.8V     123.6mA    88.14mA    154.7mA
-1.5V     117.4mA    80.43mA    149.4mA
-1.4V     114mA      77.12mA    145.6mA
-1.2V     103.7mA    69.18mA    133mA
-1V       87.99mA    58.81mA    114mA
-700mV    60.07mA    39.03mA    81.51mA
100mV     -7.54mA    -4.533mA   -11.04mA
300mV     -19.87mA   -11.59mA   -28.33mA
500mV     -26.95mA   -15.58mA   -39.24mA
700mV     -29.72mA   -17.94mA   -45.03mA
1.1V      -32.72mA   -19.87mA   -49.68mA
3.6V      -37.89mA   -22.75mA   -60.9mA
[GND_clamp]
|voltage   I(typ)   I(min)   I(max)
-1.8V     -1.559A    -696.5mA   -12.99A
-1.1V     -296.4mA   -202.8mA   -979.3mA
-1V       -147.6mA   -138.6mA   -143.7mA
-900mV    -53.79mA   -80.42mA   -57.6mA
-800mV    -28.05mA   -35.98mA   -39.41mA
-700mV    -17.1mA    -14.8mA    -24.32mA
-600mV    -8.998mA   -7.523mA   -12.36mA
-500mV    -3.594mA   -3.617mA   -4.358mA
-400mV    -878.9uA   -1.323mA   -817.5uA
-300mV    -133.8uA   -302.9uA   -112.1uA
1.8V      37.23uA    16.06uA    76uA
[POWER_clamp]
|voltage   I(typ)   I(min)   I(max)
-1.8V     178.5mA    91.31mA    1.213A
-1.2V     41.11mA    25.02mA    244.3mA
-1.1V     23.87mA    16.9mA     108.1mA
-1V       10.45mA    9.86mA     16.13mA
-900mV    2.324mA    4.618mA    1.514mA
-800mV    230.5uA    1.518mA    431.6uA
-700mV    46.81uA    315.4uA    170.6uA
-600mV    37.66uA    50.45uA    98.99uA
0V        37.23uA    16.04uA    76.01uA
[Ramp]
| variable   typ   min   max
dV/dt_r   0.7403/0.2541ns   0.5299/0.4462ns   0.9355/0.1375ns
dV/dt_f   0.9554/0.5883ns   0.8418/1.3300ns   1.0428/0.2446ns
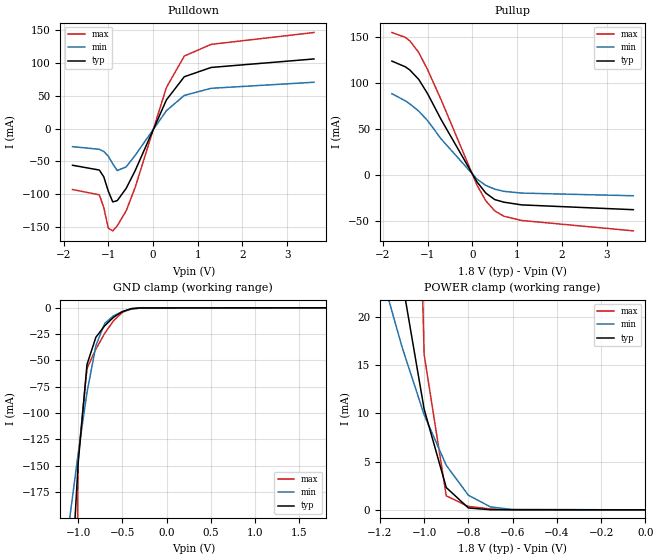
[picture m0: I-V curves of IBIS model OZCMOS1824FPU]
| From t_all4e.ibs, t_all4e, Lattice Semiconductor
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|   OZCMOS1824FPU
[Model]   OZCMOS1824FPU
Model_type   3-state
Polarity   Non-Inverting
Enable   Active-Low
C_comp   2pF   2pF   2pF
[Temperature Range]   25.0000   125.0000   -40.0000
[Voltage Range]   1.8000V   1.7000V   1.9000V
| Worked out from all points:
|   slope of the pulldown table from 0 to 0.27 V, typ, clamps not added: 6.84 ohm
|   slope of the pullup table from 0 to 0.27 V, typ, clamps not added: 14.9 ohm
|   GND clamp passes 1 mA (typ) near -0.41 V on its own axis
|   POWER clamp passes 1 mA (typ) near -0.84 V on its own axis
[Pulldown]
|voltage   I(typ)   I(min)   I(max)
-1.8V     -55.73mA   -27.5mA    -92.5mA
-1.2V     -62.99mA   -31.5mA    -100.6mA
-1.1V     -73.46mA   -34.89mA   -120.1mA
-1V       -95.02mA   -41.87mA   -151.1mA
-900mV    -111.3mA   -53.55mA   -155.2mA
-800mV    -109.4mA   -63.67mA   -147.6mA
-600mV    -90.76mA   -58.24mA   -124.8mA
-400mV    -64mA      -40.74mA   -89.57mA
300mV     43.38mA    27mA       62.22mA
700mV     78.53mA    50.2mA     109.9mA
1.3V      92.58mA    60.97mA    127.6mA
3.6V      105.5mA    70.17mA    145.6mA
[Pullup]
|voltage   I(typ)   I(min)   I(max)
-1.8V     123.6mA    88.14mA    154.7mA
-1.5V     117.4mA    80.43mA    149.4mA
-1.4V     114mA      77.12mA    145.6mA
-1.2V     103.7mA    69.18mA    133mA
-1V       87.99mA    58.81mA    114mA
-700mV    60.1mA     39.04mA    81.59mA
100mV     -7.503mA   -4.518mA   -10.96mA
300mV     -19.83mA   -11.57mA   -28.26mA
500mV     -26.91mA   -15.56mA   -39.16mA
700mV     -29.68mA   -17.92mA   -44.95mA
1.1V      -32.68mA   -19.85mA   -49.6mA
3.6V      -37.89mA   -22.75mA   -60.9mA
[GND_clamp]
|voltage   I(typ)   I(min)   I(max)
-1.8V     -1.559A    -696.5mA   -12.99A
-1.1V     -296.4mA   -202.8mA   -979.3mA
-1V       -147.6mA   -138.6mA   -143.7mA
-900mV    -53.77mA   -80.42mA   -57.51mA
-800mV    -28mA      -35.97mA   -39.3mA
-700mV    -17.04mA   -14.79mA   -24.23mA
-600mV    -8.945mA   -7.5mA     -12.27mA
-500mV    -3.55mA    -3.594mA   -4.287mA
-400mV    -844.2uA   -1.305mA   -762uA
-300mV    -109.2uA   -290.3uA   -72.54uA
1.8V      100.3nA    783.2nA    29.03nA
[POWER_clamp]
|voltage   I(typ)   I(min)   I(max)
-1.8V     178.5mA    91.31mA    1.213A
-1.2V     41.11mA    25.02mA    244.3mA
-1.1V     23.87mA    16.9mA     108.1mA
-1V       10.45mA    9.859mA    16.11mA
-900mV    2.311mA    4.617mA    1.45mA
-800mV    197.4uA    1.514mA    355.7uA
-700mV    9.769uA    305.2uA    94.53uA
-600mV    528.6nA    35.7uA     22.97uA
0V        100.3nA    769nA      31.1nA
[Ramp]
| variable   typ   min   max
dV/dt_r   0.7403/0.2541ns   0.5299/0.4462ns   0.9355/0.1375ns
dV/dt_f   0.9554/0.5883ns   0.8418/1.3300ns   1.0428/0.2446ns
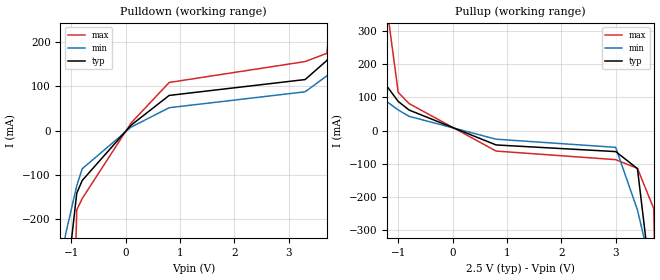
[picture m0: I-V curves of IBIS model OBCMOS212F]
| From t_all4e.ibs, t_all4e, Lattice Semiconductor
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|   OBCMOS212F
[Model]   OBCMOS212F
Model_type   Output
Polarity   Non-Inverting
C_comp   2pF   2pF   2pF
[Temperature Range]   25.0000   125.0000   -40.0000
[Voltage Range]   2.5000V   2.3000V   2.7000V
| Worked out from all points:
|   slope of the pulldown table from 0 to 0.375 V, typ, clamps not added: 8.75 ohm
|   slope of the pullup table from 0 to 0.375 V, typ, clamps not added: 14.4 ohm
[Pulldown]
|voltage   I(typ)   I(min)   I(max)
-2.5V     -2.929A    -1.233A    -25.83A
-1.3V     -689.6mA   -364mA     -4.209A
-1.1V     -360.4mA   -232.7mA   -1.083A
-900mV    -142.2mA   -125.2mA   -180.3mA
-800mV    -113.4mA   -86.81mA   -154.4mA
100mV     12.24mA    7.787mA    17.21mA
800mV     79.69mA    51.75mA    109.1mA
3.3V      115.7mA    87.91mA    156.5mA
3.7V      159mA      124.2mA    175.3mA
3.9V      201.9mA    148.6mA    405.3mA
4.5V      362.1mA    240.6mA    1.384A
5V        517.7mA    329.8mA    2.258A
[Pullup]
|voltage   I(typ)   I(min)   I(max)
-2.5V     507.8mA    295.9mA    2.591A
-2.1V     382.9mA    223.9mA    1.882A
-1.3V     157mA      98.83mA    518.3mA
-1.2V     131.7mA    86.01mA    360.5mA
-1V       87.59mA    61.91mA    115.2mA
-800mV    61.7mA     42.71mA    81.11mA
800mV     -43.37mA   -26.06mA   -61.83mA
3V        -63.39mA   -50.61mA   -87.65mA
3.4V      -114.6mA   -239.1mA   -113.9mA
3.7V      -525.6mA   -446mA     -234.9mA
3.8V      -701.6mA   -517.2mA   -1.071A
5V        -2.944A    -1.396A    -22.18A
[Ramp]
| variable   typ   min   max
dV/dt_r   1.1028/0.2688ns   0.8187/0.4833ns   1.3382/0.1412ns
dV/dt_f   1.2797/0.3792ns   1.0888/0.8737ns   1.4359/0.1769ns
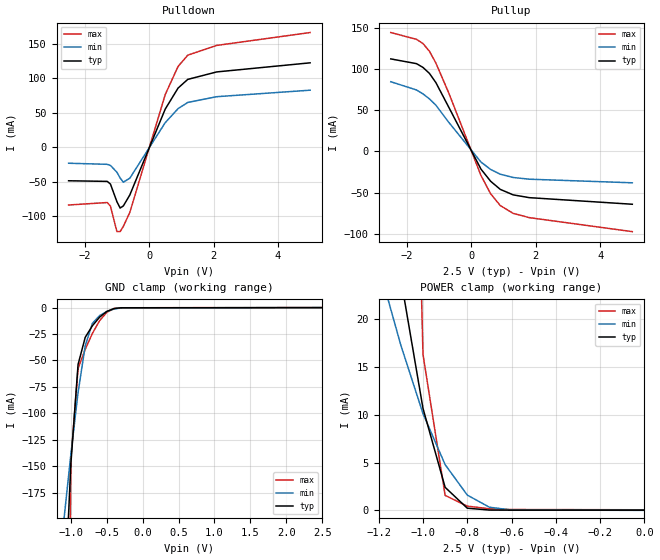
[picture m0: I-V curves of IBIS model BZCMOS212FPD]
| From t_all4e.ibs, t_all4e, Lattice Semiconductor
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|   BZCMOS212FPD
[Model]   BZCMOS212FPD
Model_type   I/O
Polarity   Non-Inverting
Enable   Active-Low
C_comp   2pF   2pF   2pF
Vinl = 0.5
Vinh = 2.64
[Temperature Range]   25.0000   125.0000   -40.0000
[Voltage Range]   2.5000V   2.3000V   2.7000V
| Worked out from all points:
|   slope of the pulldown table from 0 to 0.375 V, typ, clamps not added: 8.75 ohm
|   slope of the pullup table from 0 to 0.375 V, typ, clamps not added: 14.4 ohm
|   GND clamp passes 1 mA (typ) near -0.40 V on its own axis
|   POWER clamp passes 1 mA (typ) near -0.83 V on its own axis
[Pulldown]
|voltage   I(typ)   I(min)   I(max)
-2.5V     -48.8mA    -23.34mA   -84mA
-1.3V     -49.7mA    -24.91mA   -80.43mA
-1.2V     -53.63mA   -26.59mA   -85.64mA
-1V       -79.19mA   -36.36mA   -122.6mA
-900mV    -88.4mA    -44.81mA   -122.7mA
-800mV    -85.34mA   -50.83mA   -115mA
-600mV    -69.53mA   -45.12mA   -94.93mA
500mV     55.24mA    35.55mA    76.37mA
900mV     85.88mA    55.98mA    117.3mA
1.2V      98.44mA    64.96mA    133.6mA
2.1V      109.3mA    73.31mA    147.8mA
5V        122.5mA    82.76mA    166.5mA
[Pullup]
|voltage   I(typ)   I(min)   I(max)
-2.5V     112.7mA    84.9mA     144.8mA
-1.7V     106.9mA    74.88mA    136.5mA
-1.5V     102.3mA    70.1mA     131.4mA
-1.3V     95.06mA    64.02mA    122mA
-1.1V     83.89mA    56.39mA    107.7mA
-700mV    53.9mA     35.54mA    71.28mA
300mV     -21.45mA   -12.87mA   -29.21mA
600mV     -36.24mA   -21.85mA   -51.49mA
900mV     -46.14mA   -27.68mA   -65.82mA
1.3V      -52.82mA   -31.67mA   -75.32mA
1.8V      -56.21mA   -33.75mA   -80.53mA
5V        -64.25mA   -38.14mA   -97.6mA
[GND_clamp]
|voltage   I(typ)   I(min)   I(max)
-2.5V     -2.88A     -1.21A     -25.75A
-1.1V     -296.4mA   -202.8mA   -979.3mA
-1V       -147.6mA   -138.6mA   -143.7mA
-900mV    -53.79mA   -80.42mA   -57.6mA
-800mV    -28.05mA   -35.98mA   -39.41mA
-700mV    -17.1mA    -14.8mA    -24.32mA
-600mV    -8.999mA   -7.523mA   -12.36mA
-500mV    -3.595mA   -3.617mA   -4.359mA
-400mV    -879.6uA   -1.324mA   -818.4uA
-300mV    -134.3uA   -303.2uA   -112.8uA
2.5V      32.9uA     13.5uA     72.78uA
[POWER_clamp]
|voltage   I(typ)   I(min)   I(max)
-2.5V     395.1mA    211mA      2.446A
-1.2V     41.69mA    25.58mA    245.1mA
-1.1V     24.27mA    17.3mA     108.6mA
-1V       10.69mA    10.14mA    16.34mA
-900mV    2.423mA    4.798mA    1.578mA
-800mV    241uA      1.613mA    455.8uA
-700mV    43.59uA    342.3uA    178.8uA
-600mV    33.48uA    49.81uA    99.8uA
0V        32.9uA     13.46uA    72.82uA
[Ramp]
| variable   typ   min   max
dV/dt_r   1.1028/0.2688ns   0.8187/0.4833ns   1.3382/0.1412ns
dV/dt_f   1.2797/0.3792ns   1.0888/0.8737ns   1.4359/0.1769ns
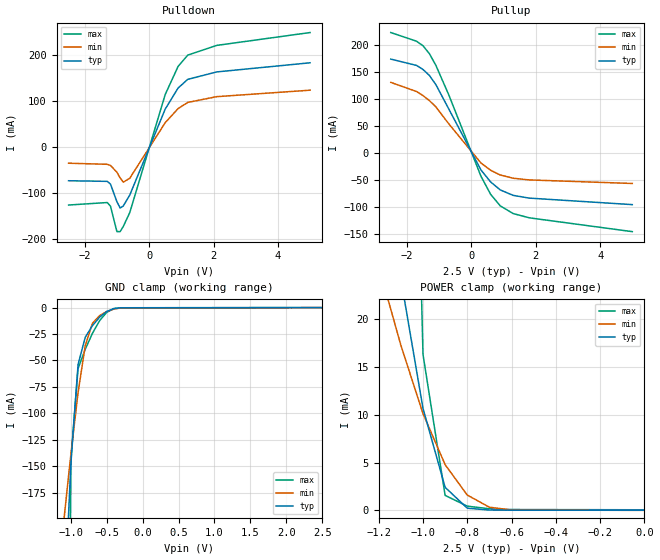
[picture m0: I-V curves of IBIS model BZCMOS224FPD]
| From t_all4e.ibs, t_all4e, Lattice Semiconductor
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|   BZCMOS224FPD
[Model]   BZCMOS224FPD
Model_type   I/O
Polarity   Non-Inverting
Enable   Active-Low
C_comp   2pF   2pF   2pF
Vinl = 0.5
Vinh = 2.64
[Temperature Range]   25.0000   125.0000   -40.0000
[Voltage Range]   2.5000V   2.3000V   2.7000V
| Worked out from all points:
|   slope of the pulldown table from 0 to 0.375 V, typ, clamps not added: 5.83 ohm
|   slope of the pullup table from 0 to 0.375 V, typ, clamps not added: 9.61 ohm
|   GND clamp passes 1 mA (typ) near -0.40 V on its own axis
|   POWER clamp passes 1 mA (typ) near -0.83 V on its own axis
[Pulldown]
|voltage   I(typ)   I(min)   I(max)
-2.5V     -73.2mA    -35.01mA   -126.1mA
-1.3V     -74.55mA   -37.37mA   -120.7mA
-1.2V     -80.45mA   -39.89mA   -128.5mA
-1V       -118.8mA   -54.55mA   -184mA
-900mV    -132.6mA   -67.22mA   -184.1mA
-800mV    -128mA     -76.25mA   -172.6mA
-600mV    -104.3mA   -67.69mA   -142.4mA
500mV     82.87mA    53.33mA    114.6mA
900mV     128.8mA    83.97mA    175.9mA
1.2V      147.7mA    97.44mA    200.5mA
2.1V      163.9mA    110mA      221.7mA
5V        183.8mA    124.1mA    249.7mA
[Pullup]
|voltage   I(typ)   I(min)   I(max)
-2.5V     173.1mA    130mA      222.3mA
-1.7V     161.4mA    113.1mA    206.2mA
-1.5V     153.9mA    105.6mA    197.8mA
-1.3V     142.8mA    96.23mA    183.1mA
-1.1V     125.9mA    84.64mA    161.5mA
-700mV    80.86mA    53.32mA    107mA
300mV     -32.16mA   -19.3mA    -43.78mA
600mV     -54.34mA   -32.77mA   -77.2mA
900mV     -69.19mA   -41.51mA   -98.69mA
1.3V      -79.21mA   -47.49mA   -112.9mA
1.8V      -84.3mA    -50.62mA   -120.8mA
5V        -96.37mA   -57.2mA    -146.4mA
[GND_clamp]
|voltage   I(typ)   I(min)   I(max)
-2.5V     -2.88A     -1.21A     -25.75A
-1.1V     -296.4mA   -202.8mA   -979.3mA
-1V       -147.6mA   -138.6mA   -143.7mA
-900mV    -53.79mA   -80.42mA   -57.6mA
-800mV    -28.05mA   -35.98mA   -39.41mA
-700mV    -17.1mA    -14.8mA    -24.32mA
-600mV    -8.999mA   -7.523mA   -12.36mA
-500mV    -3.595mA   -3.617mA   -4.359mA
-400mV    -879.6uA   -1.324mA   -818.4uA
-300mV    -134.3uA   -303.2uA   -112.8uA
2.5V      32.9uA     13.5uA     72.78uA
[POWER_clamp]
|voltage   I(typ)   I(min)   I(max)
-2.5V     395.1mA    211mA      2.446A
-1.2V     41.69mA    25.58mA    245.1mA
-1.1V     24.27mA    17.3mA     108.6mA
-1V       10.69mA    10.14mA    16.34mA
-900mV    2.423mA    4.798mA    1.578mA
-800mV    241uA      1.613mA    455.8uA
-700mV    43.59uA    342.3uA    178.8uA
-600mV    33.48uA    49.81uA    99.8uA
0V        32.9uA     13.46uA    72.82uA
[Ramp]
| variable   typ   min   max
dV/dt_r   1.2302/0.2319ns   0.9845/0.4297ns   1.4301/0.1214ns
dV/dt_f   1.3495/0.2982ns   1.1782/0.7105ns   1.4950/0.1354ns
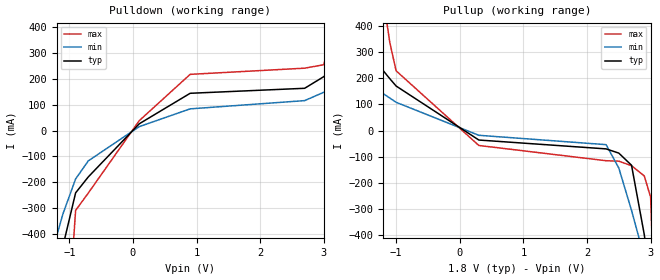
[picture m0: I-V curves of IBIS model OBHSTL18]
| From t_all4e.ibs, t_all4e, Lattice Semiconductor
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|   OBHSTL18
[Model]   OBHSTL18
Model_type   Output
Polarity   Non-Inverting
C_comp   2pF   2pF   2pF
[Temperature Range]   25.0000   125.0000   -40.0000
[Voltage Range]   1.8000V   1.6000V   2.0000V
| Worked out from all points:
|   slope of the pulldown table from 0 to 0.27 V, typ, clamps not added: 4.22 ohm
|   slope of the pullup table from 0 to 0.27 V, typ, clamps not added: 8.14 ohm
[Pulldown]
|voltage   I(typ)   I(min)   I(max)
-1.8V     -1.74A     -963.9mA   -10.37A
-1.3V     -781.2mA   -495.6mA   -3.439A
-1.1V     -447.4mA   -322.5mA   -1.035A
-900mV    -240.7mA   -186.9mA   -308.3mA
-700mV    -178.9mA   -117mA     -241.2mA
100mV     25.96mA    15mA       38.07mA
900mV     143.8mA    83.67mA    216.9mA
2.7V      163.1mA    115.5mA    240.8mA
3V        208mA      147.7mA    254mA
3.1V      230mA      159.8mA    347.5mA
3.2V      253.6mA    172.6mA    501.4mA
3.6V      357mA      229mA      1.222A
[Pullup]
|voltage   I(typ)   I(min)   I(max)
-1.8V     411.4mA    242.7mA    1.632A
-1.2V     228.4mA    140.8mA    503.5mA
-1.1V     198.7mA    124.4mA    338mA
-1V       170.4mA    108.1mA    228.7mA
300mV     -36.38mA   -18.28mA   -57.26mA
2.3V      -70.33mA   -54.12mA   -115.6mA
2.5V      -86.51mA   -143.7mA   -117.4mA
2.7V      -133.1mA   -305.8mA   -134.8mA
2.9V      -398.2mA   -485.7mA   -173.9mA
3V        -575.3mA   -578.3mA   -255.3mA
3.1V      -760.3mA   -672mA     -939.7mA
3.6V      -1.726A    -1.149A    -7.541A
[Ramp]
| variable   typ   min   max
dV/dt_r   0.9023/0.2114ns   0.6590/0.3993ns   1.0772/0.1200ns
dV/dt_f   1.0017/0.4559ns   0.8424/1.0125ns   1.1401/0.2130ns
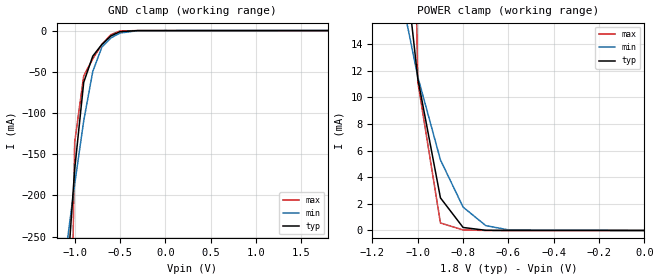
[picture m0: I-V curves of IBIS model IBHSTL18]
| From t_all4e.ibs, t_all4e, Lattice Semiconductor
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|   IBHSTL18
[Model]   IBHSTL18
Model_type   Input
Polarity   Non-Inverting
C_comp   2pF   2pF   2pF
Vinl = 0.8
Vinh = 1
[Temperature Range]   25.0000   125.0000   -40.0000
[Voltage Range]   1.8000V   1.6000V   2.0000V
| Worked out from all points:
|   GND clamp passes 1 mA (typ) near -0.47 V on its own axis
|   POWER clamp passes 1 mA (typ) near -0.83 V on its own axis
[GND_clamp]
|voltage   I(typ)   I(min)   I(max)
-1.8V     -1.653A    -921.9mA   0A
-1.7V     -1.458A    -826.5mA   0A
-1.6V     -1.263A    -731.5mA   -7.418A
-1.1V     -327.5mA   -271.4mA   -819.8mA
-1V       -168.7mA   -186.6mA   -135.9mA
-900mV    -62.81mA   -109.4mA   -54.98mA
-800mV    -30.98mA   -49.61mA   -34.21mA
-700mV    -16.85mA   -20.11mA   -16.92mA
-600mV    -6.553mA   -8.928mA   -4.949mA
-500mV    -1.298mA   -2.974mA   -567uA
-300mV    -6.365uA   -71.63uA   -561.6nA
1.8V      554.7pA    48.02nA    241.8pA
[POWER_clamp]
|voltage   I(typ)   I(min)   I(max)
-1.8V     190.4mA    102mA      1.346A
-1.1V     26.84mA    19.94mA    103.9mA
-1V       11.42mA    11.55mA    11.17mA
-900mV    2.448mA    5.301mA    563.4uA
-800mV    225.7uA    1.754mA    38.62uA
-700mV    12.81uA    365.7uA    1.897uA
-600mV    680.6nA    43.34uA    60.97nA
0V        554.7pA    43.92nA    295.4pA
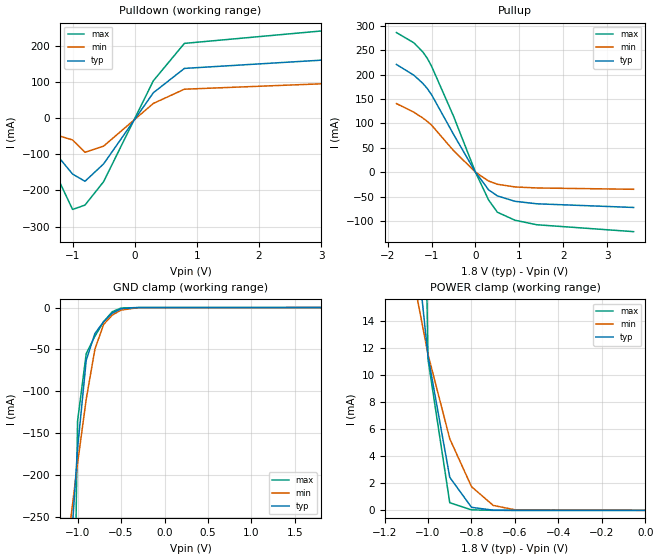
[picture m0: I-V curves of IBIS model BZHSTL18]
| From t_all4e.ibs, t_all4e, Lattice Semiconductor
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|   BZHSTL18
[Model]   BZHSTL18
Model_type   I/O
Polarity   Non-Inverting
Enable   Active-Low
C_comp   2pF   2pF   2pF
Vinl = 0.8
Vinh = 1
[Temperature Range]   25.0000   125.0000   -40.0000
[Voltage Range]   1.8000V   1.6000V   2.0000V
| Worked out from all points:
|   slope of the pulldown table from 0 to 0.27 V, typ, clamps not added: 4.22 ohm
|   slope of the pullup table from 0 to 0.27 V, typ, clamps not added: 8.14 ohm
|   GND clamp passes 1 mA (typ) near -0.47 V on its own axis
|   POWER clamp passes 1 mA (typ) near -0.83 V on its own axis
[Pulldown]
|voltage   I(typ)   I(min)   I(max)
-1.8V     -86.88mA   -42.02mA   -10.37A
-1.7V     -86.81mA   -42.06mA   -8.954A
-1.6V     -86.99mA   -42.23mA   -131.7mA
-1.3V     -92.27mA   -44.53mA   -143.3mA
-1V       -154.6mA   -60.36mA   -252.5mA
-800mV    -174.6mA   -94.37mA   -240.4mA
-500mV    -126.4mA   -77.28mA   -175.5mA
300mV     70.24mA    40.75mA    103.4mA
800mV     137.6mA    80.11mA    206.8mA
3.4V      164.5mA    97.7mA     247.3mA
3.5V      165.4mA    214.1mA    249.1mA
3.6V      166.6mA    229mA      251.2mA
[Pullup]
|voltage   I(typ)   I(min)   I(max)
-1.8V     221mA      140.7mA    286.4mA
-1.4V     198.7mA    122.8mA    265.2mA
-1.2V     182.3mA    111.2mA    246.7mA
-1.1V     171.9mA    104.4mA    234.1mA
-1V       159mA      96.53mA    217.5mA
-500mV    77.67mA    44.29mA    115mA
0V        0A         0A         0A
300mV     -36.38mA   -18.28mA   -57.26mA
500mV     -48.77mA   -24.9mA    -82.3mA
900mV     -59.86mA   -30.38mA   -98.7mA
1.4V      -64.97mA   -32.49mA   -108mA
3.6V      -72.5mA    -35.2mA    -122.1mA
[GND_clamp]
|voltage   I(typ)   I(min)   I(max)
-1.8V     -1.653A    -921.9mA   0A
-1.7V     -1.458A    -826.5mA   0A
-1.6V     -1.263A    -731.5mA   -7.418A
-1.1V     -327.5mA   -271.4mA   -819.8mA
-1V       -168.7mA   -186.6mA   -135.9mA
-900mV    -62.81mA   -109.4mA   -54.98mA
-800mV    -30.98mA   -49.61mA   -34.21mA
-700mV    -16.85mA   -20.11mA   -16.92mA
-600mV    -6.553mA   -8.928mA   -4.949mA
-500mV    -1.298mA   -2.974mA   -567uA
-300mV    -6.365uA   -71.63uA   -561.6nA
1.8V      554.7pA    48.02nA    241.8pA
[POWER_clamp]
|voltage   I(typ)   I(min)   I(max)
-1.8V     190.4mA    102mA      1.346A
-1.1V     26.84mA    19.94mA    103.9mA
-1V       11.42mA    11.55mA    11.17mA
-900mV    2.448mA    5.301mA    563.4uA
-800mV    225.7uA    1.754mA    38.62uA
-700mV    12.81uA    365.7uA    1.897uA
-600mV    680.6nA    43.34uA    60.97nA
0V        554.7pA    43.92nA    295.4pA
[Ramp]
| variable   typ   min   max
dV/dt_r   0.9023/0.2114ns   0.6590/0.3993ns   1.0772/0.1200ns
dV/dt_f   1.0017/0.4559ns   0.8424/1.0125ns   1.1401/0.2130ns
